VERSION 5.8 ;
BUSBITCHARS "[]" ;
DIVIDERCHAR "/" ;
UNITS
    DATABASE MICRONS 1000 ;
END UNITS

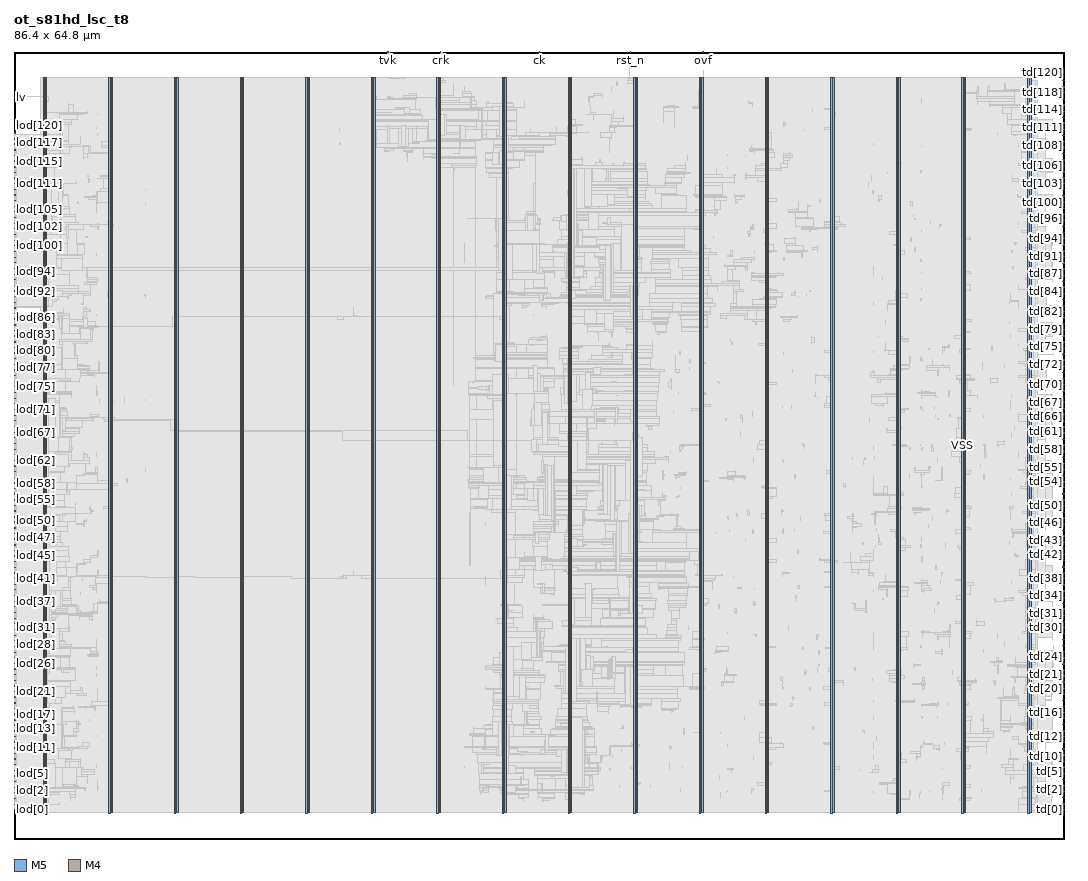
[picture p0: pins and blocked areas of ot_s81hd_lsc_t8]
MACRO ot_s81hd_lsc_t8
  FOREIGN ot_s81hd_lsc_t8 0 0 ;
  CLASS BLOCK ;
  SIZE 86.4 BY 64.8 ;
  PIN ck
    DIRECTION INPUT ;
    USE SIGNAL ;
    PORT
      LAYER M5 ;
        RECT  43.2 64.716 43.224 64.8 ;
    END
  END ck
  PIN crk
    DIRECTION INPUT ;
    USE SIGNAL ;
    PORT
      LAYER M5 ;
        RECT  35.088 64.716 35.112 64.8 ;
    END
  END crk
  PIN lod[0]
    DIRECTION OUTPUT ;
    USE SIGNAL ;
    PORT
      LAYER M4 ;
        RECT  0 2.4 0.084 2.424 ;
    END
  END lod[0]
  PIN lod[100]
    DIRECTION OUTPUT ;
    USE SIGNAL ;
    PORT
      LAYER M4 ;
        RECT  0 48.816 0.084 48.84 ;
    END
  END lod[100]
  PIN lod[101]
    DIRECTION OUTPUT ;
    USE SIGNAL ;
    PORT
      LAYER M4 ;
        RECT  0 49.248 0.084 49.272 ;
    END
  END lod[101]
  PIN lod[102]
    DIRECTION OUTPUT ;
    USE SIGNAL ;
    PORT
      LAYER M4 ;
        RECT  0 49.728 0.084 49.752 ;
    END
  END lod[102]
  PIN lod[103]
    DIRECTION OUTPUT ;
    USE SIGNAL ;
    PORT
      LAYER M4 ;
        RECT  0 50.208 0.084 50.232 ;
    END
  END lod[103]
  PIN lod[104]
    DIRECTION OUTPUT ;
    USE SIGNAL ;
    PORT
      LAYER M4 ;
        RECT  0 50.64 0.084 50.664 ;
    END
  END lod[104]
  PIN lod[105]
    DIRECTION OUTPUT ;
    USE SIGNAL ;
    PORT
      LAYER M4 ;
        RECT  0 51.12 0.084 51.144 ;
    END
  END lod[105]
  PIN lod[106]
    DIRECTION OUTPUT ;
    USE SIGNAL ;
    PORT
      LAYER M4 ;
        RECT  0 51.6 0.084 51.624 ;
    END
  END lod[106]
  PIN lod[107]
    DIRECTION OUTPUT ;
    USE SIGNAL ;
    PORT
      LAYER M4 ;
        RECT  0 52.032 0.084 52.056 ;
    END
  END lod[107]
  PIN lod[108]
    DIRECTION OUTPUT ;
    USE SIGNAL ;
    PORT
      LAYER M4 ;
        RECT  0 52.512 0.084 52.536 ;
    END
  END lod[108]
  PIN lod[109]
    DIRECTION OUTPUT ;
    USE SIGNAL ;
    PORT
      LAYER M4 ;
        RECT  0 52.992 0.084 53.016 ;
    END
  END lod[109]
  PIN lod[10]
    DIRECTION OUTPUT ;
    USE SIGNAL ;
    PORT
      LAYER M4 ;
        RECT  0 7.008 0.084 7.032 ;
    END
  END lod[10]
  PIN lod[110]
    DIRECTION OUTPUT ;
    USE SIGNAL ;
    PORT
      LAYER M4 ;
        RECT  0 53.424 0.084 53.448 ;
    END
  END lod[110]
  PIN lod[111]
    DIRECTION OUTPUT ;
    USE SIGNAL ;
    PORT
      LAYER M4 ;
        RECT  0 53.904 0.084 53.928 ;
    END
  END lod[111]
  PIN lod[112]
    DIRECTION OUTPUT ;
    USE SIGNAL ;
    PORT
      LAYER M4 ;
        RECT  0 54.384 0.084 54.408 ;
    END
  END lod[112]
  PIN lod[113]
    DIRECTION OUTPUT ;
    USE SIGNAL ;
    PORT
      LAYER M4 ;
        RECT  0 54.816 0.084 54.84 ;
    END
  END lod[113]
  PIN lod[114]
    DIRECTION OUTPUT ;
    USE SIGNAL ;
    PORT
      LAYER M4 ;
        RECT  0 55.296 0.084 55.32 ;
    END
  END lod[114]
  PIN lod[115]
    DIRECTION OUTPUT ;
    USE SIGNAL ;
    PORT
      LAYER M4 ;
        RECT  0 55.776 0.084 55.8 ;
    END
  END lod[115]
  PIN lod[116]
    DIRECTION OUTPUT ;
    USE SIGNAL ;
    PORT
      LAYER M4 ;
        RECT  0 56.208 0.084 56.232 ;
    END
  END lod[116]
  PIN lod[117]
    DIRECTION OUTPUT ;
    USE SIGNAL ;
    PORT
      LAYER M4 ;
        RECT  0 56.688 0.084 56.712 ;
    END
  END lod[117]
  PIN lod[118]
    DIRECTION OUTPUT ;
    USE SIGNAL ;
    PORT
      LAYER M4 ;
        RECT  0 57.168 0.084 57.192 ;
    END
  END lod[118]
  PIN lod[119]
    DIRECTION OUTPUT ;
    USE SIGNAL ;
    PORT
      LAYER M4 ;
        RECT  0 57.6 0.084 57.624 ;
    END
  END lod[119]
  PIN lod[11]
    DIRECTION OUTPUT ;
    USE SIGNAL ;
    PORT
      LAYER M4 ;
        RECT  0 7.488 0.084 7.512 ;
    END
  END lod[11]
  PIN lod[120]
    DIRECTION OUTPUT ;
    USE SIGNAL ;
    PORT
      LAYER M4 ;
        RECT  0 58.08 0.084 58.104 ;
    END
  END lod[120]
  PIN lod[12]
    DIRECTION OUTPUT ;
    USE SIGNAL ;
    PORT
      LAYER M4 ;
        RECT  0 7.968 0.084 7.992 ;
    END
  END lod[12]
  PIN lod[13]
    DIRECTION OUTPUT ;
    USE SIGNAL ;
    PORT
      LAYER M4 ;
        RECT  0 8.4 0.084 8.424 ;
    END
  END lod[13]
  PIN lod[14]
    DIRECTION OUTPUT ;
    USE SIGNAL ;
    PORT
      LAYER M4 ;
        RECT  0 8.88 0.084 8.904 ;
    END
  END lod[14]
  PIN lod[15]
    DIRECTION OUTPUT ;
    USE SIGNAL ;
    PORT
      LAYER M4 ;
        RECT  0 9.36 0.084 9.384 ;
    END
  END lod[15]
  PIN lod[16]
    DIRECTION OUTPUT ;
    USE SIGNAL ;
    PORT
      LAYER M4 ;
        RECT  0 9.792 0.084 9.816 ;
    END
  END lod[16]
  PIN lod[17]
    DIRECTION OUTPUT ;
    USE SIGNAL ;
    PORT
      LAYER M4 ;
        RECT  0 10.272 0.084 10.296 ;
    END
  END lod[17]
  PIN lod[18]
    DIRECTION OUTPUT ;
    USE SIGNAL ;
    PORT
      LAYER M4 ;
        RECT  0 10.752 0.084 10.776 ;
    END
  END lod[18]
  PIN lod[19]
    DIRECTION OUTPUT ;
    USE SIGNAL ;
    PORT
      LAYER M4 ;
        RECT  0 11.184 0.084 11.208 ;
    END
  END lod[19]
  PIN lod[1]
    DIRECTION OUTPUT ;
    USE SIGNAL ;
    PORT
      LAYER M4 ;
        RECT  0 2.832 0.084 2.856 ;
    END
  END lod[1]
  PIN lod[20]
    DIRECTION OUTPUT ;
    USE SIGNAL ;
    PORT
      LAYER M4 ;
        RECT  0 11.664 0.084 11.688 ;
    END
  END lod[20]
  PIN lod[21]
    DIRECTION OUTPUT ;
    USE SIGNAL ;
    PORT
      LAYER M4 ;
        RECT  0 12.144 0.084 12.168 ;
    END
  END lod[21]
  PIN lod[22]
    DIRECTION OUTPUT ;
    USE SIGNAL ;
    PORT
      LAYER M4 ;
        RECT  0 12.576 0.084 12.6 ;
    END
  END lod[22]
  PIN lod[23]
    DIRECTION OUTPUT ;
    USE SIGNAL ;
    PORT
      LAYER M4 ;
        RECT  0 13.056 0.084 13.08 ;
    END
  END lod[23]
  PIN lod[24]
    DIRECTION OUTPUT ;
    USE SIGNAL ;
    PORT
      LAYER M4 ;
        RECT  0 13.536 0.084 13.56 ;
    END
  END lod[24]
  PIN lod[25]
    DIRECTION OUTPUT ;
    USE SIGNAL ;
    PORT
      LAYER M4 ;
        RECT  0 13.968 0.084 13.992 ;
    END
  END lod[25]
  PIN lod[26]
    DIRECTION OUTPUT ;
    USE SIGNAL ;
    PORT
      LAYER M4 ;
        RECT  0 14.448 0.084 14.472 ;
    END
  END lod[26]
  PIN lod[27]
    DIRECTION OUTPUT ;
    USE SIGNAL ;
    PORT
      LAYER M4 ;
        RECT  0 14.928 0.084 14.952 ;
    END
  END lod[27]
  PIN lod[28]
    DIRECTION OUTPUT ;
    USE SIGNAL ;
    PORT
      LAYER M4 ;
        RECT  0 15.36 0.084 15.384 ;
    END
  END lod[28]
  PIN lod[29]
    DIRECTION OUTPUT ;
    USE SIGNAL ;
    PORT
      LAYER M4 ;
        RECT  0 15.84 0.084 15.864 ;
    END
  END lod[29]
  PIN lod[2]
    DIRECTION OUTPUT ;
    USE SIGNAL ;
    PORT
      LAYER M4 ;
        RECT  0 3.312 0.084 3.336 ;
    END
  END lod[2]
  PIN lod[30]
    DIRECTION OUTPUT ;
    USE SIGNAL ;
    PORT
      LAYER M4 ;
        RECT  0 16.32 0.084 16.344 ;
    END
  END lod[30]
  PIN lod[31]
    DIRECTION OUTPUT ;
    USE SIGNAL ;
    PORT
      LAYER M4 ;
        RECT  0 16.752 0.084 16.776 ;
    END
  END lod[31]
  PIN lod[32]
    DIRECTION OUTPUT ;
    USE SIGNAL ;
    PORT
      LAYER M4 ;
        RECT  0 17.232 0.084 17.256 ;
    END
  END lod[32]
  PIN lod[33]
    DIRECTION OUTPUT ;
    USE SIGNAL ;
    PORT
      LAYER M4 ;
        RECT  0 17.712 0.084 17.736 ;
    END
  END lod[33]
  PIN lod[34]
    DIRECTION OUTPUT ;
    USE SIGNAL ;
    PORT
      LAYER M4 ;
        RECT  0 18.144 0.084 18.168 ;
    END
  END lod[34]
  PIN lod[35]
    DIRECTION OUTPUT ;
    USE SIGNAL ;
    PORT
      LAYER M4 ;
        RECT  0 18.624 0.084 18.648 ;
    END
  END lod[35]
  PIN lod[36]
    DIRECTION OUTPUT ;
    USE SIGNAL ;
    PORT
      LAYER M4 ;
        RECT  0 19.104 0.084 19.128 ;
    END
  END lod[36]
  PIN lod[37]
    DIRECTION OUTPUT ;
    USE SIGNAL ;
    PORT
      LAYER M4 ;
        RECT  0 19.536 0.084 19.56 ;
    END
  END lod[37]
  PIN lod[38]
    DIRECTION OUTPUT ;
    USE SIGNAL ;
    PORT
      LAYER M4 ;
        RECT  0 20.016 0.084 20.04 ;
    END
  END lod[38]
  PIN lod[39]
    DIRECTION OUTPUT ;
    USE SIGNAL ;
    PORT
      LAYER M4 ;
        RECT  0 20.496 0.084 20.52 ;
    END
  END lod[39]
  PIN lod[3]
    DIRECTION OUTPUT ;
    USE SIGNAL ;
    PORT
      LAYER M4 ;
        RECT  0 3.792 0.084 3.816 ;
    END
  END lod[3]
  PIN lod[40]
    DIRECTION OUTPUT ;
    USE SIGNAL ;
    PORT
      LAYER M4 ;
        RECT  0 20.928 0.084 20.952 ;
    END
  END lod[40]
  PIN lod[41]
    DIRECTION OUTPUT ;
    USE SIGNAL ;
    PORT
      LAYER M4 ;
        RECT  0 21.408 0.084 21.432 ;
    END
  END lod[41]
  PIN lod[42]
    DIRECTION OUTPUT ;
    USE SIGNAL ;
    PORT
      LAYER M4 ;
        RECT  0 21.888 0.084 21.912 ;
    END
  END lod[42]
  PIN lod[43]
    DIRECTION OUTPUT ;
    USE SIGNAL ;
    PORT
      LAYER M4 ;
        RECT  0 22.32 0.084 22.344 ;
    END
  END lod[43]
  PIN lod[44]
    DIRECTION OUTPUT ;
    USE SIGNAL ;
    PORT
      LAYER M4 ;
        RECT  0 22.8 0.084 22.824 ;
    END
  END lod[44]
  PIN lod[45]
    DIRECTION OUTPUT ;
    USE SIGNAL ;
    PORT
      LAYER M4 ;
        RECT  0 23.28 0.084 23.304 ;
    END
  END lod[45]
  PIN lod[46]
    DIRECTION OUTPUT ;
    USE SIGNAL ;
    PORT
      LAYER M4 ;
        RECT  0 23.712 0.084 23.736 ;
    END
  END lod[46]
  PIN lod[47]
    DIRECTION OUTPUT ;
    USE SIGNAL ;
    PORT
      LAYER M4 ;
        RECT  0 24.192 0.084 24.216 ;
    END
  END lod[47]
  PIN lod[48]
    DIRECTION OUTPUT ;
    USE SIGNAL ;
    PORT
      LAYER M4 ;
        RECT  0 24.672 0.084 24.696 ;
    END
  END lod[48]
  PIN lod[49]
    DIRECTION OUTPUT ;
    USE SIGNAL ;
    PORT
      LAYER M4 ;
        RECT  0 25.104 0.084 25.128 ;
    END
  END lod[49]
  PIN lod[4]
    DIRECTION OUTPUT ;
    USE SIGNAL ;
    PORT
      LAYER M4 ;
        RECT  0 4.224 0.084 4.248 ;
    END
  END lod[4]
  PIN lod[50]
    DIRECTION OUTPUT ;
    USE SIGNAL ;
    PORT
      LAYER M4 ;
        RECT  0 25.584 0.084 25.608 ;
    END
  END lod[50]
  PIN lod[51]
    DIRECTION OUTPUT ;
    USE SIGNAL ;
    PORT
      LAYER M4 ;
        RECT  0 26.064 0.084 26.088 ;
    END
  END lod[51]
  PIN lod[52]
    DIRECTION OUTPUT ;
    USE SIGNAL ;
    PORT
      LAYER M4 ;
        RECT  0 26.496 0.084 26.52 ;
    END
  END lod[52]
  PIN lod[53]
    DIRECTION OUTPUT ;
    USE SIGNAL ;
    PORT
      LAYER M4 ;
        RECT  0 26.976 0.084 27 ;
    END
  END lod[53]
  PIN lod[54]
    DIRECTION OUTPUT ;
    USE SIGNAL ;
    PORT
      LAYER M4 ;
        RECT  0 27.456 0.084 27.48 ;
    END
  END lod[54]
  PIN lod[55]
    DIRECTION OUTPUT ;
    USE SIGNAL ;
    PORT
      LAYER M4 ;
        RECT  0 27.888 0.084 27.912 ;
    END
  END lod[55]
  PIN lod[56]
    DIRECTION OUTPUT ;
    USE SIGNAL ;
    PORT
      LAYER M4 ;
        RECT  0 28.368 0.084 28.392 ;
    END
  END lod[56]
  PIN lod[57]
    DIRECTION OUTPUT ;
    USE SIGNAL ;
    PORT
      LAYER M4 ;
        RECT  0 28.848 0.084 28.872 ;
    END
  END lod[57]
  PIN lod[58]
    DIRECTION OUTPUT ;
    USE SIGNAL ;
    PORT
      LAYER M4 ;
        RECT  0 29.28 0.084 29.304 ;
    END
  END lod[58]
  PIN lod[59]
    DIRECTION OUTPUT ;
    USE SIGNAL ;
    PORT
      LAYER M4 ;
        RECT  0 29.76 0.084 29.784 ;
    END
  END lod[59]
  PIN lod[5]
    DIRECTION OUTPUT ;
    USE SIGNAL ;
    PORT
      LAYER M4 ;
        RECT  0 4.704 0.084 4.728 ;
    END
  END lod[5]
  PIN lod[60]
    DIRECTION OUTPUT ;
    USE SIGNAL ;
    PORT
      LAYER M4 ;
        RECT  0 30.24 0.084 30.264 ;
    END
  END lod[60]
  PIN lod[61]
    DIRECTION OUTPUT ;
    USE SIGNAL ;
    PORT
      LAYER M4 ;
        RECT  0 30.672 0.084 30.696 ;
    END
  END lod[61]
  PIN lod[62]
    DIRECTION OUTPUT ;
    USE SIGNAL ;
    PORT
      LAYER M4 ;
        RECT  0 31.152 0.084 31.176 ;
    END
  END lod[62]
  PIN lod[63]
    DIRECTION OUTPUT ;
    USE SIGNAL ;
    PORT
      LAYER M4 ;
        RECT  0 31.632 0.084 31.656 ;
    END
  END lod[63]
  PIN lod[64]
    DIRECTION OUTPUT ;
    USE SIGNAL ;
    PORT
      LAYER M4 ;
        RECT  0 32.064 0.084 32.088 ;
    END
  END lod[64]
  PIN lod[65]
    DIRECTION OUTPUT ;
    USE SIGNAL ;
    PORT
      LAYER M4 ;
        RECT  0 32.544 0.084 32.568 ;
    END
  END lod[65]
  PIN lod[66]
    DIRECTION OUTPUT ;
    USE SIGNAL ;
    PORT
      LAYER M4 ;
        RECT  0 33.024 0.084 33.048 ;
    END
  END lod[66]
  PIN lod[67]
    DIRECTION OUTPUT ;
    USE SIGNAL ;
    PORT
      LAYER M4 ;
        RECT  0 33.456 0.084 33.48 ;
    END
  END lod[67]
  PIN lod[68]
    DIRECTION OUTPUT ;
    USE SIGNAL ;
    PORT
      LAYER M4 ;
        RECT  0 33.936 0.084 33.96 ;
    END
  END lod[68]
  PIN lod[69]
    DIRECTION OUTPUT ;
    USE SIGNAL ;
    PORT
      LAYER M4 ;
        RECT  0 34.416 0.084 34.44 ;
    END
  END lod[69]
  PIN lod[6]
    DIRECTION OUTPUT ;
    USE SIGNAL ;
    PORT
      LAYER M4 ;
        RECT  0 5.184 0.084 5.208 ;
    END
  END lod[6]
  PIN lod[70]
    DIRECTION OUTPUT ;
    USE SIGNAL ;
    PORT
      LAYER M4 ;
        RECT  0 34.848 0.084 34.872 ;
    END
  END lod[70]
  PIN lod[71]
    DIRECTION OUTPUT ;
    USE SIGNAL ;
    PORT
      LAYER M4 ;
        RECT  0 35.328 0.084 35.352 ;
    END
  END lod[71]
  PIN lod[72]
    DIRECTION OUTPUT ;
    USE SIGNAL ;
    PORT
      LAYER M4 ;
        RECT  0 35.808 0.084 35.832 ;
    END
  END lod[72]
  PIN lod[73]
    DIRECTION OUTPUT ;
    USE SIGNAL ;
    PORT
      LAYER M4 ;
        RECT  0 36.24 0.084 36.264 ;
    END
  END lod[73]
  PIN lod[74]
    DIRECTION OUTPUT ;
    USE SIGNAL ;
    PORT
      LAYER M4 ;
        RECT  0 36.72 0.084 36.744 ;
    END
  END lod[74]
  PIN lod[75]
    DIRECTION OUTPUT ;
    USE SIGNAL ;
    PORT
      LAYER M4 ;
        RECT  0 37.2 0.084 37.224 ;
    END
  END lod[75]
  PIN lod[76]
    DIRECTION OUTPUT ;
    USE SIGNAL ;
    PORT
      LAYER M4 ;
        RECT  0 37.632 0.084 37.656 ;
    END
  END lod[76]
  PIN lod[77]
    DIRECTION OUTPUT ;
    USE SIGNAL ;
    PORT
      LAYER M4 ;
        RECT  0 38.112 0.084 38.136 ;
    END
  END lod[77]
  PIN lod[78]
    DIRECTION OUTPUT ;
    USE SIGNAL ;
    PORT
      LAYER M4 ;
        RECT  0 38.592 0.084 38.616 ;
    END
  END lod[78]
  PIN lod[79]
    DIRECTION OUTPUT ;
    USE SIGNAL ;
    PORT
      LAYER M4 ;
        RECT  0 39.024 0.084 39.048 ;
    END
  END lod[79]
  PIN lod[7]
    DIRECTION OUTPUT ;
    USE SIGNAL ;
    PORT
      LAYER M4 ;
        RECT  0 5.616 0.084 5.64 ;
    END
  END lod[7]
  PIN lod[80]
    DIRECTION OUTPUT ;
    USE SIGNAL ;
    PORT
      LAYER M4 ;
        RECT  0 39.504 0.084 39.528 ;
    END
  END lod[80]
  PIN lod[81]
    DIRECTION OUTPUT ;
    USE SIGNAL ;
    PORT
      LAYER M4 ;
        RECT  0 39.984 0.084 40.008 ;
    END
  END lod[81]
  PIN lod[82]
    DIRECTION OUTPUT ;
    USE SIGNAL ;
    PORT
      LAYER M4 ;
        RECT  0 40.416 0.084 40.44 ;
    END
  END lod[82]
  PIN lod[83]
    DIRECTION OUTPUT ;
    USE SIGNAL ;
    PORT
      LAYER M4 ;
        RECT  0 40.896 0.084 40.92 ;
    END
  END lod[83]
  PIN lod[84]
    DIRECTION OUTPUT ;
    USE SIGNAL ;
    PORT
      LAYER M4 ;
        RECT  0 41.376 0.084 41.4 ;
    END
  END lod[84]
  PIN lod[85]
    DIRECTION OUTPUT ;
    USE SIGNAL ;
    PORT
      LAYER M4 ;
        RECT  0 41.808 0.084 41.832 ;
    END
  END lod[85]
  PIN lod[86]
    DIRECTION OUTPUT ;
    USE SIGNAL ;
    PORT
      LAYER M4 ;
        RECT  0 42.288 0.084 42.312 ;
    END
  END lod[86]
  PIN lod[87]
    DIRECTION OUTPUT ;
    USE SIGNAL ;
    PORT
      LAYER M4 ;
        RECT  0 42.768 0.084 42.792 ;
    END
  END lod[87]
  PIN lod[88]
    DIRECTION OUTPUT ;
    USE SIGNAL ;
    PORT
      LAYER M4 ;
        RECT  0 43.248 0.084 43.272 ;
    END
  END lod[88]
  PIN lod[89]
    DIRECTION OUTPUT ;
    USE SIGNAL ;
    PORT
      LAYER M4 ;
        RECT  0 43.68 0.084 43.704 ;
    END
  END lod[89]
  PIN lod[8]
    DIRECTION OUTPUT ;
    USE SIGNAL ;
    PORT
      LAYER M4 ;
        RECT  0 6.096 0.084 6.12 ;
    END
  END lod[8]
  PIN lod[90]
    DIRECTION OUTPUT ;
    USE SIGNAL ;
    PORT
      LAYER M4 ;
        RECT  0 44.16 0.084 44.184 ;
    END
  END lod[90]
  PIN lod[91]
    DIRECTION OUTPUT ;
    USE SIGNAL ;
    PORT
      LAYER M4 ;
        RECT  0 44.64 0.084 44.664 ;
    END
  END lod[91]
  PIN lod[92]
    DIRECTION OUTPUT ;
    USE SIGNAL ;
    PORT
      LAYER M4 ;
        RECT  0 45.072 0.084 45.096 ;
    END
  END lod[92]
  PIN lod[93]
    DIRECTION OUTPUT ;
    USE SIGNAL ;
    PORT
      LAYER M4 ;
        RECT  0 45.552 0.084 45.576 ;
    END
  END lod[93]
  PIN lod[94]
    DIRECTION OUTPUT ;
    USE SIGNAL ;
    PORT
      LAYER M4 ;
        RECT  0 46.032 0.084 46.056 ;
    END
  END lod[94]
  PIN lod[95]
    DIRECTION OUTPUT ;
    USE SIGNAL ;
    PORT
      LAYER M4 ;
        RECT  0 46.464 0.084 46.488 ;
    END
  END lod[95]
  PIN lod[96]
    DIRECTION OUTPUT ;
    USE SIGNAL ;
    PORT
      LAYER M4 ;
        RECT  0 46.944 0.084 46.968 ;
    END
  END lod[96]
  PIN lod[97]
    DIRECTION OUTPUT ;
    USE SIGNAL ;
    PORT
      LAYER M4 ;
        RECT  0 47.424 0.084 47.448 ;
    END
  END lod[97]
  PIN lod[98]
    DIRECTION OUTPUT ;
    USE SIGNAL ;
    PORT
      LAYER M4 ;
        RECT  0 47.856 0.084 47.88 ;
    END
  END lod[98]
  PIN lod[99]
    DIRECTION OUTPUT ;
    USE SIGNAL ;
    PORT
      LAYER M4 ;
        RECT  0 48.336 0.084 48.36 ;
    END
  END lod[99]
  PIN lod[9]
    DIRECTION OUTPUT ;
    USE SIGNAL ;
    PORT
      LAYER M4 ;
        RECT  0 6.576 0.084 6.6 ;
    END
  END lod[9]
  PIN lv
    DIRECTION OUTPUT ;
    USE SIGNAL ;
    PORT
      LAYER M4 ;
        RECT  0 61.008 0.084 61.032 ;
    END
  END lv
  PIN ovf
    DIRECTION OUTPUT ;
    USE SIGNAL ;
    PORT
      LAYER M5 ;
        RECT  56.688 64.716 56.712 64.8 ;
    END
  END ovf
  PIN rst_n
    DIRECTION INPUT ;
    USE SIGNAL ;
    PORT
      LAYER M5 ;
        RECT  50.736 64.716 50.76 64.8 ;
    END
  END rst_n
  PIN td[0]
    DIRECTION INPUT ;
    USE SIGNAL ;
    PORT
      LAYER M4 ;
        RECT  86.316 2.4 86.4 2.424 ;
    END
  END td[0]
  PIN td[100]
    DIRECTION INPUT ;
    USE SIGNAL ;
    PORT
      LAYER M4 ;
        RECT  86.316 52.368 86.4 52.392 ;
    END
  END td[100]
  PIN td[101]
    DIRECTION INPUT ;
    USE SIGNAL ;
    PORT
      LAYER M4 ;
        RECT  86.316 52.896 86.4 52.92 ;
    END
  END td[101]
  PIN td[102]
    DIRECTION INPUT ;
    USE SIGNAL ;
    PORT
      LAYER M4 ;
        RECT  86.316 53.376 86.4 53.4 ;
    END
  END td[102]
  PIN td[103]
    DIRECTION INPUT ;
    USE SIGNAL ;
    PORT
      LAYER M4 ;
        RECT  86.316 53.904 86.4 53.928 ;
    END
  END td[103]
  PIN td[104]
    DIRECTION INPUT ;
    USE SIGNAL ;
    PORT
      LAYER M4 ;
        RECT  86.316 54.384 86.4 54.408 ;
    END
  END td[104]
  PIN td[105]
    DIRECTION INPUT ;
    USE SIGNAL ;
    PORT
      LAYER M4 ;
        RECT  86.316 54.864 86.4 54.888 ;
    END
  END td[105]
  PIN td[106]
    DIRECTION INPUT ;
    USE SIGNAL ;
    PORT
      LAYER M4 ;
        RECT  86.316 55.392 86.4 55.416 ;
    END
  END td[106]
  PIN td[107]
    DIRECTION INPUT ;
    USE SIGNAL ;
    PORT
      LAYER M4 ;
        RECT  86.316 55.872 86.4 55.896 ;
    END
  END td[107]
  PIN td[108]
    DIRECTION INPUT ;
    USE SIGNAL ;
    PORT
      LAYER M4 ;
        RECT  86.316 56.4 86.4 56.424 ;
    END
  END td[108]
  PIN td[109]
    DIRECTION INPUT ;
    USE SIGNAL ;
    PORT
      LAYER M4 ;
        RECT  86.316 56.88 86.4 56.904 ;
    END
  END td[109]
  PIN td[10]
    DIRECTION INPUT ;
    USE SIGNAL ;
    PORT
      LAYER M4 ;
        RECT  86.316 7.392 86.4 7.416 ;
    END
  END td[10]
  PIN td[110]
    DIRECTION INPUT ;
    USE SIGNAL ;
    PORT
      LAYER M4 ;
        RECT  86.316 57.36 86.4 57.384 ;
    END
  END td[110]
  PIN td[111]
    DIRECTION INPUT ;
    USE SIGNAL ;
    PORT
      LAYER M4 ;
        RECT  86.316 57.888 86.4 57.912 ;
    END
  END td[111]
  PIN td[112]
    DIRECTION INPUT ;
    USE SIGNAL ;
    PORT
      LAYER M4 ;
        RECT  86.316 58.368 86.4 58.392 ;
    END
  END td[112]
  PIN td[113]
    DIRECTION INPUT ;
    USE SIGNAL ;
    PORT
      LAYER M4 ;
        RECT  86.316 58.896 86.4 58.92 ;
    END
  END td[113]
  PIN td[114]
    DIRECTION INPUT ;
    USE SIGNAL ;
    PORT
      LAYER M4 ;
        RECT  86.316 59.376 86.4 59.4 ;
    END
  END td[114]
  PIN td[115]
    DIRECTION INPUT ;
    USE SIGNAL ;
    PORT
      LAYER M4 ;
        RECT  86.316 59.856 86.4 59.88 ;
    END
  END td[115]
  PIN td[116]
    DIRECTION INPUT ;
    USE SIGNAL ;
    PORT
      LAYER M4 ;
        RECT  86.316 60.384 86.4 60.408 ;
    END
  END td[116]
  PIN td[117]
    DIRECTION INPUT ;
    USE SIGNAL ;
    PORT
      LAYER M4 ;
        RECT  86.316 60.864 86.4 60.888 ;
    END
  END td[117]
  PIN td[118]
    DIRECTION INPUT ;
    USE SIGNAL ;
    PORT
      LAYER M4 ;
        RECT  86.316 61.392 86.4 61.416 ;
    END
  END td[118]
  PIN td[119]
    DIRECTION INPUT ;
    USE SIGNAL ;
    PORT
      LAYER M4 ;
        RECT  86.316 61.872 86.4 61.896 ;
    END
  END td[119]
  PIN td[11]
    DIRECTION INPUT ;
    USE SIGNAL ;
    PORT
      LAYER M4 ;
        RECT  86.316 7.92 86.4 7.944 ;
    END
  END td[11]
  PIN td[120]
    DIRECTION INPUT ;
    USE SIGNAL ;
    PORT
      LAYER M4 ;
        RECT  86.316 62.4 86.4 62.424 ;
    END
  END td[120]
  PIN td[12]
    DIRECTION INPUT ;
    USE SIGNAL ;
    PORT
      LAYER M4 ;
        RECT  86.316 8.4 86.4 8.424 ;
    END
  END td[12]
  PIN td[13]
    DIRECTION INPUT ;
    USE SIGNAL ;
    PORT
      LAYER M4 ;
        RECT  86.316 8.88 86.4 8.904 ;
    END
  END td[13]
  PIN td[14]
    DIRECTION INPUT ;
    USE SIGNAL ;
    PORT
      LAYER M4 ;
        RECT  86.316 9.408 86.4 9.432 ;
    END
  END td[14]
  PIN td[15]
    DIRECTION INPUT ;
    USE SIGNAL ;
    PORT
      LAYER M4 ;
        RECT  86.316 9.888 86.4 9.912 ;
    END
  END td[15]
  PIN td[16]
    DIRECTION INPUT ;
    USE SIGNAL ;
    PORT
      LAYER M4 ;
        RECT  86.316 10.416 86.4 10.44 ;
    END
  END td[16]
  PIN td[17]
    DIRECTION INPUT ;
    USE SIGNAL ;
    PORT
      LAYER M4 ;
        RECT  86.316 10.896 86.4 10.92 ;
    END
  END td[17]
  PIN td[18]
    DIRECTION INPUT ;
    USE SIGNAL ;
    PORT
      LAYER M4 ;
        RECT  86.316 11.376 86.4 11.4 ;
    END
  END td[18]
  PIN td[19]
    DIRECTION INPUT ;
    USE SIGNAL ;
    PORT
      LAYER M4 ;
        RECT  86.316 11.904 86.4 11.928 ;
    END
  END td[19]
  PIN td[1]
    DIRECTION INPUT ;
    USE SIGNAL ;
    PORT
      LAYER M4 ;
        RECT  86.316 2.88 86.4 2.904 ;
    END
  END td[1]
  PIN td[20]
    DIRECTION INPUT ;
    USE SIGNAL ;
    PORT
      LAYER M4 ;
        RECT  86.316 12.384 86.4 12.408 ;
    END
  END td[20]
  PIN td[21]
    DIRECTION INPUT ;
    USE SIGNAL ;
    PORT
      LAYER M4 ;
        RECT  86.316 12.912 86.4 12.936 ;
    END
  END td[21]
  PIN td[22]
    DIRECTION INPUT ;
    USE SIGNAL ;
    PORT
      LAYER M4 ;
        RECT  86.316 13.392 86.4 13.416 ;
    END
  END td[22]
  PIN td[23]
    DIRECTION INPUT ;
    USE SIGNAL ;
    PORT
      LAYER M4 ;
        RECT  86.316 13.872 86.4 13.896 ;
    END
  END td[23]
  PIN td[24]
    DIRECTION INPUT ;
    USE SIGNAL ;
    PORT
      LAYER M4 ;
        RECT  86.316 14.4 86.4 14.424 ;
    END
  END td[24]
  PIN td[25]
    DIRECTION INPUT ;
    USE SIGNAL ;
    PORT
      LAYER M4 ;
        RECT  86.316 14.88 86.4 14.904 ;
    END
  END td[25]
  PIN td[26]
    DIRECTION INPUT ;
    USE SIGNAL ;
    PORT
      LAYER M4 ;
        RECT  86.316 15.408 86.4 15.432 ;
    END
  END td[26]
  PIN td[27]
    DIRECTION INPUT ;
    USE SIGNAL ;
    PORT
      LAYER M4 ;
        RECT  86.316 15.888 86.4 15.912 ;
    END
  END td[27]
  PIN td[28]
    DIRECTION INPUT ;
    USE SIGNAL ;
    PORT
      LAYER M4 ;
        RECT  86.316 16.416 86.4 16.44 ;
    END
  END td[28]
  PIN td[29]
    DIRECTION INPUT ;
    USE SIGNAL ;
    PORT
      LAYER M4 ;
        RECT  86.316 16.896 86.4 16.92 ;
    END
  END td[29]
  PIN td[2]
    DIRECTION INPUT ;
    USE SIGNAL ;
    PORT
      LAYER M4 ;
        RECT  86.316 3.408 86.4 3.432 ;
    END
  END td[2]
  PIN td[30]
    DIRECTION INPUT ;
    USE SIGNAL ;
    PORT
      LAYER M4 ;
        RECT  86.316 17.376 86.4 17.4 ;
    END
  END td[30]
  PIN td[31]
    DIRECTION INPUT ;
    USE SIGNAL ;
    PORT
      LAYER M4 ;
        RECT  86.316 17.904 86.4 17.928 ;
    END
  END td[31]
  PIN td[32]
    DIRECTION INPUT ;
    USE SIGNAL ;
    PORT
      LAYER M4 ;
        RECT  86.316 18.384 86.4 18.408 ;
    END
  END td[32]
  PIN td[33]
    DIRECTION INPUT ;
    USE SIGNAL ;
    PORT
      LAYER M4 ;
        RECT  86.316 18.912 86.4 18.936 ;
    END
  END td[33]
  PIN td[34]
    DIRECTION INPUT ;
    USE SIGNAL ;
    PORT
      LAYER M4 ;
        RECT  86.316 19.392 86.4 19.416 ;
    END
  END td[34]
  PIN td[35]
    DIRECTION INPUT ;
    USE SIGNAL ;
    PORT
      LAYER M4 ;
        RECT  86.316 19.872 86.4 19.896 ;
    END
  END td[35]
  PIN td[36]
    DIRECTION INPUT ;
    USE SIGNAL ;
    PORT
      LAYER M4 ;
        RECT  86.316 20.4 86.4 20.424 ;
    END
  END td[36]
  PIN td[37]
    DIRECTION INPUT ;
    USE SIGNAL ;
    PORT
      LAYER M4 ;
        RECT  86.316 20.88 86.4 20.904 ;
    END
  END td[37]
  PIN td[38]
    DIRECTION INPUT ;
    USE SIGNAL ;
    PORT
      LAYER M4 ;
        RECT  86.316 21.408 86.4 21.432 ;
    END
  END td[38]
  PIN td[39]
    DIRECTION INPUT ;
    USE SIGNAL ;
    PORT
      LAYER M4 ;
        RECT  86.316 21.888 86.4 21.912 ;
    END
  END td[39]
  PIN td[3]
    DIRECTION INPUT ;
    USE SIGNAL ;
    PORT
      LAYER M4 ;
        RECT  86.316 3.888 86.4 3.912 ;
    END
  END td[3]
  PIN td[40]
    DIRECTION INPUT ;
    USE SIGNAL ;
    PORT
      LAYER M4 ;
        RECT  86.316 22.368 86.4 22.392 ;
    END
  END td[40]
  PIN td[41]
    DIRECTION INPUT ;
    USE SIGNAL ;
    PORT
      LAYER M4 ;
        RECT  86.316 22.896 86.4 22.92 ;
    END
  END td[41]
  PIN td[42]
    DIRECTION INPUT ;
    USE SIGNAL ;
    PORT
      LAYER M4 ;
        RECT  86.316 23.376 86.4 23.4 ;
    END
  END td[42]
  PIN td[43]
    DIRECTION INPUT ;
    USE SIGNAL ;
    PORT
      LAYER M4 ;
        RECT  86.316 23.904 86.4 23.928 ;
    END
  END td[43]
  PIN td[44]
    DIRECTION INPUT ;
    USE SIGNAL ;
    PORT
      LAYER M4 ;
        RECT  86.316 24.384 86.4 24.408 ;
    END
  END td[44]
  PIN td[45]
    DIRECTION INPUT ;
    USE SIGNAL ;
    PORT
      LAYER M4 ;
        RECT  86.316 24.912 86.4 24.936 ;
    END
  END td[45]
  PIN td[46]
    DIRECTION INPUT ;
    USE SIGNAL ;
    PORT
      LAYER M4 ;
        RECT  86.316 25.392 86.4 25.416 ;
    END
  END td[46]
  PIN td[47]
    DIRECTION INPUT ;
    USE SIGNAL ;
    PORT
      LAYER M4 ;
        RECT  86.316 25.872 86.4 25.896 ;
    END
  END td[47]
  PIN td[48]
    DIRECTION INPUT ;
    USE SIGNAL ;
    PORT
      LAYER M4 ;
        RECT  86.316 26.4 86.4 26.424 ;
    END
  END td[48]
  PIN td[49]
    DIRECTION INPUT ;
    USE SIGNAL ;
    PORT
      LAYER M4 ;
        RECT  86.316 26.88 86.4 26.904 ;
    END
  END td[49]
  PIN td[4]
    DIRECTION INPUT ;
    USE SIGNAL ;
    PORT
      LAYER M4 ;
        RECT  86.316 4.416 86.4 4.44 ;
    END
  END td[4]
  PIN td[50]
    DIRECTION INPUT ;
    USE SIGNAL ;
    PORT
      LAYER M4 ;
        RECT  86.316 27.408 86.4 27.432 ;
    END
  END td[50]
  PIN td[51]
    DIRECTION INPUT ;
    USE SIGNAL ;
    PORT
      LAYER M4 ;
        RECT  86.316 27.888 86.4 27.912 ;
    END
  END td[51]
  PIN td[52]
    DIRECTION INPUT ;
    USE SIGNAL ;
    PORT
      LAYER M4 ;
        RECT  86.316 28.368 86.4 28.392 ;
    END
  END td[52]
  PIN td[53]
    DIRECTION INPUT ;
    USE SIGNAL ;
    PORT
      LAYER M4 ;
        RECT  86.316 28.896 86.4 28.92 ;
    END
  END td[53]
  PIN td[54]
    DIRECTION INPUT ;
    USE SIGNAL ;
    PORT
      LAYER M4 ;
        RECT  86.316 29.376 86.4 29.4 ;
    END
  END td[54]
  PIN td[55]
    DIRECTION INPUT ;
    USE SIGNAL ;
    PORT
      LAYER M4 ;
        RECT  86.316 29.904 86.4 29.928 ;
    END
  END td[55]
  PIN td[56]
    DIRECTION INPUT ;
    USE SIGNAL ;
    PORT
      LAYER M4 ;
        RECT  86.316 30.384 86.4 30.408 ;
    END
  END td[56]
  PIN td[57]
    DIRECTION INPUT ;
    USE SIGNAL ;
    PORT
      LAYER M4 ;
        RECT  86.316 30.912 86.4 30.936 ;
    END
  END td[57]
  PIN td[58]
    DIRECTION INPUT ;
    USE SIGNAL ;
    PORT
      LAYER M4 ;
        RECT  86.316 31.392 86.4 31.416 ;
    END
  END td[58]
  PIN td[59]
    DIRECTION INPUT ;
    USE SIGNAL ;
    PORT
      LAYER M4 ;
        RECT  86.316 31.872 86.4 31.896 ;
    END
  END td[59]
  PIN td[5]
    DIRECTION INPUT ;
    USE SIGNAL ;
    PORT
      LAYER M4 ;
        RECT  86.316 4.896 86.4 4.92 ;
    END
  END td[5]
  PIN td[60]
    DIRECTION INPUT ;
    USE SIGNAL ;
    PORT
      LAYER M4 ;
        RECT  86.316 32.4 86.4 32.424 ;
    END
  END td[60]
  PIN td[61]
    DIRECTION INPUT ;
    USE SIGNAL ;
    PORT
      LAYER M4 ;
        RECT  86.316 32.88 86.4 32.904 ;
    END
  END td[61]
  PIN td[62]
    DIRECTION INPUT ;
    USE SIGNAL ;
    PORT
      LAYER M4 ;
        RECT  86.316 33.408 86.4 33.432 ;
    END
  END td[62]
  PIN td[63]
    DIRECTION INPUT ;
    USE SIGNAL ;
    PORT
      LAYER M4 ;
        RECT  86.316 33.888 86.4 33.912 ;
    END
  END td[63]
  PIN td[64]
    DIRECTION INPUT ;
    USE SIGNAL ;
    PORT
      LAYER M4 ;
        RECT  86.316 34.368 86.4 34.392 ;
    END
  END td[64]
  PIN td[65]
    DIRECTION INPUT ;
    USE SIGNAL ;
    PORT
      LAYER M4 ;
        RECT  86.316 34.896 86.4 34.92 ;
    END
  END td[65]
  PIN td[66]
    DIRECTION INPUT ;
    USE SIGNAL ;
    PORT
      LAYER M4 ;
        RECT  86.316 35.376 86.4 35.4 ;
    END
  END td[66]
  PIN td[67]
    DIRECTION INPUT ;
    USE SIGNAL ;
    PORT
      LAYER M4 ;
        RECT  86.316 35.904 86.4 35.928 ;
    END
  END td[67]
  PIN td[68]
    DIRECTION INPUT ;
    USE SIGNAL ;
    PORT
      LAYER M4 ;
        RECT  86.316 36.384 86.4 36.408 ;
    END
  END td[68]
  PIN td[69]
    DIRECTION INPUT ;
    USE SIGNAL ;
    PORT
      LAYER M4 ;
        RECT  86.316 36.864 86.4 36.888 ;
    END
  END td[69]
  PIN td[6]
    DIRECTION INPUT ;
    USE SIGNAL ;
    PORT
      LAYER M4 ;
        RECT  86.316 5.376 86.4 5.4 ;
    END
  END td[6]
  PIN td[70]
    DIRECTION INPUT ;
    USE SIGNAL ;
    PORT
      LAYER M4 ;
        RECT  86.316 37.392 86.4 37.416 ;
    END
  END td[70]
  PIN td[71]
    DIRECTION INPUT ;
    USE SIGNAL ;
    PORT
      LAYER M4 ;
        RECT  86.316 37.872 86.4 37.896 ;
    END
  END td[71]
  PIN td[72]
    DIRECTION INPUT ;
    USE SIGNAL ;
    PORT
      LAYER M4 ;
        RECT  86.316 38.4 86.4 38.424 ;
    END
  END td[72]
  PIN td[73]
    DIRECTION INPUT ;
    USE SIGNAL ;
    PORT
      LAYER M4 ;
        RECT  86.316 38.88 86.4 38.904 ;
    END
  END td[73]
  PIN td[74]
    DIRECTION INPUT ;
    USE SIGNAL ;
    PORT
      LAYER M4 ;
        RECT  86.316 39.408 86.4 39.432 ;
    END
  END td[74]
  PIN td[75]
    DIRECTION INPUT ;
    USE SIGNAL ;
    PORT
      LAYER M4 ;
        RECT  86.316 39.888 86.4 39.912 ;
    END
  END td[75]
  PIN td[76]
    DIRECTION INPUT ;
    USE SIGNAL ;
    PORT
      LAYER M4 ;
        RECT  86.316 40.368 86.4 40.392 ;
    END
  END td[76]
  PIN td[77]
    DIRECTION INPUT ;
    USE SIGNAL ;
    PORT
      LAYER M4 ;
        RECT  86.316 40.896 86.4 40.92 ;
    END
  END td[77]
  PIN td[78]
    DIRECTION INPUT ;
    USE SIGNAL ;
    PORT
      LAYER M4 ;
        RECT  86.316 41.376 86.4 41.4 ;
    END
  END td[78]
  PIN td[79]
    DIRECTION INPUT ;
    USE SIGNAL ;
    PORT
      LAYER M4 ;
        RECT  86.316 41.904 86.4 41.928 ;
    END
  END td[79]
  PIN td[7]
    DIRECTION INPUT ;
    USE SIGNAL ;
    PORT
      LAYER M4 ;
        RECT  86.316 5.904 86.4 5.928 ;
    END
  END td[7]
  PIN td[80]
    DIRECTION INPUT ;
    USE SIGNAL ;
    PORT
      LAYER M4 ;
        RECT  86.316 42.384 86.4 42.408 ;
    END
  END td[80]
  PIN td[81]
    DIRECTION INPUT ;
    USE SIGNAL ;
    PORT
      LAYER M4 ;
        RECT  86.316 42.864 86.4 42.888 ;
    END
  END td[81]
  PIN td[82]
    DIRECTION INPUT ;
    USE SIGNAL ;
    PORT
      LAYER M4 ;
        RECT  86.316 43.392 86.4 43.416 ;
    END
  END td[82]
  PIN td[83]
    DIRECTION INPUT ;
    USE SIGNAL ;
    PORT
      LAYER M4 ;
        RECT  86.316 43.872 86.4 43.896 ;
    END
  END td[83]
  PIN td[84]
    DIRECTION INPUT ;
    USE SIGNAL ;
    PORT
      LAYER M4 ;
        RECT  86.316 44.4 86.4 44.424 ;
    END
  END td[84]
  PIN td[85]
    DIRECTION INPUT ;
    USE SIGNAL ;
    PORT
      LAYER M4 ;
        RECT  86.316 44.88 86.4 44.904 ;
    END
  END td[85]
  PIN td[86]
    DIRECTION INPUT ;
    USE SIGNAL ;
    PORT
      LAYER M4 ;
        RECT  86.316 45.408 86.4 45.432 ;
    END
  END td[86]
  PIN td[87]
    DIRECTION INPUT ;
    USE SIGNAL ;
    PORT
      LAYER M4 ;
        RECT  86.316 45.888 86.4 45.912 ;
    END
  END td[87]
  PIN td[88]
    DIRECTION INPUT ;
    USE SIGNAL ;
    PORT
      LAYER M4 ;
        RECT  86.316 46.368 86.4 46.392 ;
    END
  END td[88]
  PIN td[89]
    DIRECTION INPUT ;
    USE SIGNAL ;
    PORT
      LAYER M4 ;
        RECT  86.316 46.896 86.4 46.92 ;
    END
  END td[89]
  PIN td[8]
    DIRECTION INPUT ;
    USE SIGNAL ;
    PORT
      LAYER M4 ;
        RECT  86.316 6.384 86.4 6.408 ;
    END
  END td[8]
  PIN td[90]
    DIRECTION INPUT ;
    USE SIGNAL ;
    PORT
      LAYER M4 ;
        RECT  86.316 47.376 86.4 47.4 ;
    END
  END td[90]
  PIN td[91]
    DIRECTION INPUT ;
    USE SIGNAL ;
    PORT
      LAYER M4 ;
        RECT  86.316 47.904 86.4 47.928 ;
    END
  END td[91]
  PIN td[92]
    DIRECTION INPUT ;
    USE SIGNAL ;
    PORT
      LAYER M4 ;
        RECT  86.316 48.384 86.4 48.408 ;
    END
  END td[92]
  PIN td[93]
    DIRECTION INPUT ;
    USE SIGNAL ;
    PORT
      LAYER M4 ;
        RECT  86.316 48.864 86.4 48.888 ;
    END
  END td[93]
  PIN td[94]
    DIRECTION INPUT ;
    USE SIGNAL ;
    PORT
      LAYER M4 ;
        RECT  86.316 49.392 86.4 49.416 ;
    END
  END td[94]
  PIN td[95]
    DIRECTION INPUT ;
    USE SIGNAL ;
    PORT
      LAYER M4 ;
        RECT  86.316 49.872 86.4 49.896 ;
    END
  END td[95]
  PIN td[96]
    DIRECTION INPUT ;
    USE SIGNAL ;
    PORT
      LAYER M4 ;
        RECT  86.316 50.4 86.4 50.424 ;
    END
  END td[96]
  PIN td[97]
    DIRECTION INPUT ;
    USE SIGNAL ;
    PORT
      LAYER M4 ;
        RECT  86.316 50.88 86.4 50.904 ;
    END
  END td[97]
  PIN td[98]
    DIRECTION INPUT ;
    USE SIGNAL ;
    PORT
      LAYER M4 ;
        RECT  86.316 51.36 86.4 51.384 ;
    END
  END td[98]
  PIN td[99]
    DIRECTION INPUT ;
    USE SIGNAL ;
    PORT
      LAYER M4 ;
        RECT  86.316 51.888 86.4 51.912 ;
    END
  END td[99]
  PIN td[9]
    DIRECTION INPUT ;
    USE SIGNAL ;
    PORT
      LAYER M4 ;
        RECT  86.316 6.912 86.4 6.936 ;
    END
  END td[9]
  PIN tvk
    DIRECTION INPUT ;
    USE SIGNAL ;
    PORT
      LAYER M5 ;
        RECT  30.768 64.716 30.792 64.8 ;
    END
  END tvk
  PIN VSS
    DIRECTION INOUT ;
    USE GROUND ;
    PORT
      LAYER M5 ;
        RECT  83.4 2.137 83.52 62.663 ;
        RECT  78 2.137 78.12 62.663 ;
        RECT  72.6 2.137 72.72 62.663 ;
        RECT  67.2 2.137 67.32 62.663 ;
        RECT  61.8 2.137 61.92 62.663 ;
        RECT  56.4 2.137 56.52 62.663 ;
        RECT  51 2.137 51.12 62.663 ;
        RECT  45.6 2.137 45.72 62.663 ;
        RECT  40.2 2.137 40.32 62.663 ;
        RECT  34.8 2.137 34.92 62.663 ;
        RECT  29.4 2.137 29.52 62.663 ;
        RECT  24 2.137 24.12 62.663 ;
        RECT  18.6 2.137 18.72 62.663 ;
        RECT  13.2 2.137 13.32 62.663 ;
        RECT  7.8 2.137 7.92 62.663 ;
        RECT  2.4 2.137 2.52 62.663 ;
    END
  END VSS
  PIN VDD
    DIRECTION INOUT ;
    USE POWER ;
    PORT
      LAYER M5 ;
        RECT  83.592 2.151 83.712 62.649 ;
        RECT  78.192 2.151 78.312 62.649 ;
        RECT  72.792 2.151 72.912 62.649 ;
        RECT  67.392 2.151 67.512 62.649 ;
        RECT  61.992 2.151 62.112 62.649 ;
        RECT  56.592 2.151 56.712 62.649 ;
        RECT  51.192 2.151 51.312 62.649 ;
        RECT  45.792 2.151 45.912 62.649 ;
        RECT  40.392 2.151 40.512 62.649 ;
        RECT  34.992 2.151 35.112 62.649 ;
        RECT  29.592 2.151 29.712 62.649 ;
        RECT  24.192 2.151 24.312 62.649 ;
        RECT  18.792 2.151 18.912 62.649 ;
        RECT  13.392 2.151 13.512 62.649 ;
        RECT  7.992 2.151 8.112 62.649 ;
        RECT  2.592 2.151 2.712 62.649 ;
    END
  END VDD
  OBS
    LAYER RVTN ;
     RECT  2.16 2.16 84.24 2.295 ;
     RECT  2.16 2.565 84.24 2.835 ;
     RECT  2.16 3.105 84.24 3.375 ;
     RECT  2.16 3.645 84.24 3.915 ;
     RECT  2.16 4.185 84.24 4.455 ;
     RECT  2.16 4.725 84.24 4.995 ;
     RECT  2.16 5.265 84.24 5.535 ;
     RECT  2.16 5.805 84.24 6.075 ;
     RECT  2.16 6.345 84.24 6.615 ;
     RECT  2.16 6.885 84.24 7.155 ;
     RECT  2.16 7.425 84.24 7.695 ;
     RECT  2.16 7.965 84.24 8.235 ;
     RECT  2.16 8.505 84.24 8.775 ;
     RECT  2.16 9.045 84.24 9.315 ;
     RECT  2.16 9.585 84.24 9.855 ;
     RECT  2.16 10.125 84.24 10.395 ;
     RECT  2.16 10.665 84.24 10.935 ;
     RECT  2.16 11.205 84.24 11.475 ;
     RECT  2.16 11.745 84.24 12.015 ;
     RECT  2.16 12.285 84.24 12.555 ;
     RECT  2.16 12.825 84.24 13.095 ;
     RECT  2.16 13.365 84.24 13.635 ;
     RECT  2.16 13.905 84.24 14.175 ;
     RECT  2.16 14.445 84.24 14.715 ;
     RECT  2.16 14.985 84.24 15.255 ;
     RECT  2.16 15.525 84.24 15.795 ;
     RECT  2.16 16.065 84.24 16.335 ;
     RECT  2.16 16.605 84.24 16.875 ;
     RECT  2.16 17.145 84.24 17.415 ;
     RECT  2.16 17.685 84.24 17.955 ;
     RECT  2.16 18.225 84.24 18.495 ;
     RECT  2.16 18.765 84.24 19.035 ;
     RECT  2.16 19.305 84.24 19.575 ;
     RECT  2.16 19.845 84.24 20.115 ;
     RECT  2.16 20.385 84.24 20.655 ;
     RECT  2.16 20.925 84.24 21.195 ;
     RECT  2.16 21.465 84.24 21.735 ;
     RECT  2.16 22.005 84.24 22.275 ;
     RECT  2.16 22.545 84.24 22.815 ;
     RECT  2.16 23.085 84.24 23.355 ;
     RECT  2.16 23.625 84.24 23.895 ;
     RECT  2.16 24.165 84.24 24.435 ;
     RECT  2.16 24.705 84.24 24.975 ;
     RECT  2.16 25.245 84.24 25.515 ;
     RECT  2.16 25.785 84.24 26.055 ;
     RECT  2.16 26.325 84.24 26.595 ;
     RECT  2.16 26.865 84.24 27.135 ;
     RECT  2.16 27.405 84.24 27.675 ;
     RECT  2.16 27.945 84.24 28.215 ;
     RECT  2.16 28.485 84.24 28.755 ;
     RECT  2.16 29.025 84.24 29.295 ;
     RECT  2.16 29.565 84.24 29.835 ;
     RECT  2.16 30.105 84.24 30.375 ;
     RECT  2.16 30.645 84.24 30.915 ;
     RECT  2.16 31.185 84.24 31.455 ;
     RECT  2.16 31.725 84.24 31.995 ;
     RECT  2.16 32.265 84.24 32.535 ;
     RECT  2.16 32.805 84.24 33.075 ;
     RECT  2.16 33.345 84.24 33.615 ;
     RECT  2.16 33.885 84.24 34.155 ;
     RECT  2.16 34.425 84.24 34.695 ;
     RECT  2.16 34.965 84.24 35.235 ;
     RECT  2.16 35.505 84.24 35.775 ;
     RECT  2.16 36.045 84.24 36.315 ;
     RECT  2.16 36.585 84.24 36.855 ;
     RECT  2.16 37.125 84.24 37.395 ;
     RECT  2.16 37.665 84.24 37.935 ;
     RECT  2.16 38.205 84.24 38.475 ;
     RECT  2.16 38.745 84.24 39.015 ;
     RECT  2.16 39.285 84.24 39.555 ;
     RECT  2.16 39.825 84.24 40.095 ;
     RECT  2.16 40.365 84.24 40.635 ;
     RECT  2.16 40.905 84.24 41.175 ;
     RECT  2.16 41.445 84.24 41.715 ;
     RECT  2.16 41.985 84.24 42.255 ;
     RECT  2.16 42.525 84.24 42.795 ;
     RECT  2.16 43.065 84.24 43.335 ;
     RECT  2.16 43.605 84.24 43.875 ;
     RECT  2.16 44.145 84.24 44.415 ;
     RECT  2.16 44.685 84.24 44.955 ;
     RECT  2.16 45.225 84.24 45.495 ;
     RECT  2.16 45.765 84.24 46.035 ;
     RECT  2.16 46.305 84.24 46.575 ;
     RECT  2.16 46.845 84.24 47.115 ;
     RECT  2.16 47.385 84.24 47.655 ;
     RECT  2.16 47.925 84.24 48.195 ;
     RECT  2.16 48.465 84.24 48.735 ;
     RECT  2.16 49.005 84.24 49.275 ;
     RECT  2.16 49.545 84.24 49.815 ;
     RECT  2.16 50.085 84.24 50.355 ;
     RECT  2.16 50.625 84.24 50.895 ;
     RECT  2.16 51.165 84.24 51.435 ;
     RECT  2.16 51.705 84.24 51.975 ;
     RECT  2.16 52.245 84.24 52.515 ;
     RECT  2.16 52.785 84.24 53.055 ;
     RECT  2.16 53.325 84.24 53.595 ;
     RECT  2.16 53.865 84.24 54.135 ;
     RECT  2.16 54.405 84.24 54.675 ;
     RECT  2.16 54.945 84.24 55.215 ;
     RECT  2.16 55.485 84.24 55.755 ;
     RECT  2.16 56.025 84.24 56.295 ;
     RECT  2.16 56.565 84.24 56.835 ;
     RECT  2.16 57.105 84.24 57.375 ;
     RECT  2.16 57.645 84.24 57.915 ;
     RECT  2.16 58.185 84.24 58.455 ;
     RECT  2.16 58.725 84.24 58.995 ;
     RECT  2.16 59.265 84.24 59.535 ;
     RECT  2.16 59.805 84.24 60.075 ;
     RECT  2.16 60.345 84.24 60.615 ;
     RECT  2.16 60.885 84.24 61.155 ;
     RECT  2.16 61.425 84.24 61.695 ;
     RECT  2.16 61.965 84.24 62.235 ;
     RECT  2.16 62.505 84.24 62.64 ;
    LAYER RVTP ;
     RECT  2.16 2.295 84.24 2.565 ;
     RECT  2.16 2.835 84.24 3.105 ;
     RECT  2.16 3.375 84.24 3.645 ;
     RECT  2.16 3.915 84.24 4.185 ;
     RECT  2.16 4.455 84.24 4.725 ;
     RECT  2.16 4.995 84.24 5.265 ;
     RECT  2.16 5.535 84.24 5.805 ;
     RECT  2.16 6.075 84.24 6.345 ;
     RECT  2.16 6.615 84.24 6.885 ;
     RECT  2.16 7.155 84.24 7.425 ;
     RECT  2.16 7.695 84.24 7.965 ;
     RECT  2.16 8.235 84.24 8.505 ;
     RECT  2.16 8.775 84.24 9.045 ;
     RECT  2.16 9.315 84.24 9.585 ;
     RECT  2.16 9.855 84.24 10.125 ;
     RECT  2.16 10.395 84.24 10.665 ;
     RECT  2.16 10.935 84.24 11.205 ;
     RECT  2.16 11.475 84.24 11.745 ;
     RECT  2.16 12.015 84.24 12.285 ;
     RECT  2.16 12.555 84.24 12.825 ;
     RECT  2.16 13.095 84.24 13.365 ;
     RECT  2.16 13.635 84.24 13.905 ;
     RECT  2.16 14.175 84.24 14.445 ;
     RECT  2.16 14.715 84.24 14.985 ;
     RECT  2.16 15.255 84.24 15.525 ;
     RECT  2.16 15.795 84.24 16.065 ;
     RECT  2.16 16.335 84.24 16.605 ;
     RECT  2.16 16.875 84.24 17.145 ;
     RECT  2.16 17.415 84.24 17.685 ;
     RECT  2.16 17.955 84.24 18.225 ;
     RECT  2.16 18.495 84.24 18.765 ;
     RECT  2.16 19.035 84.24 19.305 ;
     RECT  2.16 19.575 84.24 19.845 ;
     RECT  2.16 20.115 84.24 20.385 ;
     RECT  2.16 20.655 84.24 20.925 ;
     RECT  2.16 21.195 84.24 21.465 ;
     RECT  2.16 21.735 84.24 22.005 ;
     RECT  2.16 22.275 84.24 22.545 ;
     RECT  2.16 22.815 84.24 23.085 ;
     RECT  2.16 23.355 84.24 23.625 ;
     RECT  2.16 23.895 84.24 24.165 ;
     RECT  2.16 24.435 84.24 24.705 ;
     RECT  2.16 24.975 84.24 25.245 ;
     RECT  2.16 25.515 84.24 25.785 ;
     RECT  2.16 26.055 84.24 26.325 ;
     RECT  2.16 26.595 84.24 26.865 ;
     RECT  2.16 27.135 84.24 27.405 ;
     RECT  2.16 27.675 84.24 27.945 ;
     RECT  2.16 28.215 84.24 28.485 ;
     RECT  2.16 28.755 84.24 29.025 ;
     RECT  2.16 29.295 84.24 29.565 ;
     RECT  2.16 29.835 84.24 30.105 ;
     RECT  2.16 30.375 84.24 30.645 ;
     RECT  2.16 30.915 84.24 31.185 ;
     RECT  2.16 31.455 84.24 31.725 ;
     RECT  2.16 31.995 84.24 32.265 ;
     RECT  2.16 32.535 84.24 32.805 ;
     RECT  2.16 33.075 84.24 33.345 ;
     RECT  2.16 33.615 84.24 33.885 ;
     RECT  2.16 34.155 84.24 34.425 ;
     RECT  2.16 34.695 84.24 34.965 ;
     RECT  2.16 35.235 84.24 35.505 ;
     RECT  2.16 35.775 84.24 36.045 ;
     RECT  2.16 36.315 84.24 36.585 ;
     RECT  2.16 36.855 84.24 37.125 ;
     RECT  2.16 37.395 84.24 37.665 ;
     RECT  2.16 37.935 84.24 38.205 ;
     RECT  2.16 38.475 84.24 38.745 ;
     RECT  2.16 39.015 84.24 39.285 ;
     RECT  2.16 39.555 84.24 39.825 ;
     RECT  2.16 40.095 84.24 40.365 ;
     RECT  2.16 40.635 84.24 40.905 ;
     RECT  2.16 41.175 84.24 41.445 ;
     RECT  2.16 41.715 84.24 41.985 ;
     RECT  2.16 42.255 84.24 42.525 ;
     RECT  2.16 42.795 84.24 43.065 ;
     RECT  2.16 43.335 84.24 43.605 ;
     RECT  2.16 43.875 84.24 44.145 ;
     RECT  2.16 44.415 84.24 44.685 ;
     RECT  2.16 44.955 84.24 45.225 ;
     RECT  2.16 45.495 84.24 45.765 ;
     RECT  2.16 46.035 84.24 46.305 ;
     RECT  2.16 46.575 84.24 46.845 ;
     RECT  2.16 47.115 84.24 47.385 ;
     RECT  2.16 47.655 84.24 47.925 ;
     RECT  2.16 48.195 84.24 48.465 ;
     RECT  2.16 48.735 84.24 49.005 ;
     RECT  2.16 49.275 84.24 49.545 ;
     RECT  2.16 49.815 84.24 50.085 ;
     RECT  2.16 50.355 84.24 50.625 ;
     RECT  2.16 50.895 84.24 51.165 ;
     RECT  2.16 51.435 84.24 51.705 ;
     RECT  2.16 51.975 84.24 52.245 ;
     RECT  2.16 52.515 84.24 52.785 ;
     RECT  2.16 53.055 84.24 53.325 ;
     RECT  2.16 53.595 84.24 53.865 ;
     RECT  2.16 54.135 84.24 54.405 ;
     RECT  2.16 54.675 84.24 54.945 ;
     RECT  2.16 55.215 84.24 55.485 ;
     RECT  2.16 55.755 84.24 56.025 ;
     RECT  2.16 56.295 84.24 56.565 ;
     RECT  2.16 56.835 84.24 57.105 ;
     RECT  2.16 57.375 84.24 57.645 ;
     RECT  2.16 57.915 84.24 58.185 ;
     RECT  2.16 58.455 84.24 58.725 ;
     RECT  2.16 58.995 84.24 59.265 ;
     RECT  2.16 59.535 84.24 59.805 ;
     RECT  2.16 60.075 84.24 60.345 ;
     RECT  2.16 60.615 84.24 60.885 ;
     RECT  2.16 61.155 84.24 61.425 ;
     RECT  2.16 61.695 84.24 61.965 ;
     RECT  2.16 62.235 84.24 62.505 ;
    LAYER M1 ;
     RECT  2.16 2.151 84.24 62.649 ;
    LAYER M2 ;
     RECT  0.103 10.368 2.16 10.386 ;
     RECT  0.103 12.528 2.16 12.546 ;
     RECT  0.103 14.994 2.16 15.012 ;
     RECT  0.535 16.416 2.16 16.434 ;
     RECT  0.103 20.628 2.16 20.646 ;
     RECT  0.103 21.636 2.16 21.654 ;
     RECT  0.103 22.626 2.16 22.644 ;
     RECT  0.103 23.598 2.16 23.616 ;
     RECT  0.103 36.018 2.16 36.036 ;
     RECT  0.103 43.776 2.16 43.794 ;
     RECT  0.103 45.81 2.16 45.828 ;
     RECT  0.103 52.596 2.16 52.614 ;
     RECT  2.083 53.568 2.16 53.586 ;
     RECT  0.103 55.926 2.16 55.944 ;
     RECT  0.535 57.546 2.16 57.564 ;
     RECT  2.16 2.151 84.24 62.649 ;
     RECT  84.24 21.24 84.875 24.93 ;
     RECT  84.24 4.77 84.911 7.11 ;
     RECT  84.24 10.98 84.911 11.97 ;
     RECT  84.24 12.798 84.911 15.48 ;
     RECT  84.24 20.43 84.911 20.448 ;
     RECT  84.875 21.402 84.911 24.93 ;
     RECT  84.24 25.83 84.911 28.98 ;
     RECT  84.24 30.078 84.911 31.986 ;
     RECT  84.24 32.85 84.911 36.54 ;
     RECT  84.24 40.95 84.911 42.516 ;
     RECT  84.24 46.008 84.911 50.418 ;
     RECT  84.24 51.21 84.911 51.228 ;
     RECT  84.24 52.02 84.911 53.01 ;
     RECT  84.24 53.91 84.911 54.9 ;
     RECT  84.24 55.8 84.911 57.636 ;
     RECT  84.24 58.428 84.911 59.22 ;
     RECT  84.24 37.332 84.947 38.97 ;
     RECT  84.24 43.848 84.947 44.91 ;
     RECT  84.911 50.4 84.947 50.418 ;
     RECT  84.24 2.538 85.379 3.636 ;
     RECT  84.911 5.238 85.379 7.11 ;
     RECT  84.911 11.718 85.379 11.97 ;
     RECT  84.911 30.078 85.379 31.176 ;
     RECT  84.911 33.588 85.379 36.54 ;
     RECT  84.911 46.008 85.379 49.536 ;
     RECT  85.379 2.538 85.487 2.556 ;
     RECT  85.379 3.618 85.487 3.636 ;
     RECT  85.379 5.472 85.487 7.11 ;
     RECT  84.24 7.938 85.487 10.08 ;
     RECT  85.379 11.952 85.487 11.97 ;
     RECT  84.911 12.798 85.487 13.05 ;
     RECT  84.911 13.842 85.487 15.48 ;
     RECT  84.24 16.578 85.487 18.72 ;
     RECT  84.24 19.512 85.487 19.53 ;
     RECT  84.911 21.402 85.487 22.5 ;
     RECT  84.911 23.598 85.487 24.93 ;
     RECT  84.911 26.568 85.487 28.98 ;
     RECT  85.379 30.078 85.487 30.636 ;
     RECT  85.379 33.588 85.487 34.146 ;
     RECT  85.379 34.902 85.487 36.54 ;
     RECT  84.947 37.332 85.487 37.89 ;
     RECT  84.947 38.952 85.487 38.97 ;
     RECT  84.911 41.382 85.487 42.516 ;
     RECT  84.947 43.848 85.487 43.866 ;
     RECT  84.947 44.892 85.487 44.91 ;
     RECT  85.379 46.008 85.487 47.88 ;
     RECT  85.379 48.978 85.487 49.536 ;
     RECT  84.911 52.452 85.487 53.01 ;
     RECT  84.911 54.882 85.487 54.9 ;
     RECT  84.911 55.962 85.487 55.98 ;
     RECT  84.911 58.698 85.487 59.22 ;
     RECT  85.487 14.184 85.523 14.202 ;
     RECT  85.487 15.264 85.523 15.282 ;
     RECT  85.487 18.504 85.523 18.522 ;
     RECT  84.24 39.834 85.523 39.852 ;
     RECT  85.487 47.862 86.315 47.88 ;
    LAYER M3 ;
     RECT  83.415 2.143 83.505 2.335 ;
     RECT  2.415 2.143 2.505 2.395 ;
     RECT  2.304 2.395 2.505 2.413 ;
     RECT  7.815 2.143 7.905 2.413 ;
     RECT  13.215 2.143 13.305 2.413 ;
     RECT  18.615 2.143 18.705 2.413 ;
     RECT  24.015 2.143 24.105 2.413 ;
     RECT  29.415 2.143 29.505 2.413 ;
     RECT  34.815 2.143 34.905 2.413 ;
     RECT  40.215 2.143 40.305 2.413 ;
     RECT  45.615 2.143 45.705 2.413 ;
     RECT  51.015 2.143 51.105 2.413 ;
     RECT  56.415 2.143 56.505 2.413 ;
     RECT  61.815 2.143 61.905 2.413 ;
     RECT  67.215 2.143 67.305 2.413 ;
     RECT  72.615 2.143 72.705 2.413 ;
     RECT  78.015 2.143 78.105 2.413 ;
     RECT  85.464 2.395 85.482 2.561 ;
     RECT  2.304 2.413 2.697 2.569 ;
     RECT  2.304 2.569 2.826 2.669 ;
     RECT  82.656 2.263 82.674 2.803 ;
     RECT  83.415 2.335 84.042 2.803 ;
     RECT  3.744 2.827 3.762 3.029 ;
     RECT  85.356 2.875 85.374 3.101 ;
     RECT  43.524 3.073 43.542 3.145 ;
     RECT  2.376 2.669 2.826 3.181 ;
     RECT  78.015 2.413 78.297 3.181 ;
     RECT  45.615 2.413 45.897 3.271 ;
     RECT  72.615 2.413 72.897 3.271 ;
     RECT  73.692 3.181 73.71 3.271 ;
     RECT  77.76 3.181 78.678 3.299 ;
     RECT  41.904 3.073 41.922 3.307 ;
     RECT  43.452 3.145 44.082 3.307 ;
     RECT  78.015 3.299 78.678 3.307 ;
     RECT  82.656 2.803 84.042 3.335 ;
     RECT  72.615 3.271 73.71 3.341 ;
     RECT  4.644 3.181 4.662 3.379 ;
     RECT  43.452 3.307 44.478 3.379 ;
     RECT  82.944 3.335 84.042 3.379 ;
     RECT  78.015 3.307 78.75 3.407 ;
     RECT  41.472 3.307 41.922 3.415 ;
     RECT  41.472 3.415 41.958 3.451 ;
     RECT  43.344 3.379 44.478 3.451 ;
     RECT  2.376 3.181 2.862 3.613 ;
     RECT  73.656 3.341 73.71 3.641 ;
     RECT  85.464 3.403 85.482 3.641 ;
     RECT  40.215 2.413 40.497 3.649 ;
     RECT  41.472 3.451 42.318 3.649 ;
     RECT  2.376 3.613 3.006 3.685 ;
     RECT  4.644 3.379 5.058 3.685 ;
     RECT  72.615 3.341 72.897 3.685 ;
     RECT  74.484 3.451 74.502 3.713 ;
     RECT  40.215 3.649 42.318 3.721 ;
     RECT  43.128 3.451 44.478 3.721 ;
     RECT  45.396 3.271 45.897 3.721 ;
     RECT  46.62 3.685 46.962 3.721 ;
     RECT  72.216 3.685 72.897 3.721 ;
     RECT  76.392 3.271 76.41 3.721 ;
     RECT  71.856 3.721 72.897 3.725 ;
     RECT  2.376 3.685 3.726 3.787 ;
     RECT  38.376 3.685 38.394 3.811 ;
     RECT  43.092 3.721 44.478 3.835 ;
     RECT  58.14 3.451 58.158 3.839 ;
     RECT  38.376 3.811 38.862 3.847 ;
     RECT  43.092 3.835 44.586 3.847 ;
     RECT  45.396 3.721 46.962 3.847 ;
     RECT  82.944 3.379 84.114 3.875 ;
     RECT  2.304 3.787 3.726 3.883 ;
     RECT  4.536 3.685 5.058 3.883 ;
     RECT  58.644 3.847 58.662 3.883 ;
     RECT  67.215 2.413 67.497 3.883 ;
     RECT  2.304 3.883 5.058 3.947 ;
     RECT  58.644 3.883 58.734 3.947 ;
     RECT  70.704 3.721 70.722 3.947 ;
     RECT  74.556 3.721 74.574 3.947 ;
     RECT  38.376 3.847 39.078 3.955 ;
     RECT  43.092 3.847 46.962 3.955 ;
     RECT  58.716 3.947 58.734 3.983 ;
     RECT  66.708 3.883 67.497 3.983 ;
     RECT  73.728 3.685 73.746 3.983 ;
     RECT  75.348 3.931 75.366 3.983 ;
     RECT  40.032 3.721 42.318 3.991 ;
     RECT  43.092 3.955 47.646 3.991 ;
     RECT  60.66 3.721 60.678 3.991 ;
     RECT  76.392 3.721 76.482 3.991 ;
     RECT  40.032 3.991 47.646 4.109 ;
     RECT  79.596 3.883 79.614 4.109 ;
     RECT  82.944 3.875 83.862 4.117 ;
     RECT  54.828 3.919 54.846 4.145 ;
     RECT  60.66 3.991 60.822 4.145 ;
     RECT  76.32 3.991 76.482 4.145 ;
     RECT  2.415 3.947 5.058 4.153 ;
     RECT  5.832 3.955 5.85 4.153 ;
     RECT  6.84 3.991 6.858 4.153 ;
     RECT  40.032 4.109 42.354 4.189 ;
     RECT  2.415 4.153 5.85 4.217 ;
     RECT  82.62 4.117 83.862 4.217 ;
     RECT  6.84 4.153 6.93 4.253 ;
     RECT  78.015 3.407 78.297 4.261 ;
     RECT  2.415 4.217 5.274 4.289 ;
     RECT  82.944 4.217 83.862 4.289 ;
     RECT  2.415 4.289 4.086 4.379 ;
     RECT  4.86 4.289 5.274 4.379 ;
     RECT  52.344 4.261 52.362 4.379 ;
     RECT  38.34 3.955 39.078 4.387 ;
     RECT  61.815 2.413 62.097 4.387 ;
     RECT  76.392 4.145 76.482 4.387 ;
     RECT  84.888 3.883 84.906 4.411 ;
     RECT  45.396 4.109 47.646 4.415 ;
     RECT  49.824 4.261 49.842 4.415 ;
     RECT  78.015 4.261 78.678 4.487 ;
     RECT  38.34 4.387 39.114 4.495 ;
     RECT  39.852 4.189 42.354 4.495 ;
     RECT  71.856 3.725 71.874 4.495 ;
     RECT  51.015 2.413 51.297 4.507 ;
     RECT  51.015 4.507 51.426 4.531 ;
     RECT  71.244 4.495 71.874 4.531 ;
     RECT  72.615 3.725 72.897 4.531 ;
     RECT  4.86 4.379 5.166 4.541 ;
     RECT  5.148 4.541 5.166 4.649 ;
     RECT  51.015 4.531 51.57 4.649 ;
     RECT  71.244 4.531 72.897 4.649 ;
     RECT  76.392 4.387 76.986 4.649 ;
     RECT  61.2 4.387 62.097 4.685 ;
     RECT  71.892 4.649 72.897 4.685 ;
     RECT  2.415 4.379 2.697 4.699 ;
     RECT  34.815 2.413 35.097 4.729 ;
     RECT  6.84 4.253 6.858 4.829 ;
     RECT  34.776 4.729 35.097 4.829 ;
     RECT  72.288 4.685 72.897 4.829 ;
     RECT  84.852 4.411 84.906 4.829 ;
     RECT  38.34 4.495 42.354 4.919 ;
     RECT  3.528 4.379 4.086 4.955 ;
     RECT  72.396 4.829 72.897 4.955 ;
     RECT  81.972 4.531 81.99 4.987 ;
     RECT  43.092 4.109 44.55 4.999 ;
     RECT  45.396 4.415 47.574 4.999 ;
     RECT  83.415 4.289 83.862 5.035 ;
     RECT  2.304 4.699 2.697 5.099 ;
     RECT  6.048 4.531 6.066 5.161 ;
     RECT  58.068 4.927 58.086 5.225 ;
     RECT  43.092 4.999 47.574 5.233 ;
     RECT  85.356 4.891 85.374 5.261 ;
     RECT  42.804 5.233 47.574 5.269 ;
     RECT  81.972 4.987 82.206 5.269 ;
     RECT  81.9 5.269 82.602 5.305 ;
     RECT  83.415 5.035 84.042 5.305 ;
     RECT  5.508 5.161 6.066 5.341 ;
     RECT  38.34 4.919 41.922 5.419 ;
     RECT  3.528 4.955 4.014 5.459 ;
     RECT  38.232 5.419 41.922 5.459 ;
     RECT  70.38 5.461 70.398 5.467 ;
     RECT  70.38 5.467 71.118 5.501 ;
     RECT  2.415 5.099 2.697 5.515 ;
     RECT  5.508 5.341 6.606 5.575 ;
     RECT  42.804 5.269 48.078 5.575 ;
     RECT  81.576 5.305 84.042 5.603 ;
     RECT  42.804 5.575 48.114 5.611 ;
     RECT  0.108 5.515 0.126 5.645 ;
     RECT  49.032 5.611 49.05 5.701 ;
     RECT  59.004 5.467 59.022 5.701 ;
     RECT  67.215 3.983 67.497 5.701 ;
     RECT  5.292 5.575 6.606 5.729 ;
     RECT  69.552 5.611 69.57 5.729 ;
     RECT  70.668 5.501 71.118 5.729 ;
     RECT  76.392 5.707 76.41 5.765 ;
     RECT  49.032 5.701 49.122 5.801 ;
     RECT  38.376 5.459 41.922 5.809 ;
     RECT  42.804 5.611 48.258 5.809 ;
     RECT  51.015 4.649 51.297 5.809 ;
     RECT  78.015 4.487 78.297 5.809 ;
     RECT  49.104 5.801 49.122 5.837 ;
     RECT  58.716 5.701 59.202 5.837 ;
     RECT  81.576 5.603 82.278 5.881 ;
     RECT  5.292 5.729 5.67 5.885 ;
     RECT  38.376 5.809 48.258 5.909 ;
     RECT  37.044 5.881 37.062 5.999 ;
     RECT  50.724 5.809 51.297 5.999 ;
     RECT  54.972 5.881 54.99 5.999 ;
     RECT  67.215 5.701 67.95 5.999 ;
     RECT  34.815 4.829 35.097 6.007 ;
     RECT  70.884 5.729 71.118 6.035 ;
     RECT  78.015 5.809 78.678 6.071 ;
     RECT  61.815 4.685 62.097 6.091 ;
     RECT  6.804 5.881 6.822 6.107 ;
     RECT  81.288 5.881 82.278 6.107 ;
     RECT  83.052 5.603 84.042 6.143 ;
     RECT  61.815 6.091 62.226 6.151 ;
     RECT  34.776 6.007 35.097 6.179 ;
     RECT  2.415 5.515 3.33 6.187 ;
     RECT  53.928 5.737 53.946 6.269 ;
     RECT  61.815 6.151 62.37 6.269 ;
     RECT  38.376 5.909 47.358 6.277 ;
     RECT  72.615 4.955 72.897 6.283 ;
     RECT  4.212 5.845 4.554 6.385 ;
     RECT  5.292 5.885 5.454 6.385 ;
     RECT  81.828 6.107 82.278 6.511 ;
     RECT  2.415 6.187 3.366 6.539 ;
     RECT  4.212 6.385 5.454 6.539 ;
     RECT  72.615 6.283 73.458 6.539 ;
     RECT  78.015 6.071 78.297 6.547 ;
     RECT  2.415 6.539 2.697 6.571 ;
     RECT  48.312 6.283 48.33 6.583 ;
     RECT  5.436 6.539 5.454 6.611 ;
     RECT  81.828 6.511 82.674 6.611 ;
     RECT  4.212 6.539 4.698 6.619 ;
     RECT  81.972 6.611 82.674 6.647 ;
     RECT  74.268 6.421 74.286 6.691 ;
     RECT  60.84 6.511 60.858 6.809 ;
     RECT  74.268 6.691 74.394 6.817 ;
     RECT  49.248 6.691 49.266 6.845 ;
     RECT  70.704 6.511 70.722 6.845 ;
     RECT  48.312 6.583 48.402 6.859 ;
     RECT  48.312 6.859 49.05 6.893 ;
     RECT  38.16 6.277 47.358 6.925 ;
     RECT  74.268 6.817 74.574 7.051 ;
     RECT  72.615 6.539 72.99 7.079 ;
     RECT  38.088 6.925 47.898 7.087 ;
     RECT  85.464 5.371 85.482 7.115 ;
     RECT  77.904 6.547 78.297 7.195 ;
     RECT  83.415 6.143 84.042 7.195 ;
     RECT  73.764 7.051 74.574 7.223 ;
     RECT  77.58 7.195 78.297 7.231 ;
     RECT  3.636 6.619 4.698 7.321 ;
     RECT  49.968 7.231 49.986 7.349 ;
     RECT  61.815 6.269 62.097 7.357 ;
     RECT  48.96 6.893 49.05 7.373 ;
     RECT  83.16 7.195 84.042 7.385 ;
     RECT  76.176 7.321 76.194 7.387 ;
     RECT  77.58 7.231 78.534 7.421 ;
     RECT  81.972 6.647 81.99 7.421 ;
     RECT  75.924 7.387 76.194 7.429 ;
     RECT  2.304 6.571 2.697 7.435 ;
     RECT  3.636 7.321 4.842 7.435 ;
     RECT  5.868 7.435 5.886 7.465 ;
     RECT  54.072 7.429 54.09 7.465 ;
     RECT  2.304 7.435 4.842 7.469 ;
     RECT  5.868 7.465 6.03 7.483 ;
     RECT  37.764 7.087 47.898 7.501 ;
     RECT  61.815 7.357 62.622 7.501 ;
     RECT  74.556 7.223 74.574 7.501 ;
     RECT  78.015 7.421 78.534 7.501 ;
     RECT  48.96 7.373 48.978 7.529 ;
     RECT  5.256 7.483 6.03 7.591 ;
     RECT  70.74 7.429 70.758 7.591 ;
     RECT  80.028 7.051 80.046 7.591 ;
     RECT  5.256 7.591 6.246 7.619 ;
     RECT  37.044 7.501 47.898 7.619 ;
     RECT  53.928 7.465 54.09 7.619 ;
     RECT  78.015 7.501 78.642 7.627 ;
     RECT  79.416 7.591 80.046 7.627 ;
     RECT  83.16 7.385 83.898 7.627 ;
     RECT  49.86 7.621 49.878 7.661 ;
     RECT  75.672 7.429 76.194 7.661 ;
     RECT  74.556 7.501 74.718 7.664 ;
     RECT  53.928 7.619 53.946 7.691 ;
     RECT  58.716 7.627 58.734 7.763 ;
     RECT  51.015 5.999 51.297 7.771 ;
     RECT  67.215 5.999 67.497 7.771 ;
     RECT  82.944 7.627 83.898 7.771 ;
     RECT  53.136 7.765 53.154 7.805 ;
     RECT  66.672 7.771 67.497 7.861 ;
     RECT  48.672 7.735 48.69 7.889 ;
     RECT  61.815 7.501 63.342 7.889 ;
     RECT  70.704 7.591 70.758 7.889 ;
     RECT  72.615 7.079 72.954 7.889 ;
     RECT  74.808 7.771 75.582 7.889 ;
     RECT  82.62 7.771 83.898 7.889 ;
     RECT  84.888 7.387 84.906 7.915 ;
     RECT  5.652 7.619 6.246 7.925 ;
     RECT  74.808 7.889 74.898 7.925 ;
     RECT  76.536 7.771 76.554 7.925 ;
     RECT  5.652 7.925 5.67 7.961 ;
     RECT  50.832 7.771 51.297 7.961 ;
     RECT  63.108 7.889 63.126 7.961 ;
     RECT  66.6 7.861 67.497 7.961 ;
     RECT  70.74 7.889 70.758 7.961 ;
     RECT  61.815 7.889 62.334 7.963 ;
     RECT  78.015 7.627 80.046 8.005 ;
     RECT  74.808 7.925 74.826 8.069 ;
     RECT  82.62 7.889 82.674 8.167 ;
     RECT  83.415 7.889 83.898 8.195 ;
     RECT  83.415 8.195 83.826 8.267 ;
     RECT  34.815 6.179 35.097 8.311 ;
     RECT  78.015 8.005 80.154 8.311 ;
     RECT  2.304 7.469 4.158 8.339 ;
     RECT  61.38 7.963 62.334 8.339 ;
     RECT  2.415 8.339 4.158 8.401 ;
     RECT  37.764 7.619 47.754 8.429 ;
     RECT  70.992 8.131 71.01 8.429 ;
     RECT  82.188 8.167 82.674 8.429 ;
     RECT  37.764 8.429 41.058 8.477 ;
     RECT  2.415 8.401 5.166 8.537 ;
     RECT  6.84 8.437 6.858 8.537 ;
     RECT  34.776 8.311 35.097 8.537 ;
     RECT  82.656 8.429 82.674 8.537 ;
     RECT  37.764 8.477 40.698 8.539 ;
     RECT  41.904 8.429 47.754 8.573 ;
     RECT  37.476 8.539 40.698 8.699 ;
     RECT  78.015 8.311 80.622 8.699 ;
     RECT  54.36 8.671 54.378 8.717 ;
     RECT  56.415 2.413 56.697 8.731 ;
     RECT  84.888 7.915 85.482 8.735 ;
     RECT  58.14 8.707 58.158 8.765 ;
     RECT  61.38 8.339 62.097 8.765 ;
     RECT  55.908 8.731 56.697 8.771 ;
     RECT  4.86 8.537 5.166 8.815 ;
     RECT  79.776 8.699 80.622 8.843 ;
     RECT  69.984 8.671 70.002 8.851 ;
     RECT  81.396 8.743 81.414 8.851 ;
     RECT  81.396 8.851 81.882 8.941 ;
     RECT  69.84 8.851 70.002 8.969 ;
     RECT  44.136 8.573 47.754 8.977 ;
     RECT  83.415 8.267 83.754 8.977 ;
     RECT  0.108 8.395 0.126 9.005 ;
     RECT  2.415 8.537 4.05 9.005 ;
     RECT  44.136 8.977 47.79 9.005 ;
     RECT  69.84 8.969 69.858 9.005 ;
     RECT  37.8 8.699 40.698 9.077 ;
     RECT  41.94 8.573 43.398 9.077 ;
     RECT  44.28 9.005 47.79 9.077 ;
     RECT  55.116 8.635 55.134 9.077 ;
     RECT  49.968 9.067 49.986 9.085 ;
     RECT  3.924 9.005 4.05 9.113 ;
     RECT  4.86 8.815 5.274 9.113 ;
     RECT  49.968 9.085 50.058 9.113 ;
     RECT  79.776 8.843 80.19 9.113 ;
     RECT  50.04 9.113 50.058 9.121 ;
     RECT  83.196 8.977 83.754 9.121 ;
     RECT  44.532 9.077 47.574 9.149 ;
     RECT  81.144 8.941 81.882 9.211 ;
     RECT  2.415 9.005 3.006 9.239 ;
     RECT  5.112 9.113 5.274 9.239 ;
     RECT  37.8 9.077 37.818 9.239 ;
     RECT  44.532 9.149 47.502 9.239 ;
     RECT  50.04 9.121 50.166 9.239 ;
     RECT  65.736 9.049 65.754 9.275 ;
     RECT  81.144 9.211 82.134 9.275 ;
     RECT  38.628 9.077 40.698 9.311 ;
     RECT  38.772 9.311 40.698 9.319 ;
     RECT  38.772 9.319 41.058 9.355 ;
     RECT  41.94 9.077 43.254 9.355 ;
     RECT  83.196 9.121 83.898 9.355 ;
     RECT  38.772 9.355 43.254 9.383 ;
     RECT  50.04 9.239 50.058 9.383 ;
     RECT  3.996 9.113 4.05 9.391 ;
     RECT  5.148 9.239 5.274 9.391 ;
     RECT  81.216 9.275 82.134 9.391 ;
     RECT  82.872 9.355 83.898 9.391 ;
     RECT  39.348 9.383 43.254 9.419 ;
     RECT  5.148 9.391 5.454 9.509 ;
     RECT  81.216 9.391 83.898 9.545 ;
     RECT  44.532 9.239 47.358 9.581 ;
     RECT  82.872 9.545 83.898 9.617 ;
     RECT  3.996 9.391 4.338 9.677 ;
     RECT  5.148 9.509 5.31 9.689 ;
     RECT  39.348 9.419 41.058 9.689 ;
     RECT  79.776 9.113 79.794 9.751 ;
     RECT  5.148 9.689 5.166 9.779 ;
     RECT  44.532 9.581 47.25 9.779 ;
     RECT  75.06 9.739 75.078 9.779 ;
     RECT  81.216 9.545 81.99 9.779 ;
     RECT  2.415 9.239 2.697 9.787 ;
     RECT  78.015 8.699 78.678 9.787 ;
     RECT  44.532 9.779 47.178 9.815 ;
     RECT  79.632 9.751 79.794 9.821 ;
     RECT  6.228 9.661 6.246 9.851 ;
     RECT  41.976 9.419 43.254 9.859 ;
     RECT  41.976 9.859 43.398 10.049 ;
     RECT  44.64 9.815 47.178 10.049 ;
     RECT  60.084 9.823 60.102 10.049 ;
     RECT  74.7 9.931 74.718 10.049 ;
     RECT  78.015 9.787 78.75 10.049 ;
     RECT  83.16 9.617 83.898 10.049 ;
     RECT  44.748 10.049 47.178 10.085 ;
     RECT  70.704 9.859 70.722 10.085 ;
     RECT  85.464 8.735 85.482 10.085 ;
     RECT  39.348 9.689 40.914 10.121 ;
     RECT  75.996 9.931 76.014 10.121 ;
     RECT  81.972 9.779 81.99 10.157 ;
     RECT  79.776 9.821 79.794 10.205 ;
     RECT  3.888 10.129 3.906 10.319 ;
     RECT  41.976 10.049 43.254 10.319 ;
     RECT  83.232 10.049 83.898 10.355 ;
     RECT  0.108 10.267 0.126 10.391 ;
     RECT  41.976 10.319 43.146 10.459 ;
     RECT  4.968 10.363 4.986 10.471 ;
     RECT  48.888 10.291 48.906 10.471 ;
     RECT  54.072 10.435 54.09 10.471 ;
     RECT  54.072 10.471 54.234 10.597 ;
     RECT  39.42 10.121 40.914 10.651 ;
     RECT  2.304 9.787 2.697 10.669 ;
     RECT  53.388 10.597 54.234 10.669 ;
     RECT  53.316 10.669 54.486 10.705 ;
     RECT  53.316 10.705 54.63 10.741 ;
     RECT  3.924 10.471 4.986 10.769 ;
     RECT  5.904 10.669 5.922 10.769 ;
     RECT  44.748 10.085 47.106 10.769 ;
     RECT  2.304 10.669 2.898 10.781 ;
     RECT  6.66 10.561 6.678 10.831 ;
     RECT  51.015 7.961 51.297 10.831 ;
     RECT  3.924 10.769 4.878 10.859 ;
     RECT  6.264 10.831 6.678 10.877 ;
     RECT  84.888 10.411 84.906 10.891 ;
     RECT  47.988 10.471 48.906 10.903 ;
     RECT  49.932 10.831 49.95 10.903 ;
     RECT  50.832 10.831 51.642 10.903 ;
     RECT  49.932 10.903 51.642 10.975 ;
     RECT  83.232 10.355 83.862 10.975 ;
     RECT  4.86 10.859 4.878 11.003 ;
     RECT  6.408 10.877 6.678 11.011 ;
     RECT  7.815 2.413 8.097 11.011 ;
     RECT  49.932 10.975 51.894 11.011 ;
     RECT  61.815 8.765 62.097 11.011 ;
     RECT  63.936 10.867 63.954 11.011 ;
     RECT  67.215 7.961 67.497 11.011 ;
     RECT  74.664 10.939 74.682 11.011 ;
     RECT  75.888 10.843 75.906 11.011 ;
     RECT  78.015 10.049 78.297 11.011 ;
     RECT  74.664 11.011 76.086 11.039 ;
     RECT  47.988 10.903 49.122 11.083 ;
     RECT  49.932 11.011 52.434 11.083 ;
     RECT  61.452 11.011 62.73 11.101 ;
     RECT  78.015 11.011 78.462 11.101 ;
     RECT  61.308 11.101 62.73 11.129 ;
     RECT  63.936 11.011 64.026 11.129 ;
     RECT  75.348 11.039 76.086 11.129 ;
     RECT  45.036 10.769 47.106 11.131 ;
     RECT  47.988 11.083 52.434 11.131 ;
     RECT  39.42 10.651 40.986 11.137 ;
     RECT  41.832 10.459 43.146 11.137 ;
     RECT  82.692 10.975 83.862 11.137 ;
     RECT  82.62 11.137 83.862 11.165 ;
     RECT  2.415 10.781 2.898 11.179 ;
     RECT  66.672 11.011 67.497 11.201 ;
     RECT  76.86 11.011 76.878 11.201 ;
     RECT  72.615 7.889 72.897 11.209 ;
     RECT  78.015 11.101 78.57 11.237 ;
     RECT  39.42 11.137 43.146 11.281 ;
     RECT  53.316 10.741 54.702 11.281 ;
     RECT  72.615 11.209 74.106 11.281 ;
     RECT  6.408 11.011 8.097 11.309 ;
     RECT  76.068 11.129 76.086 11.309 ;
     RECT  81.216 9.779 81.234 11.371 ;
     RECT  82.62 11.165 82.638 11.371 ;
     RECT  84.852 10.891 84.906 11.371 ;
     RECT  70.704 11.209 70.722 11.399 ;
     RECT  72.54 11.281 74.106 11.399 ;
     RECT  72.615 11.399 73.242 11.405 ;
     RECT  61.308 11.129 62.097 11.435 ;
     RECT  39.348 11.281 43.146 11.443 ;
     RECT  39.348 11.443 43.362 11.471 ;
     RECT  84.852 11.371 85.374 11.471 ;
     RECT  83.412 11.165 83.862 11.515 ;
     RECT  74.088 11.399 74.106 11.543 ;
     RECT  45.036 11.131 52.434 11.551 ;
     RECT  53.316 11.281 54.81 11.551 ;
     RECT  64.08 11.371 64.098 11.551 ;
     RECT  81.216 11.371 82.638 11.551 ;
     RECT  45.036 11.551 54.882 11.597 ;
     RECT  2.415 11.179 3.87 11.659 ;
     RECT  64.08 11.551 64.206 11.669 ;
     RECT  80.964 11.551 82.638 11.669 ;
     RECT  83.412 11.515 84.042 11.669 ;
     RECT  64.08 11.669 64.098 11.705 ;
     RECT  81.396 11.669 82.638 11.741 ;
     RECT  85.356 11.471 85.374 11.741 ;
     RECT  82.152 11.741 82.638 11.813 ;
     RECT  83.412 11.669 84.006 11.813 ;
     RECT  5.976 11.785 5.994 11.821 ;
     RECT  5.184 11.821 5.994 11.938 ;
     RECT  82.152 11.813 82.386 11.939 ;
     RECT  2.415 11.659 4.23 11.947 ;
     RECT  5.148 11.938 5.994 11.947 ;
     RECT  83.412 11.813 83.898 11.947 ;
     RECT  2.415 11.947 5.994 11.975 ;
     RECT  45.036 11.597 54.63 11.975 ;
     RECT  2.415 11.975 5.742 11.981 ;
     RECT  2.415 11.981 5.598 12.209 ;
     RECT  67.215 11.201 67.497 12.289 ;
     RECT  78.015 11.237 78.297 12.289 ;
     RECT  50.22 11.975 54.63 12.317 ;
     RECT  83.16 11.947 83.898 12.317 ;
     RECT  39.492 11.471 43.362 12.325 ;
     RECT  55.548 12.289 55.566 12.325 ;
     RECT  56.415 8.771 56.697 12.325 ;
     RECT  6.84 11.309 6.858 12.353 ;
     RECT  38.772 12.325 43.362 12.353 ;
     RECT  45.036 11.975 49.374 12.361 ;
     RECT  55.548 12.325 56.697 12.361 ;
     RECT  63.216 12.289 63.234 12.361 ;
     RECT  74.736 12.181 74.754 12.361 ;
     RECT  82.152 11.939 82.35 12.365 ;
     RECT  5.508 12.209 5.598 12.479 ;
     RECT  55.548 12.361 56.79 12.479 ;
     RECT  63.216 12.361 63.342 12.479 ;
     RECT  65.484 12.181 65.502 12.479 ;
     RECT  81.396 11.741 81.414 12.479 ;
     RECT  44.64 12.361 49.374 12.515 ;
     RECT  66.6 12.289 67.497 12.515 ;
     RECT  82.26 12.365 82.35 12.515 ;
     RECT  44.64 12.515 46.782 12.523 ;
     RECT  50.256 12.317 54.63 12.523 ;
     RECT  55.548 12.479 56.718 12.523 ;
     RECT  38.772 12.353 38.79 12.551 ;
     RECT  50.256 12.523 56.718 12.551 ;
     RECT  66.672 12.515 67.497 12.551 ;
     RECT  50.292 12.551 56.697 12.557 ;
     RECT  2.415 12.209 4.662 12.571 ;
     RECT  83.232 12.317 83.898 12.595 ;
     RECT  44.496 12.523 46.782 12.605 ;
     RECT  58.212 12.523 58.23 12.631 ;
     RECT  74.736 12.361 74.898 12.631 ;
     RECT  78.015 12.289 78.678 12.631 ;
     RECT  74.664 12.631 74.898 12.715 ;
     RECT  77.76 12.631 78.678 12.715 ;
     RECT  73.944 12.715 74.898 12.721 ;
     RECT  83.232 12.595 84.042 12.749 ;
     RECT  73.944 12.721 74.97 12.785 ;
     RECT  74.664 12.785 74.97 12.821 ;
     RECT  72.615 11.405 72.897 12.859 ;
     RECT  40.032 12.353 43.362 12.901 ;
     RECT  58.212 12.631 58.374 12.901 ;
     RECT  67.215 12.551 67.497 12.901 ;
     RECT  68.256 12.631 68.274 12.901 ;
     RECT  77.76 12.715 78.75 12.901 ;
     RECT  80.712 12.721 80.73 12.901 ;
     RECT  2.304 12.571 4.662 12.929 ;
     RECT  45.036 12.605 46.782 12.929 ;
     RECT  58.212 12.901 59.166 12.929 ;
     RECT  74.664 12.821 74.934 12.929 ;
     RECT  72.288 12.859 72.897 12.991 ;
     RECT  77.76 12.901 79.218 12.991 ;
     RECT  67.215 12.901 68.274 13.019 ;
     RECT  77.652 12.991 79.218 13.019 ;
     RECT  63.216 12.479 63.27 13.027 ;
     RECT  67.215 13.019 68.13 13.055 ;
     RECT  74.772 12.929 74.934 13.055 ;
     RECT  79.128 13.019 79.218 13.055 ;
     RECT  80.604 12.901 80.73 13.055 ;
     RECT  85.464 11.899 85.482 13.055 ;
     RECT  2.415 12.929 4.662 13.063 ;
     RECT  47.592 12.515 49.374 13.171 ;
     RECT  72.036 12.991 72.897 13.171 ;
     RECT  70.632 13.063 70.65 13.199 ;
     RECT  79.128 13.055 79.146 13.199 ;
     RECT  40.032 12.901 43.614 13.261 ;
     RECT  82.368 12.901 82.386 13.261 ;
     RECT  83.232 12.749 83.898 13.261 ;
     RECT  63.072 13.027 63.27 13.289 ;
     RECT  74.772 13.055 74.898 13.289 ;
     RECT  77.652 13.019 78.297 13.289 ;
     RECT  74.772 13.289 74.79 13.325 ;
     RECT  82.08 13.261 83.898 13.325 ;
     RECT  63.252 13.289 63.27 13.361 ;
     RECT  82.08 13.325 83.826 13.361 ;
     RECT  72.036 13.171 73.242 13.433 ;
     RECT  58.464 12.929 59.166 13.441 ;
     RECT  40.032 13.261 43.758 13.469 ;
     RECT  50.292 12.557 55.098 13.469 ;
     RECT  84.888 13.387 84.906 13.469 ;
     RECT  40.032 13.469 43.65 13.531 ;
     RECT  39.924 13.531 43.65 13.559 ;
     RECT  58.464 13.441 59.418 13.559 ;
     RECT  0.108 12.043 0.126 13.565 ;
     RECT  58.464 13.559 58.698 13.595 ;
     RECT  72.036 13.433 72.99 13.603 ;
     RECT  6.768 13.405 6.786 13.631 ;
     RECT  55.836 12.557 56.697 13.631 ;
     RECT  47.592 13.171 49.518 13.639 ;
     RECT  50.292 13.469 52.614 13.639 ;
     RECT  72 13.603 72.99 13.639 ;
     RECT  39.924 13.559 43.218 13.675 ;
     RECT  65.088 13.531 65.106 13.711 ;
     RECT  45.036 12.929 46.71 13.771 ;
     RECT  56.415 13.631 56.697 13.819 ;
     RECT  67.215 13.055 67.497 13.819 ;
     RECT  39.456 13.675 43.218 13.829 ;
     RECT  65.088 13.711 65.25 13.829 ;
     RECT  71.82 13.639 72.99 13.829 ;
     RECT  77.22 13.531 77.238 13.829 ;
     RECT  65.088 13.829 65.106 13.865 ;
     RECT  39.456 13.829 42.786 13.901 ;
     RECT  85.464 13.837 85.482 13.901 ;
     RECT  56.415 13.819 56.862 13.915 ;
     RECT  2.415 13.063 5.094 13.963 ;
     RECT  58.644 13.595 58.698 13.973 ;
     RECT  72.36 13.829 72.99 13.973 ;
     RECT  39.456 13.901 40.986 13.981 ;
     RECT  44.82 13.771 46.71 13.981 ;
     RECT  47.592 13.639 52.614 13.981 ;
     RECT  2.304 13.963 5.094 14.009 ;
     RECT  41.796 13.901 42.786 14.009 ;
     RECT  56.415 13.915 56.97 14.009 ;
     RECT  2.376 14.009 5.094 14.099 ;
     RECT  38.772 13.981 40.986 14.099 ;
     RECT  66.096 13.675 66.114 14.099 ;
     RECT  67.032 13.819 67.497 14.099 ;
     RECT  69.192 13.867 69.21 14.099 ;
     RECT  68.256 14.071 68.274 14.141 ;
     RECT  82.548 13.361 83.826 14.143 ;
     RECT  6.804 13.981 6.822 14.171 ;
     RECT  58.644 13.973 58.662 14.189 ;
     RECT  82.404 14.143 83.826 14.215 ;
     RECT  38.772 14.099 40.914 14.243 ;
     RECT  44.82 13.981 52.614 14.251 ;
     RECT  53.604 13.469 55.026 14.251 ;
     RECT  74.016 14.071 74.034 14.251 ;
     RECT  80.964 13.639 80.982 14.251 ;
     RECT  81.756 14.215 83.826 14.251 ;
     RECT  66.24 14.251 66.258 14.369 ;
     RECT  74.016 14.251 74.574 14.369 ;
     RECT  81.756 14.251 83.898 14.369 ;
     RECT  44.82 14.251 55.026 14.377 ;
     RECT  82.404 14.369 83.898 14.377 ;
     RECT  74.016 14.369 74.034 14.405 ;
     RECT  39.456 14.243 40.914 14.429 ;
     RECT  85.5 14.179 85.518 14.429 ;
     RECT  44.82 14.377 55.134 14.485 ;
     RECT  82.404 14.377 84.042 14.513 ;
     RECT  44.568 14.485 55.134 14.521 ;
     RECT  80.676 14.251 80.982 14.521 ;
     RECT  39.924 14.429 40.914 14.639 ;
     RECT  43.848 14.521 55.134 14.639 ;
     RECT  80.316 14.521 81.306 14.639 ;
     RECT  83.415 14.513 84.042 14.639 ;
     RECT  80.856 14.639 81.306 14.675 ;
     RECT  41.832 14.009 42.786 14.719 ;
     RECT  80.856 14.675 81.018 14.909 ;
     RECT  82.404 14.513 82.422 14.909 ;
     RECT  2.415 14.099 2.934 14.923 ;
     RECT  80.856 14.909 80.874 14.945 ;
     RECT  2.304 14.923 2.934 14.953 ;
     RECT  3.852 14.099 4.554 14.953 ;
     RECT  39.996 14.639 40.914 14.989 ;
     RECT  2.304 14.953 4.554 15.025 ;
     RECT  6.156 14.989 6.174 15.025 ;
     RECT  39.996 14.989 41.094 15.025 ;
     RECT  41.832 14.719 43.506 15.025 ;
     RECT  6.156 15.025 6.93 15.061 ;
     RECT  2.304 15.025 4.662 15.089 ;
     RECT  38.808 14.989 38.826 15.089 ;
     RECT  6.012 15.061 6.93 15.215 ;
     RECT  76.356 15.187 76.374 15.223 ;
     RECT  85.464 14.875 85.482 15.259 ;
     RECT  6.3 15.215 6.93 15.287 ;
     RECT  83.415 14.639 84.006 15.295 ;
     RECT  57.6 15.295 57.618 15.331 ;
     RECT  57.6 15.331 58.122 15.341 ;
     RECT  39.996 15.025 43.506 15.359 ;
     RECT  44.244 14.639 55.134 15.359 ;
     RECT  0.108 14.443 0.126 15.389 ;
     RECT  40.215 15.359 43.506 15.421 ;
     RECT  44.244 15.359 54.702 15.421 ;
     RECT  57.744 15.341 58.122 15.421 ;
     RECT  72.615 13.973 72.897 15.421 ;
     RECT  6.3 15.287 6.858 15.449 ;
     RECT  75.852 15.223 76.374 15.449 ;
     RECT  66.24 15.187 66.258 15.485 ;
     RECT  85.464 15.259 85.518 15.485 ;
     RECT  57.744 15.421 58.806 15.521 ;
     RECT  56.415 14.009 56.697 15.547 ;
     RECT  72.615 15.421 73.062 15.565 ;
     RECT  76.356 15.449 76.374 15.593 ;
     RECT  79.776 15.331 79.794 15.593 ;
     RECT  55.548 15.565 55.566 15.601 ;
     RECT  56.34 15.547 56.697 15.601 ;
     RECT  83.376 15.295 84.006 15.601 ;
     RECT  67.215 14.099 67.497 15.691 ;
     RECT  70.704 15.529 70.722 15.691 ;
     RECT  40.215 15.421 54.702 15.719 ;
     RECT  55.548 15.601 56.697 15.719 ;
     RECT  64.908 15.601 64.926 15.719 ;
     RECT  72.615 15.565 73.494 15.719 ;
     RECT  6.3 15.449 6.822 15.725 ;
     RECT  61.815 11.435 62.097 15.727 ;
     RECT  83.376 15.601 84.042 15.727 ;
     RECT  44.424 15.719 47.538 15.755 ;
     RECT  55.656 15.719 56.697 15.791 ;
     RECT  66.744 15.691 67.497 15.791 ;
     RECT  44.496 15.755 47.538 15.827 ;
     RECT  57.78 15.521 58.77 15.827 ;
     RECT  61.815 15.727 62.694 15.827 ;
     RECT  64.98 15.727 64.998 15.827 ;
     RECT  58.104 15.827 58.122 15.863 ;
     RECT  2.415 15.089 4.662 15.871 ;
     RECT  55.8 15.791 56.697 15.871 ;
     RECT  44.712 15.827 47.538 15.899 ;
     RECT  70.704 15.691 70.758 15.899 ;
     RECT  74.628 15.763 74.646 15.899 ;
     RECT  85.5 15.485 85.518 15.917 ;
     RECT  45 15.899 47.538 15.989 ;
     RECT  83.232 15.727 84.042 15.989 ;
     RECT  2.415 15.871 4.734 16.025 ;
     RECT  81.504 15.871 81.522 16.133 ;
     RECT  2.415 16.025 4.266 16.259 ;
     RECT  2.415 16.259 4.158 16.295 ;
     RECT  48.348 15.719 54.702 16.303 ;
     RECT  6.768 15.725 6.822 16.367 ;
     RECT  55.8 15.871 56.754 16.411 ;
     RECT  6.804 16.367 6.822 16.439 ;
     RECT  45.615 15.989 47.538 16.459 ;
     RECT  48.348 16.303 54.81 16.459 ;
     RECT  78.015 13.289 78.297 16.501 ;
     RECT  45.615 16.459 54.81 16.529 ;
     RECT  55.8 16.411 56.79 16.529 ;
     RECT  82.656 16.303 82.674 16.565 ;
     RECT  40.215 15.719 43.578 16.609 ;
     RECT  53.604 16.529 54.81 16.609 ;
     RECT  66.06 16.375 66.078 16.645 ;
     RECT  76.968 15.763 76.986 16.645 ;
     RECT  67.215 15.791 67.497 16.681 ;
     RECT  72.615 15.719 73.458 16.681 ;
     RECT  76.032 16.375 76.05 16.681 ;
     RECT  76.824 16.645 76.986 16.681 ;
     RECT  53.604 16.609 54.918 16.709 ;
     RECT  0.54 16.411 0.558 16.781 ;
     RECT  61.056 16.681 61.074 16.795 ;
     RECT  2.415 16.295 4.014 16.799 ;
     RECT  53.604 16.709 54.558 16.799 ;
     RECT  60.876 16.795 61.074 16.799 ;
     RECT  66.06 16.645 66.222 16.799 ;
     RECT  76.032 16.681 77.022 16.807 ;
     RECT  45.615 16.529 52.866 16.829 ;
     RECT  2.415 16.799 2.97 16.835 ;
     RECT  45.615 16.829 52.47 16.835 ;
     RECT  53.604 16.799 54.486 16.835 ;
     RECT  60.876 16.799 60.894 16.835 ;
     RECT  66.06 16.799 66.078 16.835 ;
     RECT  80.928 16.501 80.946 16.871 ;
     RECT  78.015 16.501 78.678 16.879 ;
     RECT  83.415 15.989 84.042 16.879 ;
     RECT  74.772 16.555 74.79 16.951 ;
     RECT  75.78 16.807 77.022 16.951 ;
     RECT  58.716 16.879 58.734 16.979 ;
     RECT  70.704 15.899 70.722 16.979 ;
     RECT  74.664 16.951 77.022 16.979 ;
     RECT  3.708 16.799 4.014 17.041 ;
     RECT  2.415 16.835 2.862 17.069 ;
     RECT  3.708 17.041 4.554 17.069 ;
     RECT  40.215 16.609 43.614 17.069 ;
     RECT  67.215 16.681 67.554 17.069 ;
     RECT  74.664 16.979 75.33 17.069 ;
     RECT  76.392 16.979 77.022 17.069 ;
     RECT  78.015 16.879 78.75 17.069 ;
     RECT  3.708 17.069 3.726 17.105 ;
     RECT  55.8 16.529 56.697 17.105 ;
     RECT  72.615 16.681 73.566 17.105 ;
     RECT  74.772 17.069 75.33 17.105 ;
     RECT  82.944 16.879 84.042 17.105 ;
     RECT  74.772 17.105 74.826 17.117 ;
     RECT  76.824 17.069 77.022 17.117 ;
     RECT  53.676 16.835 54.486 17.141 ;
     RECT  74.808 17.117 74.826 17.141 ;
     RECT  2.415 17.069 2.826 17.227 ;
     RECT  42.732 17.069 43.614 17.347 ;
     RECT  40.215 17.069 41.454 17.375 ;
     RECT  45.615 16.835 52.11 17.375 ;
     RECT  53.748 17.141 54.486 17.375 ;
     RECT  45.615 17.375 51.966 17.455 ;
     RECT  4.5 17.069 4.554 17.483 ;
     RECT  55.476 17.221 55.494 17.519 ;
     RECT  45.108 17.455 51.966 17.549 ;
     RECT  63.72 17.221 63.738 17.609 ;
     RECT  53.784 17.375 54.486 17.645 ;
     RECT  76.968 17.117 77.022 17.645 ;
     RECT  40.215 17.375 41.094 17.725 ;
     RECT  78.015 17.069 78.297 17.761 ;
     RECT  42.732 17.347 44.334 17.879 ;
     RECT  77.436 17.761 78.297 17.879 ;
     RECT  79.2 17.581 79.83 17.915 ;
     RECT  45.108 17.549 47.502 17.951 ;
     RECT  77.94 17.879 78.297 17.951 ;
     RECT  2.304 17.227 2.826 17.959 ;
     RECT  79.2 17.915 79.218 17.987 ;
     RECT  54.072 17.645 54.486 17.995 ;
     RECT  42.732 17.879 44.046 18.023 ;
     RECT  6.408 17.959 6.426 18.031 ;
     RECT  2.304 17.959 3.402 18.059 ;
     RECT  39.816 17.725 41.094 18.139 ;
     RECT  42.732 18.023 43.614 18.149 ;
     RECT  54.072 17.995 54.522 18.157 ;
     RECT  39.672 18.139 41.094 18.185 ;
     RECT  48.24 17.549 51.966 18.185 ;
     RECT  40.176 18.185 41.094 18.193 ;
     RECT  48.456 18.185 51.966 18.193 ;
     RECT  42.732 18.149 43.578 18.221 ;
     RECT  2.415 18.059 3.402 18.265 ;
     RECT  48.456 18.193 52.074 18.265 ;
     RECT  5.4 18.031 5.418 18.301 ;
     RECT  6.228 18.031 6.426 18.301 ;
     RECT  43.56 18.221 43.578 18.419 ;
     RECT  4.5 17.483 4.518 18.427 ;
     RECT  5.4 18.301 6.426 18.427 ;
     RECT  42.732 18.221 42.75 18.455 ;
     RECT  2.415 18.265 3.546 18.499 ;
     RECT  4.5 18.427 6.426 18.499 ;
     RECT  85.464 16.411 85.482 18.499 ;
     RECT  2.415 18.499 6.426 18.571 ;
     RECT  40.176 18.193 41.814 18.599 ;
     RECT  2.415 18.571 6.858 18.605 ;
     RECT  6.228 18.605 6.858 18.689 ;
     RECT  59.4 18.571 59.418 18.697 ;
     RECT  6.3 18.689 6.858 18.725 ;
     RECT  0.108 18.619 0.126 18.749 ;
     RECT  2.415 18.605 5.49 18.797 ;
     RECT  54.072 18.157 54.774 18.805 ;
     RECT  45.615 17.951 47.502 18.841 ;
     RECT  69.12 18.769 69.138 18.841 ;
     RECT  70.092 18.661 70.11 18.841 ;
     RECT  48.456 18.265 52.614 18.859 ;
     RECT  85.464 18.499 85.518 18.941 ;
     RECT  2.415 18.797 5.346 18.959 ;
     RECT  59.256 18.697 59.418 18.959 ;
     RECT  69.12 18.841 70.11 18.959 ;
     RECT  45.615 18.841 47.538 18.967 ;
     RECT  48.456 18.859 52.794 18.967 ;
     RECT  59.256 18.959 59.274 18.995 ;
     RECT  75.744 18.661 75.762 18.995 ;
     RECT  53.856 18.805 54.774 19.039 ;
     RECT  83.232 17.105 84.042 19.067 ;
     RECT  57.996 19.003 58.014 19.075 ;
     RECT  53.856 19.039 55.242 19.201 ;
     RECT  56.415 17.105 56.697 19.201 ;
     RECT  3.816 18.959 5.346 19.229 ;
     RECT  40.215 18.599 41.814 19.229 ;
     RECT  57.96 19.075 58.014 19.229 ;
     RECT  40.215 19.229 41.67 19.265 ;
     RECT  3.816 19.229 5.13 19.301 ;
     RECT  60.876 19.201 60.894 19.309 ;
     RECT  6.84 18.725 6.858 19.336 ;
     RECT  57.996 19.229 58.014 19.337 ;
     RECT  6.84 19.336 6.894 19.345 ;
     RECT  7.815 11.309 8.097 19.345 ;
     RECT  69.12 18.959 69.21 19.345 ;
     RECT  68.976 19.345 69.21 19.379 ;
     RECT  53.856 19.201 55.314 19.381 ;
     RECT  56.415 19.201 57.006 19.381 ;
     RECT  75.996 19.201 76.014 19.381 ;
     RECT  6.84 19.345 8.097 19.499 ;
     RECT  60.876 19.309 61.038 19.499 ;
     RECT  68.976 19.379 68.994 19.499 ;
     RECT  75.996 19.381 76.158 19.499 ;
     RECT  80.784 19.471 80.802 19.507 ;
     RECT  60.876 19.499 60.894 19.535 ;
     RECT  75.996 19.499 76.014 19.535 ;
     RECT  85.464 18.941 85.482 19.535 ;
     RECT  80.784 19.507 81.054 19.543 ;
     RECT  80.784 19.543 81.558 19.565 ;
     RECT  7.056 19.499 8.097 19.571 ;
     RECT  80.784 19.565 80.802 19.571 ;
     RECT  53.748 19.381 55.314 19.643 ;
     RECT  70.092 18.959 70.11 19.643 ;
     RECT  45.615 18.967 52.794 19.651 ;
     RECT  81.54 19.565 81.558 19.651 ;
     RECT  3.816 19.301 4.698 19.661 ;
     RECT  7.056 19.571 7.074 19.679 ;
     RECT  78.015 17.951 78.297 19.741 ;
     RECT  3.96 19.661 4.698 19.769 ;
     RECT  45.615 19.651 52.83 19.769 ;
     RECT  56.415 19.381 57.186 19.769 ;
     RECT  80.712 19.651 80.73 19.769 ;
     RECT  81.54 19.651 82.242 19.769 ;
     RECT  71.496 19.741 71.514 19.805 ;
     RECT  83.268 19.067 84.042 19.805 ;
     RECT  64.296 19.543 64.314 19.849 ;
     RECT  45.615 19.769 52.47 19.913 ;
     RECT  81.972 19.769 82.242 19.913 ;
     RECT  2.415 18.959 2.79 19.921 ;
     RECT  72.615 17.105 72.897 19.921 ;
     RECT  2.415 19.921 3.186 20.011 ;
     RECT  53.856 19.643 55.314 20.011 ;
     RECT  83.268 19.805 83.862 20.011 ;
     RECT  77.544 19.741 78.297 20.039 ;
     RECT  83.088 20.011 83.862 20.047 ;
     RECT  2.304 20.011 3.186 20.048 ;
     RECT  64.296 19.849 64.422 20.075 ;
     RECT  45.615 19.913 49.842 20.111 ;
     RECT  78.015 20.039 78.297 20.119 ;
     RECT  44.136 20.119 44.154 20.155 ;
     RECT  43.344 20.155 43.362 20.191 ;
     RECT  44.136 20.155 44.442 20.191 ;
     RECT  53.856 20.011 55.422 20.191 ;
     RECT  50.724 19.913 52.47 20.219 ;
     RECT  2.415 20.048 3.186 20.309 ;
     RECT  5.436 20.119 5.454 20.309 ;
     RECT  82.98 20.047 83.862 20.317 ;
     RECT  74.844 20.251 74.862 20.389 ;
     RECT  84.888 19.867 84.906 20.395 ;
     RECT  82.62 20.317 83.862 20.417 ;
     RECT  72.615 19.921 73.53 20.425 ;
     RECT  3.96 19.769 4.626 20.443 ;
     RECT  43.344 20.191 44.514 20.461 ;
     RECT  74.7 20.389 74.862 20.461 ;
     RECT  3.672 20.443 4.626 20.489 ;
     RECT  70.704 20.389 70.722 20.489 ;
     RECT  6.804 20.281 6.822 20.539 ;
     RECT  71.82 19.921 71.838 20.539 ;
     RECT  83.232 20.417 83.862 20.579 ;
     RECT  53.064 20.539 53.082 20.587 ;
     RECT  53.856 20.191 55.458 20.587 ;
     RECT  43.344 20.461 44.55 20.615 ;
     RECT  74.664 20.461 75.474 20.615 ;
     RECT  59.832 20.587 59.85 20.623 ;
     RECT  0.108 20.491 0.126 20.651 ;
     RECT  43.344 20.615 44.514 20.651 ;
     RECT  45.615 20.111 49.77 20.651 ;
     RECT  60.948 20.551 60.966 20.651 ;
     RECT  6.516 20.539 6.822 20.659 ;
     RECT  43.344 20.651 44.442 20.659 ;
     RECT  56.415 19.769 56.697 20.659 ;
     RECT  67.215 17.069 67.497 20.659 ;
     RECT  59.508 20.623 59.85 20.669 ;
     RECT  3.96 20.489 4.626 20.687 ;
     RECT  53.064 20.587 55.494 20.695 ;
     RECT  56.232 20.659 56.697 20.695 ;
     RECT  71.1 20.539 71.838 20.731 ;
     RECT  72.615 20.425 73.566 20.731 ;
     RECT  53.064 20.695 56.697 20.759 ;
     RECT  66.708 20.659 67.497 20.759 ;
     RECT  71.1 20.731 73.566 20.759 ;
     RECT  59.832 20.669 59.85 20.765 ;
     RECT  50.724 20.219 52.254 20.779 ;
     RECT  78.015 20.119 78.678 20.821 ;
     RECT  6.192 20.659 6.822 20.849 ;
     RECT  64.512 20.623 64.638 20.849 ;
     RECT  6.66 20.849 6.822 20.885 ;
     RECT  64.512 20.849 64.53 20.885 ;
     RECT  71.1 20.759 72.897 20.885 ;
     RECT  74.664 20.615 75.33 20.885 ;
     RECT  53.064 20.759 55.53 20.993 ;
     RECT  6.732 20.885 6.822 21.001 ;
     RECT  7.815 19.571 8.097 21.001 ;
     RECT  74.664 20.885 75.186 21.001 ;
     RECT  50.652 20.779 52.254 21.091 ;
     RECT  53.064 20.993 55.35 21.091 ;
     RECT  71.244 20.885 72.897 21.119 ;
     RECT  74.124 21.001 75.186 21.119 ;
     RECT  78.015 20.821 78.966 21.119 ;
     RECT  40.215 19.265 41.166 21.127 ;
     RECT  71.568 21.119 72.897 21.191 ;
     RECT  82.08 21.001 82.098 21.191 ;
     RECT  38.808 20.821 38.826 21.199 ;
     RECT  56.415 20.759 56.697 21.199 ;
     RECT  57.492 20.539 57.51 21.199 ;
     RECT  83.415 20.579 83.862 21.199 ;
     RECT  71.568 21.191 71.73 21.227 ;
     RECT  56.415 21.199 57.51 21.235 ;
     RECT  74.664 21.119 75.186 21.263 ;
     RECT  76.248 21.001 76.266 21.263 ;
     RECT  84.852 20.395 84.906 21.263 ;
     RECT  2.415 20.309 2.934 21.271 ;
     RECT  4.464 20.687 4.626 21.271 ;
     RECT  78.015 21.119 78.297 21.271 ;
     RECT  38.772 21.199 38.826 21.299 ;
     RECT  74.664 21.263 74.682 21.389 ;
     RECT  77.472 21.271 78.297 21.389 ;
     RECT  56.415 21.235 57.618 21.397 ;
     RECT  84.888 21.263 84.906 21.397 ;
     RECT  5.616 21.235 5.634 21.461 ;
     RECT  84.888 21.397 85.482 21.497 ;
     RECT  40.215 21.127 41.85 21.505 ;
     RECT  4.464 21.271 4.662 21.541 ;
     RECT  50.652 21.091 55.35 21.541 ;
     RECT  26.784 21.469 27.198 21.569 ;
     RECT  38.808 21.299 38.826 21.569 ;
     RECT  50.436 21.541 55.35 21.569 ;
     RECT  10.836 21.499 10.854 21.629 ;
     RECT  14.832 21.499 14.85 21.629 ;
     RECT  22.824 21.403 22.842 21.629 ;
     RECT  2.415 21.271 3.582 21.631 ;
     RECT  4.464 21.541 4.806 21.631 ;
     RECT  6.732 21.001 8.097 21.631 ;
     RECT  28.584 21.397 28.602 21.643 ;
     RECT  50.436 21.569 55.278 21.659 ;
     RECT  56.415 21.397 57.726 21.659 ;
     RECT  59.184 21.541 59.202 21.659 ;
     RECT  56.415 21.659 56.697 21.667 ;
     RECT  57.6 21.659 57.726 21.667 ;
     RECT  83.415 21.199 84.042 21.667 ;
     RECT  2.415 21.631 4.806 21.677 ;
     RECT  6.264 21.631 8.097 21.677 ;
     RECT  27.9 21.643 28.602 21.677 ;
     RECT  70.704 21.631 70.722 21.691 ;
     RECT  40.215 21.505 41.994 21.695 ;
     RECT  57.6 21.667 58.266 21.695 ;
     RECT  45.615 20.651 49.698 21.703 ;
     RECT  50.436 21.659 55.134 21.703 ;
     RECT  27.108 21.569 27.126 21.725 ;
     RECT  56.088 21.667 56.697 21.725 ;
     RECT  58.248 21.695 58.266 21.725 ;
     RECT  71.712 21.227 71.73 21.725 ;
     RECT  45.615 21.703 55.134 21.739 ;
     RECT  63.216 21.631 63.234 21.811 ;
     RECT  70.344 21.691 70.722 21.811 ;
     RECT  76.284 21.631 76.302 21.811 ;
     RECT  69.48 21.787 69.498 21.901 ;
     RECT  63.216 21.811 63.846 21.929 ;
     RECT  76.284 21.811 76.41 21.929 ;
     RECT  67.215 20.759 67.497 21.937 ;
     RECT  63.216 21.929 63.234 21.965 ;
     RECT  70.272 21.811 70.722 21.965 ;
     RECT  76.284 21.929 76.302 21.965 ;
     RECT  45.576 21.739 55.134 21.973 ;
     RECT  45.432 21.973 55.134 22.009 ;
     RECT  27.9 21.677 27.918 22.037 ;
     RECT  66.672 21.937 67.497 22.037 ;
     RECT  45.18 22.009 55.134 22.073 ;
     RECT  6.912 21.677 6.93 22.109 ;
     RECT  82.728 21.667 84.042 22.199 ;
     RECT  68.904 21.901 69.498 22.207 ;
     RECT  70.272 21.965 70.434 22.207 ;
     RECT  40.215 21.695 41.238 22.477 ;
     RECT  41.976 21.695 41.994 22.477 ;
     RECT  42.768 20.659 44.442 22.477 ;
     RECT  45.18 22.073 52.83 22.477 ;
     RECT  75.852 22.171 75.87 22.505 ;
     RECT  85.464 21.497 85.482 22.505 ;
     RECT  5.148 22.045 5.202 22.585 ;
     RECT  56.232 21.725 56.697 22.585 ;
     RECT  5.148 22.585 5.85 22.649 ;
     RECT  53.64 22.073 55.134 22.711 ;
     RECT  61.815 15.827 62.097 22.711 ;
     RECT  67.212 22.037 67.497 22.711 ;
     RECT  68.904 22.207 70.434 22.739 ;
     RECT  5.724 22.649 5.85 22.747 ;
     RECT  58.644 22.711 58.662 22.781 ;
     RECT  68.292 22.741 68.814 22.781 ;
     RECT  67.212 22.711 67.554 22.783 ;
     RECT  40.215 22.477 52.83 22.795 ;
     RECT  53.64 22.711 55.242 22.795 ;
     RECT  2.415 21.677 4.23 22.819 ;
     RECT  0.108 21.631 0.126 22.829 ;
     RECT  40.215 22.795 55.242 22.891 ;
     RECT  56.016 22.585 56.697 22.891 ;
     RECT  66.708 22.783 67.734 22.891 ;
     RECT  69.66 22.739 70.434 22.891 ;
     RECT  74.7 22.711 74.718 22.891 ;
     RECT  40.215 22.891 56.697 22.919 ;
     RECT  66.312 22.891 67.734 22.919 ;
     RECT  5.724 22.747 6.282 23.009 ;
     RECT  40.215 22.919 55.566 23.009 ;
     RECT  61.815 22.711 62.766 23.009 ;
     RECT  66.312 22.919 67.554 23.009 ;
     RECT  83.232 22.199 84.042 23.009 ;
     RECT  40.215 23.009 44.262 23.045 ;
     RECT  74.7 22.891 74.79 23.045 ;
     RECT  84.888 22.891 84.906 23.081 ;
     RECT  40.215 23.045 44.118 23.117 ;
     RECT  45 23.009 55.566 23.117 ;
     RECT  66.312 23.009 66.33 23.117 ;
     RECT  67.215 23.009 67.554 23.153 ;
     RECT  6.264 23.009 6.282 23.161 ;
     RECT  40.215 23.117 43.902 23.165 ;
     RECT  69.66 22.891 70.722 23.213 ;
     RECT  2.415 22.819 4.554 23.279 ;
     RECT  41.976 23.165 43.902 23.279 ;
     RECT  45.18 23.117 55.566 23.279 ;
     RECT  74.7 23.045 74.718 23.279 ;
     RECT  82.44 23.251 82.674 23.287 ;
     RECT  6.264 23.161 6.894 23.315 ;
     RECT  6.84 23.315 6.894 23.323 ;
     RECT  82.368 23.287 82.674 23.351 ;
     RECT  82.368 23.351 82.458 23.423 ;
     RECT  68.796 22.781 68.814 23.459 ;
     RECT  70.056 23.213 70.722 23.459 ;
     RECT  82.368 23.423 82.386 23.459 ;
     RECT  41.976 23.279 41.994 23.585 ;
     RECT  6.84 23.323 6.93 23.621 ;
     RECT  45.324 23.279 55.566 23.665 ;
     RECT  56.304 22.919 56.697 23.665 ;
     RECT  2.415 23.279 4.518 23.701 ;
     RECT  72.615 21.191 72.897 23.701 ;
     RECT  6.912 23.621 6.93 23.729 ;
     RECT  2.304 23.701 4.518 23.741 ;
     RECT  78.015 21.389 78.297 23.791 ;
     RECT  64.512 23.521 64.53 23.819 ;
     RECT  70.704 23.459 70.722 23.855 ;
     RECT  45.324 23.665 56.697 23.933 ;
     RECT  72.615 23.701 73.35 23.971 ;
     RECT  77.76 23.791 78.297 23.971 ;
     RECT  2.415 23.741 4.518 24.089 ;
     RECT  42.768 23.279 43.902 24.097 ;
     RECT  83.415 23.009 84.042 24.097 ;
     RECT  70.884 24.088 70.902 24.125 ;
     RECT  77.616 23.971 78.297 24.125 ;
     RECT  72.615 23.971 73.746 24.161 ;
     RECT  0.108 23.593 0.126 24.221 ;
     RECT  74.628 23.971 74.646 24.233 ;
     RECT  2.415 24.089 3.978 24.359 ;
     RECT  69.804 24.241 69.894 24.359 ;
     RECT  76.608 23.971 76.626 24.359 ;
     RECT  83.34 24.097 84.042 24.359 ;
     RECT  61.815 23.009 62.097 24.367 ;
     RECT  69.876 24.359 69.894 24.395 ;
     RECT  71.1 24.241 71.37 24.395 ;
     RECT  45.324 23.933 55.314 24.431 ;
     RECT  42.66 24.097 43.902 24.439 ;
     RECT  45.324 24.431 51.75 24.467 ;
     RECT  51.015 24.467 51.75 24.503 ;
     RECT  81.9 24.241 81.918 24.503 ;
     RECT  45.324 24.467 50.274 24.629 ;
     RECT  60.156 24.511 60.174 24.629 ;
     RECT  72.615 24.161 73.386 24.629 ;
     RECT  40.215 23.165 41.238 24.637 ;
     RECT  45.324 24.629 47.214 24.665 ;
     RECT  2.415 24.359 3.798 24.667 ;
     RECT  40.215 24.637 41.778 24.673 ;
     RECT  42.66 24.439 43.938 24.673 ;
     RECT  48.456 24.629 50.274 24.701 ;
     RECT  61.815 24.367 62.73 24.737 ;
     RECT  72.615 24.629 73.206 24.781 ;
     RECT  72.576 24.781 73.206 24.797 ;
     RECT  40.215 24.673 44.082 24.809 ;
     RECT  71.1 24.395 71.19 24.809 ;
     RECT  2.304 24.667 3.798 24.899 ;
     RECT  45.324 24.665 46.854 24.899 ;
     RECT  74.664 24.511 74.682 24.899 ;
     RECT  40.215 24.809 41.994 24.935 ;
     RECT  85.464 23.371 85.482 24.944 ;
     RECT  42.732 24.809 44.082 25.043 ;
     RECT  45.324 24.899 46.782 25.043 ;
     RECT  41.976 24.935 41.994 25.079 ;
     RECT  71.1 24.809 71.118 25.079 ;
     RECT  67.215 23.153 67.497 25.141 ;
     RECT  78.015 24.125 78.297 25.141 ;
     RECT  63.612 25.099 63.63 25.169 ;
     RECT  82.188 24.781 82.206 25.177 ;
     RECT  83.34 24.359 83.898 25.177 ;
     RECT  57.816 25.147 57.834 25.205 ;
     RECT  82.188 25.177 83.898 25.205 ;
     RECT  51.015 24.503 51.462 25.249 ;
     RECT  52.56 24.431 55.314 25.249 ;
     RECT  56.415 23.933 56.697 25.249 ;
     RECT  66.6 25.141 67.497 25.277 ;
     RECT  3.456 24.899 3.798 25.285 ;
     RECT  42.768 25.043 44.082 25.285 ;
     RECT  48.636 24.701 50.274 25.285 ;
     RECT  51.015 25.249 51.606 25.285 ;
     RECT  72.576 24.797 72.897 25.285 ;
     RECT  48.636 25.285 51.606 25.313 ;
     RECT  66.708 25.277 67.497 25.313 ;
     RECT  42.768 25.285 44.154 25.321 ;
     RECT  72.324 25.285 72.897 25.321 ;
     RECT  82.188 25.205 83.862 25.321 ;
     RECT  52.56 25.249 56.697 25.349 ;
     RECT  50.688 25.313 51.606 25.435 ;
     RECT  52.56 25.349 53.226 25.435 ;
     RECT  45.432 25.043 46.782 25.439 ;
     RECT  50.688 25.435 53.226 25.439 ;
     RECT  54.252 25.349 56.697 25.439 ;
     RECT  58.86 25.321 58.878 25.439 ;
     RECT  60.804 25.141 60.822 25.439 ;
     RECT  63.216 25.177 63.342 25.439 ;
     RECT  77.472 25.141 78.297 25.439 ;
     RECT  82.116 25.321 83.862 25.439 ;
     RECT  64.224 25.321 64.242 25.475 ;
     RECT  72.108 25.321 72.897 25.475 ;
     RECT  78.015 25.439 78.297 25.483 ;
     RECT  54.252 25.439 55.17 25.511 ;
     RECT  63.324 25.439 63.342 25.511 ;
     RECT  42.768 25.321 44.226 25.519 ;
     RECT  54.252 25.511 54.918 25.547 ;
     RECT  70.992 25.321 71.01 25.547 ;
     RECT  74.268 25.519 74.286 25.565 ;
     RECT  82.116 25.439 82.134 25.583 ;
     RECT  78.015 25.483 78.678 25.619 ;
     RECT  68.976 25.249 68.994 25.672 ;
     RECT  2.304 24.899 2.697 25.681 ;
     RECT  3.456 25.285 4.41 25.681 ;
     RECT  42.768 25.519 44.262 25.681 ;
     RECT  54.432 25.547 54.918 25.709 ;
     RECT  68.976 25.672 69.318 25.723 ;
     RECT  45.576 25.439 46.782 25.819 ;
     RECT  84.888 25.387 84.906 25.852 ;
     RECT  5.76 25.681 5.778 25.861 ;
     RECT  42.768 25.681 44.406 25.861 ;
     RECT  48.636 25.313 49.95 25.861 ;
     RECT  75.24 25.591 75.258 25.901 ;
     RECT  5.148 25.861 5.778 25.979 ;
     RECT  68.976 25.723 69.75 25.979 ;
     RECT  83.232 25.439 83.862 25.979 ;
     RECT  45.576 25.819 46.89 25.987 ;
     RECT  38.808 25.789 38.826 26.051 ;
     RECT  2.304 25.681 4.41 26.095 ;
     RECT  48.6 25.861 49.95 26.095 ;
     RECT  50.688 25.439 52.65 26.095 ;
     RECT  5.76 25.979 5.778 26.131 ;
     RECT  68.976 25.979 69.318 26.131 ;
     RECT  42.768 25.861 44.838 26.159 ;
     RECT  68.94 26.131 69.318 26.159 ;
     RECT  45.576 25.987 46.962 26.203 ;
     RECT  47.88 26.095 52.65 26.203 ;
     RECT  67.215 25.313 67.497 26.221 ;
     RECT  5.76 26.131 5.958 26.249 ;
     RECT  45.576 26.203 52.65 26.249 ;
     RECT  84.852 25.852 84.906 26.249 ;
     RECT  50.58 26.249 52.65 26.293 ;
     RECT  43.2 26.159 44.838 26.329 ;
     RECT  45.576 26.249 49.698 26.329 ;
     RECT  58.788 26.329 58.806 26.365 ;
     RECT  61.815 24.737 62.097 26.365 ;
     RECT  83.415 25.979 83.862 26.365 ;
     RECT  5.94 26.249 5.958 26.393 ;
     RECT  50.58 26.293 53.046 26.393 ;
     RECT  68.94 26.159 69.102 26.401 ;
     RECT  72.615 25.475 72.897 26.491 ;
     RECT  52.848 26.393 53.046 26.519 ;
     RECT  58.716 26.365 58.806 26.519 ;
     RECT  64.692 26.221 64.71 26.519 ;
     RECT  68.616 26.401 69.102 26.519 ;
     RECT  75.6 26.221 75.618 26.519 ;
     RECT  78.015 25.619 78.297 26.527 ;
     RECT  68.976 26.519 69.102 26.555 ;
     RECT  52.956 26.519 53.046 26.563 ;
     RECT  54.504 25.709 54.594 26.563 ;
     RECT  52.956 26.563 53.442 26.591 ;
     RECT  59.544 26.491 59.562 26.599 ;
     RECT  70.848 25.861 70.866 26.599 ;
     RECT  53.172 26.591 53.442 26.635 ;
     RECT  54.504 26.563 54.702 26.635 ;
     RECT  66.744 26.221 67.497 26.635 ;
     RECT  53.172 26.635 54.702 26.663 ;
     RECT  60.48 26.635 60.498 26.671 ;
     RECT  70.848 26.599 70.974 26.671 ;
     RECT  72.615 26.491 72.954 26.671 ;
     RECT  83.415 26.365 84.042 26.761 ;
     RECT  61.488 26.365 62.097 26.765 ;
     RECT  50.58 26.393 51.966 26.789 ;
     RECT  54.108 26.663 54.126 26.789 ;
     RECT  59.436 26.599 59.562 26.789 ;
     RECT  66.708 26.635 67.497 26.789 ;
     RECT  68.976 26.555 69.066 26.789 ;
     RECT  37.512 22.513 37.53 26.797 ;
     RECT  37.512 26.797 37.602 26.825 ;
     RECT  59.436 26.789 59.454 26.825 ;
     RECT  70.596 26.671 70.974 26.825 ;
     RECT  40.215 24.935 41.238 26.833 ;
     RECT  50.76 26.789 51.966 26.897 ;
     RECT  39.816 26.833 41.238 26.905 ;
     RECT  70.848 26.825 70.974 26.905 ;
     RECT  71.928 26.671 72.954 26.905 ;
     RECT  74.124 26.671 74.142 26.905 ;
     RECT  70.848 26.905 72.954 26.933 ;
     RECT  82.944 26.761 84.042 26.933 ;
     RECT  6.264 26.779 6.354 26.941 ;
     RECT  63.144 26.635 63.162 26.941 ;
     RECT  76.752 26.761 76.77 26.941 ;
     RECT  70.884 26.933 72.954 26.957 ;
     RECT  43.2 26.329 49.698 27.031 ;
     RECT  74.052 26.905 74.682 27.031 ;
     RECT  6.264 26.941 6.534 27.059 ;
     RECT  42.768 27.031 49.698 27.059 ;
     RECT  60.336 26.671 60.498 27.059 ;
     RECT  63.144 26.941 63.306 27.059 ;
     RECT  70.884 26.957 70.902 27.059 ;
     RECT  76.752 26.941 76.914 27.059 ;
     RECT  56.415 25.439 56.697 27.067 ;
     RECT  6.264 27.059 6.354 27.095 ;
     RECT  60.336 27.059 60.354 27.095 ;
     RECT  63.144 27.059 63.162 27.095 ;
     RECT  76.752 27.059 76.77 27.095 ;
     RECT  39.312 26.905 41.238 27.103 ;
     RECT  41.976 27.031 41.994 27.103 ;
     RECT  39.312 27.103 41.994 27.115 ;
     RECT  47.988 27.059 49.698 27.131 ;
     RECT  6.264 27.095 6.282 27.139 ;
     RECT  38.772 27.115 41.994 27.139 ;
     RECT  42.768 27.059 47.106 27.139 ;
     RECT  74.052 27.031 75.294 27.139 ;
     RECT  81.972 26.401 81.99 27.139 ;
     RECT  73.944 27.139 75.294 27.167 ;
     RECT  7.815 21.677 8.097 27.175 ;
     RECT  37.584 26.825 37.602 27.175 ;
     RECT  48.096 27.131 49.698 27.203 ;
     RECT  71.892 26.957 72.954 27.203 ;
     RECT  71.928 27.203 72.954 27.211 ;
     RECT  78.015 26.527 78.642 27.211 ;
     RECT  81.936 27.139 81.99 27.211 ;
     RECT  2.304 26.095 5.022 27.239 ;
     RECT  6.228 27.139 6.282 27.239 ;
     RECT  73.944 27.167 74.682 27.239 ;
     RECT  2.376 27.239 4.302 27.329 ;
     RECT  6.264 27.239 6.282 27.329 ;
     RECT  48.132 27.203 49.698 27.329 ;
     RECT  71.928 27.211 72.99 27.329 ;
     RECT  74.664 27.239 74.682 27.329 ;
     RECT  78.015 27.211 78.75 27.329 ;
     RECT  81.936 27.211 82.242 27.329 ;
     RECT  37.584 27.175 37.998 27.337 ;
     RECT  38.772 27.139 47.106 27.337 ;
     RECT  7.344 27.175 8.097 27.365 ;
     RECT  72.036 27.329 72.99 27.365 ;
     RECT  48.276 27.329 49.698 27.373 ;
     RECT  81.936 27.329 81.954 27.401 ;
     RECT  48.276 27.373 49.77 27.409 ;
     RECT  78.015 27.329 78.57 27.437 ;
     RECT  53.172 26.663 53.19 27.445 ;
     RECT  56.412 27.067 56.697 27.481 ;
     RECT  5.076 27.481 5.094 27.671 ;
     RECT  53.064 27.445 53.19 27.715 ;
     RECT  56.376 27.481 56.697 27.779 ;
     RECT  48.276 27.409 49.806 27.821 ;
     RECT  53.028 27.715 53.19 27.835 ;
     RECT  2.376 27.329 4.158 27.869 ;
     RECT  56.412 27.779 56.697 27.869 ;
     RECT  83.415 26.933 84.042 27.869 ;
     RECT  48.456 27.821 49.806 27.877 ;
     RECT  50.76 26.897 51.858 27.877 ;
     RECT  48.456 27.877 51.858 27.931 ;
     RECT  53.028 27.835 53.586 27.931 ;
     RECT  37.584 27.337 47.106 27.977 ;
     RECT  41.364 27.977 47.106 28.021 ;
     RECT  61.815 26.765 62.097 28.021 ;
     RECT  37.584 27.977 40.554 28.049 ;
     RECT  78.015 27.437 78.297 28.111 ;
     RECT  48.456 27.931 53.586 28.139 ;
     RECT  53.352 28.139 53.586 28.147 ;
     RECT  61.815 28.021 62.442 28.147 ;
     RECT  54.504 27.985 54.522 28.183 ;
     RECT  54.504 28.183 54.738 28.211 ;
     RECT  83.415 27.869 83.898 28.219 ;
     RECT  39.024 28.049 40.554 28.283 ;
     RECT  53.352 28.147 53.694 28.283 ;
     RECT  54.72 28.211 54.738 28.283 ;
     RECT  41.364 28.021 47.178 28.291 ;
     RECT  70.776 28.147 70.794 28.291 ;
     RECT  72.036 27.365 72.897 28.291 ;
     RECT  70.704 28.291 73.206 28.319 ;
     RECT  2.415 27.869 4.158 28.381 ;
     RECT  77.364 28.111 78.297 28.409 ;
     RECT  41.364 28.291 47.214 28.445 ;
     RECT  70.704 28.319 71.838 28.445 ;
     RECT  82.08 28.291 82.098 28.445 ;
     RECT  53.352 28.283 53.37 28.481 ;
     RECT  72.615 28.319 73.206 28.481 ;
     RECT  42.732 28.445 47.214 28.561 ;
     RECT  42.732 28.561 47.646 28.651 ;
     RECT  48.456 28.139 52.434 28.651 ;
     RECT  39.06 28.283 40.554 28.723 ;
     RECT  83.376 28.219 83.898 28.759 ;
     RECT  7.815 27.365 8.097 28.795 ;
     RECT  37.584 28.049 38.25 28.831 ;
     RECT  61.815 28.147 62.73 28.831 ;
     RECT  83.232 28.759 83.898 28.831 ;
     RECT  61.632 28.831 62.73 28.939 ;
     RECT  54.864 28.831 54.882 28.949 ;
     RECT  61.488 28.939 62.73 28.949 ;
     RECT  77.472 28.409 78.297 28.949 ;
     RECT  37.512 28.831 38.25 28.957 ;
     RECT  61.488 28.949 62.097 28.985 ;
     RECT  82.836 28.831 83.898 28.985 ;
     RECT  85.464 26.395 85.482 28.985 ;
     RECT  68.4 28.921 68.418 28.993 ;
     RECT  71.532 28.445 71.838 29.021 ;
     RECT  74.664 28.921 74.754 29.021 ;
     RECT  71.532 29.021 71.55 29.027 ;
     RECT  61.704 28.985 62.097 29.057 ;
     RECT  7.416 28.795 8.097 29.065 ;
     RECT  34.815 8.537 35.097 29.065 ;
     RECT  37.404 28.957 38.322 29.065 ;
     RECT  39.06 28.723 40.59 29.065 ;
     RECT  7.416 29.065 8.514 29.101 ;
     RECT  42.732 28.651 52.434 29.129 ;
     RECT  2.415 28.381 4.554 29.191 ;
     RECT  7.236 29.101 8.514 29.219 ;
     RECT  68.22 28.993 68.418 29.219 ;
     RECT  68.22 29.219 68.238 29.255 ;
     RECT  7.236 29.219 8.37 29.263 ;
     RECT  37.404 29.065 40.59 29.263 ;
     RECT  41.364 28.445 41.994 29.263 ;
     RECT  6.84 29.263 8.37 29.264 ;
     RECT  2.415 29.191 5.166 29.291 ;
     RECT  34.776 29.065 35.097 29.327 ;
     RECT  83.232 28.985 83.898 29.327 ;
     RECT  37.404 29.263 41.994 29.335 ;
     RECT  42.732 29.129 52.038 29.335 ;
     RECT  37.404 29.335 52.038 29.399 ;
     RECT  56.415 27.869 56.697 29.419 ;
     RECT  56.415 29.419 57.042 29.447 ;
     RECT  76.356 29.461 76.374 29.467 ;
     RECT  6.84 29.264 8.097 29.489 ;
     RECT  43.092 29.399 52.038 29.489 ;
     RECT  43.092 29.489 44.802 29.525 ;
     RECT  56.415 29.447 57.114 29.525 ;
     RECT  75.852 29.467 76.374 29.525 ;
     RECT  37.404 29.399 42.21 29.549 ;
     RECT  9.288 29.371 9.378 29.561 ;
     RECT  43.092 29.525 44.586 29.561 ;
     RECT  56.415 29.525 56.697 29.605 ;
     RECT  59.184 29.419 59.202 29.605 ;
     RECT  9.288 29.561 9.306 29.633 ;
     RECT  82.008 29.461 82.026 29.633 ;
     RECT  58.716 29.605 59.202 29.641 ;
     RECT  60.12 29.605 60.138 29.641 ;
     RECT  54.468 29.641 54.486 29.731 ;
     RECT  58.032 29.641 59.202 29.731 ;
     RECT  60.048 29.641 60.21 29.731 ;
     RECT  37.512 29.549 42.21 29.759 ;
     RECT  43.092 29.561 44.478 29.759 ;
     RECT  58.032 29.731 60.21 29.759 ;
     RECT  43.236 29.759 44.478 29.795 ;
     RECT  56.376 29.605 56.697 29.831 ;
     RECT  58.608 29.759 60.21 29.831 ;
     RECT  70.704 28.445 70.722 29.831 ;
     RECT  58.716 29.831 60.21 29.867 ;
     RECT  5.148 29.291 5.166 29.875 ;
     RECT  53.388 29.605 53.406 29.875 ;
     RECT  83.304 29.327 83.898 29.875 ;
     RECT  37.512 29.759 42.03 29.903 ;
     RECT  58.716 29.867 60.138 29.903 ;
     RECT  54.468 29.731 54.738 29.911 ;
     RECT  74.664 29.021 74.682 29.911 ;
     RECT  5.148 29.875 5.778 29.939 ;
     RECT  54.324 29.911 55.278 29.981 ;
     RECT  74.628 29.911 74.682 29.995 ;
     RECT  5.76 29.939 5.778 30.001 ;
     RECT  6.84 29.489 6.858 30.001 ;
     RECT  78.015 28.949 78.297 30.001 ;
     RECT  53.388 29.875 53.55 30.029 ;
     RECT  64.26 29.641 64.278 30.029 ;
     RECT  79.812 29.569 79.83 30.029 ;
     RECT  67.215 26.789 67.497 30.037 ;
     RECT  73.656 29.731 73.674 30.065 ;
     RECT  66.852 30.037 67.497 30.073 ;
     RECT  5.76 30.001 6.858 30.101 ;
     RECT  54.72 29.981 55.278 30.109 ;
     RECT  78.015 30.001 78.642 30.109 ;
     RECT  83.304 29.875 84.042 30.109 ;
     RECT  5.868 30.101 6.858 30.137 ;
     RECT  2.415 29.291 3.834 30.145 ;
     RECT  45.615 29.489 52.038 30.145 ;
     RECT  54.72 30.109 55.35 30.173 ;
     RECT  74.628 29.995 74.898 30.181 ;
     RECT  83.268 30.109 84.042 30.181 ;
     RECT  55.332 30.173 55.35 30.209 ;
     RECT  58.716 29.903 59.382 30.209 ;
     RECT  2.415 30.145 4.194 30.235 ;
     RECT  59.364 30.209 59.382 30.299 ;
     RECT  74.124 30.181 75.294 30.299 ;
     RECT  78.015 30.109 78.678 30.299 ;
     RECT  83.052 30.181 84.042 30.307 ;
     RECT  53.388 30.029 53.406 30.335 ;
     RECT  66.816 30.073 67.497 30.335 ;
     RECT  45.615 30.145 52.074 30.343 ;
     RECT  37.512 29.903 41.382 30.371 ;
     RECT  82.62 30.307 84.042 30.407 ;
     RECT  43.452 29.795 44.478 30.443 ;
     RECT  10.8 30.271 10.818 30.479 ;
     RECT  37.512 30.371 40.554 30.479 ;
     RECT  6.732 30.137 6.858 30.569 ;
     RECT  39.24 30.479 40.554 30.569 ;
     RECT  74.124 30.299 74.142 30.569 ;
     RECT  76.356 29.525 76.374 30.569 ;
     RECT  75.276 30.299 75.294 30.571 ;
     RECT  6.732 30.569 6.75 30.605 ;
     RECT  39.24 30.569 40.497 30.605 ;
     RECT  75.276 30.571 75.438 30.641 ;
     RECT  85.464 29.899 85.482 30.641 ;
     RECT  2.304 30.235 4.194 30.667 ;
     RECT  39.42 30.605 40.497 30.749 ;
     RECT  2.304 30.667 4.554 30.755 ;
     RECT  79.524 30.685 79.542 30.839 ;
     RECT  45.615 30.343 52.11 30.859 ;
     RECT  3.42 30.755 4.554 30.919 ;
     RECT  5.868 30.137 5.886 30.919 ;
     RECT  78.015 30.299 78.297 30.955 ;
     RECT  63.288 30.991 63.306 31.081 ;
     RECT  69.876 30.811 69.894 31.109 ;
     RECT  83.232 30.407 84.042 31.109 ;
     RECT  3.42 30.919 6.21 31.145 ;
     RECT  63.216 31.081 63.306 31.145 ;
     RECT  85.356 30.907 85.374 31.181 ;
     RECT  63.216 31.145 63.234 31.253 ;
     RECT  45.615 30.859 52.794 31.261 ;
     RECT  53.82 30.991 53.838 31.261 ;
     RECT  2.304 30.755 2.697 31.289 ;
     RECT  5.724 31.145 6.21 31.379 ;
     RECT  45.615 31.261 53.838 31.379 ;
     RECT  68.976 31.261 68.994 31.379 ;
     RECT  70.02 31.261 70.038 31.379 ;
     RECT  83.232 31.109 83.862 31.379 ;
     RECT  60.84 30.991 60.858 31.415 ;
     RECT  75.996 31.081 76.014 31.415 ;
     RECT  53.568 31.379 53.838 31.451 ;
     RECT  70.812 31.261 70.83 31.451 ;
     RECT  37.512 30.479 38.07 31.495 ;
     RECT  39.42 30.749 39.438 31.495 ;
     RECT  43.452 30.443 44.442 31.495 ;
     RECT  45.615 31.379 52.722 31.495 ;
     RECT  77.832 30.955 78.297 31.495 ;
     RECT  43.452 31.495 52.722 31.621 ;
     RECT  5.724 31.379 6.03 31.649 ;
     RECT  6.768 31.459 6.822 31.649 ;
     RECT  37.512 31.495 39.438 31.649 ;
     RECT  42.768 31.621 52.722 31.649 ;
     RECT  79.884 31.387 80.046 31.649 ;
     RECT  5.724 31.649 5.886 31.685 ;
     RECT  2.415 31.289 2.697 31.801 ;
     RECT  3.42 31.145 4.698 31.801 ;
     RECT  5.724 31.685 5.742 31.829 ;
     RECT  6.768 31.649 6.786 31.829 ;
     RECT  42.768 31.649 47.25 31.829 ;
     RECT  77.184 31.495 78.297 31.901 ;
     RECT  2.415 31.801 4.698 31.919 ;
     RECT  42.984 31.829 47.25 31.919 ;
     RECT  48.132 31.649 52.722 31.919 ;
     RECT  54 31.693 54.018 31.919 ;
     RECT  82.656 31.423 82.674 31.919 ;
     RECT  3.6 31.919 3.69 31.955 ;
     RECT  4.572 31.919 4.698 32.035 ;
     RECT  54.792 31.915 54.81 32.035 ;
     RECT  2.415 31.919 2.826 32.059 ;
     RECT  61.815 29.057 62.097 32.071 ;
     RECT  70.704 31.963 70.758 32.099 ;
     RECT  4.572 32.035 4.806 32.189 ;
     RECT  48.132 31.919 52.11 32.189 ;
     RECT  73.728 32.071 73.746 32.189 ;
     RECT  74.7 31.999 74.718 32.189 ;
     RECT  75.492 31.867 75.654 32.189 ;
     RECT  54.792 32.035 54.99 32.269 ;
     RECT  72.615 28.481 72.897 32.269 ;
     RECT  83.415 31.379 83.862 32.305 ;
     RECT  72.615 32.269 73.602 32.333 ;
     RECT  54.756 32.269 55.134 32.341 ;
     RECT  56.415 29.831 56.697 32.341 ;
     RECT  65.016 32.161 65.034 32.341 ;
     RECT  72.615 32.333 73.458 32.341 ;
     RECT  79.884 31.649 79.938 32.341 ;
     RECT  75.492 32.189 75.546 32.342 ;
     RECT  2.304 32.059 2.826 32.369 ;
     RECT  54.756 32.341 56.697 32.369 ;
     RECT  70.74 32.099 70.758 32.369 ;
     RECT  80.964 32.305 80.982 32.431 ;
     RECT  48.132 32.189 49.662 32.459 ;
     RECT  50.904 32.189 52.11 32.459 ;
     RECT  54.828 32.369 56.697 32.459 ;
     RECT  61.164 32.071 62.097 32.459 ;
     RECT  64.872 32.341 65.034 32.459 ;
     RECT  72.324 32.341 73.458 32.459 ;
     RECT  74.592 32.341 74.61 32.459 ;
     RECT  77.508 31.901 78.297 32.459 ;
     RECT  79.776 32.341 79.938 32.459 ;
     RECT  43.128 31.919 47.25 32.495 ;
     RECT  48.312 32.459 49.662 32.495 ;
     RECT  50.904 32.459 52.002 32.495 ;
     RECT  54.828 32.459 54.846 32.495 ;
     RECT  72.324 32.459 73.386 32.495 ;
     RECT  75.528 32.342 75.546 32.495 ;
     RECT  79.776 32.459 79.794 32.495 ;
     RECT  48.312 32.495 48.402 32.531 ;
     RECT  64.872 32.459 64.89 32.531 ;
     RECT  77.544 32.459 78.297 32.611 ;
     RECT  48.312 32.531 48.33 32.639 ;
     RECT  49.428 32.495 49.59 32.729 ;
     RECT  80.964 32.431 81.486 32.729 ;
     RECT  49.428 32.729 49.446 32.765 ;
     RECT  61.308 32.459 62.097 32.765 ;
     RECT  77.544 32.611 78.714 32.801 ;
     RECT  81.468 32.729 81.486 32.801 ;
     RECT  43.128 32.495 44.766 32.872 ;
     RECT  84.888 31.387 84.906 32.872 ;
     RECT  50.904 32.495 51.678 32.873 ;
     RECT  42.624 32.872 44.766 32.909 ;
     RECT  50.904 32.873 51.39 32.999 ;
     RECT  77.544 32.801 78.297 32.999 ;
     RECT  3.672 31.955 3.69 33.019 ;
     RECT  4.572 32.189 4.698 33.019 ;
     RECT  42.732 32.909 44.766 33.071 ;
     RECT  3.672 33.019 4.698 33.151 ;
     RECT  45.576 32.495 47.25 33.151 ;
     RECT  50.904 32.999 51.354 33.305 ;
     RECT  84.852 32.872 84.906 33.305 ;
     RECT  3.672 33.151 4.986 33.349 ;
     RECT  45.576 33.151 47.286 33.385 ;
     RECT  83.415 32.305 83.898 33.385 ;
     RECT  72.615 32.495 72.897 33.421 ;
     RECT  50.904 33.305 51.297 33.449 ;
     RECT  82.08 33.007 82.098 33.449 ;
     RECT  44.856 33.385 47.286 33.539 ;
     RECT  59.76 33.151 59.778 33.539 ;
     RECT  2.415 32.369 2.826 33.547 ;
     RECT  3.672 33.349 5.418 33.547 ;
     RECT  0.108 33.451 0.126 33.581 ;
     RECT  71.82 33.421 72.897 33.581 ;
     RECT  13.215 2.413 13.497 33.583 ;
     RECT  12.924 33.583 13.497 33.629 ;
     RECT  52.2 33.655 52.218 33.691 ;
     RECT  72.615 33.581 72.897 33.691 ;
     RECT  47.124 33.539 47.286 33.781 ;
     RECT  2.415 33.547 5.418 33.809 ;
     RECT  71.82 33.581 71.838 33.809 ;
     RECT  77.58 32.999 78.297 33.809 ;
     RECT  72.615 33.691 72.99 33.845 ;
     RECT  3.672 33.809 5.418 33.889 ;
     RECT  52.2 33.691 52.434 33.925 ;
     RECT  2.415 33.809 2.754 33.931 ;
     RECT  82.332 33.691 82.35 33.953 ;
     RECT  52.2 33.925 52.542 33.961 ;
     RECT  12.96 33.629 13.497 33.965 ;
     RECT  42.732 33.071 44.046 34.027 ;
     RECT  52.056 33.961 52.542 34.051 ;
     RECT  2.376 33.931 2.754 34.079 ;
     RECT  85.464 33.403 85.482 34.151 ;
     RECT  47.124 33.781 47.97 34.171 ;
     RECT  49.428 33.961 49.446 34.171 ;
     RECT  49.428 34.171 49.626 34.195 ;
     RECT  51.015 33.449 51.297 34.195 ;
     RECT  52.056 34.051 53.046 34.195 ;
     RECT  49.428 34.195 53.046 34.219 ;
     RECT  42.552 34.027 44.046 34.321 ;
     RECT  44.856 33.539 46.278 34.321 ;
     RECT  44.856 34.321 46.35 34.357 ;
     RECT  47.124 34.171 48.618 34.357 ;
     RECT  7.815 29.489 8.097 34.393 ;
     RECT  42.552 34.321 44.118 34.393 ;
     RECT  44.856 34.357 48.618 34.393 ;
     RECT  83.415 33.385 84.042 34.393 ;
     RECT  42.552 34.393 48.618 34.429 ;
     RECT  3.672 33.889 5.634 34.465 ;
     RECT  6.552 34.393 6.57 34.465 ;
     RECT  72.615 33.845 72.897 34.465 ;
     RECT  7.452 34.393 8.097 34.501 ;
     RECT  37.512 31.649 38.07 34.501 ;
     RECT  39.42 31.649 39.438 34.501 ;
     RECT  42.552 34.429 48.654 34.507 ;
     RECT  2.415 34.079 2.754 34.591 ;
     RECT  3.672 34.465 6.57 34.591 ;
     RECT  42.48 34.507 48.654 34.591 ;
     RECT  49.428 34.219 53.118 34.591 ;
     RECT  59.94 34.231 59.958 34.591 ;
     RECT  77.688 33.809 78.297 34.591 ;
     RECT  2.415 34.591 6.57 34.619 ;
     RECT  42.48 34.591 53.118 34.619 ;
     RECT  58.572 34.429 58.59 34.619 ;
     RECT  76.032 34.555 76.05 34.619 ;
     RECT  2.415 34.619 5.49 34.655 ;
     RECT  70.416 34.321 70.434 34.655 ;
     RECT  72 34.465 72.897 34.655 ;
     RECT  2.415 34.655 4.77 34.685 ;
     RECT  7.38 34.501 8.097 34.691 ;
     RECT  77.616 34.591 78.297 34.691 ;
     RECT  85.356 34.363 85.374 34.691 ;
     RECT  6.264 34.619 6.57 34.763 ;
     RECT  42.552 34.619 53.118 34.763 ;
     RECT  6.3 34.763 6.57 34.771 ;
     RECT  2.415 34.685 4.41 34.843 ;
     RECT  59.796 34.591 59.958 34.889 ;
     RECT  75.816 34.735 75.834 34.889 ;
     RECT  79.74 34.663 79.758 34.889 ;
     RECT  6.3 34.771 6.93 34.925 ;
     RECT  59.796 34.889 59.814 34.925 ;
     RECT  82.62 34.393 84.042 34.925 ;
     RECT  77.004 34.735 77.022 34.961 ;
     RECT  6.3 34.925 6.318 34.997 ;
     RECT  82.62 34.925 82.638 35.033 ;
     RECT  72.612 34.655 72.897 35.131 ;
     RECT  2.304 34.843 4.41 35.159 ;
     RECT  42.552 34.763 52.866 35.159 ;
     RECT  54.288 35.005 54.306 35.159 ;
     RECT  60.732 34.735 60.75 35.159 ;
     RECT  78.015 34.691 78.297 35.167 ;
     RECT  72.612 35.131 73.242 35.267 ;
     RECT  56.415 32.459 56.697 35.275 ;
     RECT  2.304 35.159 4.302 35.309 ;
     RECT  74.772 35.269 74.79 35.309 ;
     RECT  72.615 35.267 73.242 35.311 ;
     RECT  2.304 35.309 2.97 35.339 ;
     RECT  37.512 34.501 39.438 35.339 ;
     RECT  42.552 35.159 44.046 35.339 ;
     RECT  45.036 35.159 52.866 35.339 ;
     RECT  42.66 35.339 44.046 35.357 ;
     RECT  3.744 35.309 4.302 35.429 ;
     RECT  55.764 35.275 56.697 35.429 ;
     RECT  72.615 35.311 73.566 35.429 ;
     RECT  78.015 35.167 78.678 35.429 ;
     RECT  3.744 35.429 4.23 35.501 ;
     RECT  67.215 30.335 67.497 35.509 ;
     RECT  74.628 35.401 74.646 35.573 ;
     RECT  75.708 35.311 75.726 35.573 ;
     RECT  56.376 35.429 56.697 35.581 ;
     RECT  66.708 35.509 67.497 35.671 ;
     RECT  2.376 35.339 2.97 35.699 ;
     RECT  47.52 35.339 52.866 35.699 ;
     RECT  63.216 35.545 63.234 35.699 ;
     RECT  63.972 35.401 63.99 35.699 ;
     RECT  71.532 35.581 71.55 35.701 ;
     RECT  42.768 35.357 44.046 35.735 ;
     RECT  56.376 35.581 57.33 35.741 ;
     RECT  42.768 35.735 44.01 35.771 ;
     RECT  56.415 35.741 57.33 35.771 ;
     RECT  83.376 34.925 84.042 35.779 ;
     RECT  66.672 35.671 67.497 35.843 ;
     RECT  70.884 35.701 71.55 35.851 ;
     RECT  42.804 35.771 44.01 35.879 ;
     RECT  7.815 34.691 8.097 35.977 ;
     RECT  7.815 35.977 8.154 36.029 ;
     RECT  0.108 35.803 0.126 36.041 ;
     RECT  81.972 35.311 81.99 36.077 ;
     RECT  39.348 35.339 39.438 36.085 ;
     RECT  40.215 30.749 40.497 36.085 ;
     RECT  47.628 35.699 52.866 36.085 ;
     RECT  2.415 35.699 2.97 36.121 ;
     RECT  3.744 35.501 3.762 36.121 ;
     RECT  10.836 36.049 10.854 36.149 ;
     RECT  7.056 35.941 7.074 36.239 ;
     RECT  39.348 36.085 40.497 36.247 ;
     RECT  9.072 35.941 9.09 36.311 ;
     RECT  66.096 36.211 66.114 36.311 ;
     RECT  70.56 35.851 71.838 36.391 ;
     RECT  72.615 35.429 72.897 36.391 ;
     RECT  75.996 36.355 76.014 36.391 ;
     RECT  75.816 36.391 76.014 36.413 ;
     RECT  66.888 35.843 67.497 36.419 ;
     RECT  83.304 35.779 84.042 36.419 ;
     RECT  65.88 36.391 65.934 36.461 ;
     RECT  74.664 36.211 74.682 36.475 ;
     RECT  75.816 36.413 75.834 36.475 ;
     RECT  78.015 35.429 78.297 36.481 ;
     RECT  79.272 36.211 79.29 36.481 ;
     RECT  78.015 36.481 79.29 36.509 ;
     RECT  37.512 35.339 38.07 36.517 ;
     RECT  38.988 36.247 40.497 36.517 ;
     RECT  41.364 30.371 41.382 36.517 ;
     RECT  85.464 34.888 85.482 36.545 ;
     RECT  37.512 36.517 40.497 36.553 ;
     RECT  41.292 36.517 41.382 36.553 ;
     RECT  45.036 35.339 46.782 36.553 ;
     RECT  45.036 36.553 46.818 36.571 ;
     RECT  82.08 36.391 82.098 36.581 ;
     RECT  2.415 36.121 3.762 36.589 ;
     RECT  4.752 36.355 4.77 36.589 ;
     RECT  56.415 35.771 56.697 36.589 ;
     RECT  70.56 36.391 72.897 36.617 ;
     RECT  42.804 35.879 43.974 36.619 ;
     RECT  41.292 36.553 41.454 36.625 ;
     RECT  47.628 36.085 52.938 36.625 ;
     RECT  74.664 36.475 75.834 36.625 ;
     RECT  71.676 36.617 72.897 36.653 ;
     RECT  2.415 36.589 4.77 36.661 ;
     RECT  37.368 36.553 40.497 36.661 ;
     RECT  41.292 36.625 41.706 36.661 ;
     RECT  56.415 36.589 57.006 36.689 ;
     RECT  71.676 36.653 71.73 36.689 ;
     RECT  56.415 36.689 56.934 36.701 ;
     RECT  2.376 36.661 4.77 36.715 ;
     RECT  54.684 36.589 54.702 36.779 ;
     RECT  65.916 36.461 65.934 36.779 ;
     RECT  74.376 36.625 75.834 36.779 ;
     RECT  47.628 36.625 53.01 36.811 ;
     RECT  71.712 36.689 71.73 36.815 ;
     RECT  74.664 36.779 75.366 36.815 ;
     RECT  2.304 36.715 4.77 36.851 ;
     RECT  82.62 36.751 82.638 36.851 ;
     RECT  6.804 36.481 6.858 36.923 ;
     RECT  76.932 36.391 76.95 36.923 ;
     RECT  78.015 36.509 78.678 36.923 ;
     RECT  74.664 36.815 74.682 36.959 ;
     RECT  42.624 36.619 43.974 37.021 ;
     RECT  34.815 29.327 35.097 37.093 ;
     RECT  37.368 36.661 41.778 37.093 ;
     RECT  42.516 37.021 43.974 37.093 ;
     RECT  45 36.571 46.818 37.121 ;
     RECT  37.368 37.093 43.974 37.129 ;
     RECT  54.108 37.021 54.126 37.165 ;
     RECT  34.776 37.093 35.097 37.193 ;
     RECT  45.18 37.121 46.818 37.201 ;
     RECT  47.592 36.811 53.01 37.201 ;
     RECT  6.804 36.923 6.822 37.319 ;
     RECT  84.888 36.859 84.906 37.327 ;
     RECT  61.815 32.765 62.097 37.399 ;
     RECT  84.888 37.327 85.482 37.427 ;
     RECT  78.015 36.923 78.498 37.471 ;
     RECT  80.352 37.471 80.37 37.561 ;
     RECT  45.18 37.201 53.01 37.579 ;
     RECT  58.032 37.471 58.05 37.579 ;
     RECT  57.924 37.579 58.05 37.589 ;
     RECT  61.815 37.399 62.766 37.589 ;
     RECT  83.415 36.419 84.042 37.597 ;
     RECT  37.368 37.129 44.442 37.625 ;
     RECT  53.856 37.165 54.126 37.625 ;
     RECT  57.924 37.589 57.942 37.625 ;
     RECT  2.304 36.851 4.23 37.705 ;
     RECT  67.215 36.419 67.497 37.741 ;
     RECT  77.832 37.471 78.498 37.741 ;
     RECT  37.98 37.625 41.562 37.769 ;
     RECT  71.064 37.597 71.262 37.819 ;
     RECT  72.615 36.653 72.897 37.819 ;
     RECT  77.832 37.741 79.038 37.831 ;
     RECT  2.304 37.705 4.662 37.859 ;
     RECT  5.4 37.627 5.418 37.859 ;
     RECT  80.352 37.561 80.946 37.859 ;
     RECT  85.464 37.427 85.482 37.904 ;
     RECT  54.036 37.625 54.126 37.931 ;
     RECT  77.58 37.831 79.038 37.931 ;
     RECT  80.928 37.859 80.946 37.931 ;
     RECT  42.336 37.625 44.442 38.005 ;
     RECT  45.18 37.579 53.118 38.005 ;
     RECT  67.032 37.741 67.497 38.011 ;
     RECT  71.064 37.819 72.897 38.011 ;
     RECT  83.232 37.597 84.042 38.011 ;
     RECT  65.952 37.471 65.97 38.107 ;
     RECT  66.708 38.011 67.497 38.107 ;
     RECT  65.952 38.107 67.497 38.129 ;
     RECT  70.452 38.011 72.897 38.129 ;
     RECT  77.58 37.931 78.678 38.129 ;
     RECT  6.624 38.011 6.642 38.137 ;
     RECT  65.016 38.101 65.034 38.141 ;
     RECT  42.336 38.005 53.118 38.165 ;
     RECT  82.656 38.011 84.042 38.165 ;
     RECT  5.472 38.011 5.49 38.173 ;
     RECT  6.444 38.137 6.642 38.173 ;
     RECT  65.952 38.129 66.078 38.189 ;
     RECT  71.928 38.129 72.897 38.201 ;
     RECT  78.015 38.129 78.678 38.201 ;
     RECT  34.815 37.193 35.097 38.209 ;
     RECT  66.06 38.189 66.078 38.237 ;
     RECT  5.472 38.173 6.642 38.281 ;
     RECT  7.815 36.029 8.097 38.281 ;
     RECT  76.032 38.101 76.05 38.281 ;
     RECT  34.776 38.209 35.097 38.309 ;
     RECT  5.472 38.281 8.097 38.399 ;
     RECT  70.452 38.129 70.794 38.399 ;
     RECT  70.668 38.399 70.758 38.435 ;
     RECT  45.18 38.165 53.118 38.443 ;
     RECT  84.888 38.395 84.942 38.507 ;
     RECT  75.96 38.281 76.05 38.515 ;
     RECT  5.472 38.399 7.002 38.543 ;
     RECT  70.74 38.435 70.758 38.543 ;
     RECT  72.144 38.201 72.897 38.551 ;
     RECT  5.472 38.543 6.21 38.635 ;
     RECT  72.144 38.551 72.99 38.641 ;
     RECT  2.304 37.859 4.266 38.669 ;
     RECT  45.18 38.443 53.55 38.669 ;
     RECT  54.396 38.407 54.738 38.669 ;
     RECT  64.08 38.371 64.098 38.669 ;
     RECT  83.232 38.165 83.934 38.669 ;
     RECT  45.18 38.669 52.614 38.675 ;
     RECT  37.98 37.769 41.382 38.677 ;
     RECT  42.336 38.165 44.442 38.677 ;
     RECT  3.924 38.669 4.266 38.683 ;
     RECT  72.144 38.641 73.53 38.683 ;
     RECT  72.144 38.683 73.71 38.705 ;
     RECT  5.328 38.635 6.21 38.713 ;
     RECT  2.304 38.669 2.697 38.741 ;
     RECT  37.98 38.677 44.442 38.777 ;
     RECT  55.548 38.515 55.566 38.813 ;
     RECT  75.06 38.515 76.05 38.821 ;
     RECT  76.968 38.551 76.986 38.821 ;
     RECT  84.924 38.507 84.942 38.909 ;
     RECT  3.924 38.683 4.302 38.911 ;
     RECT  5.184 38.713 6.21 38.911 ;
     RECT  3.924 38.911 6.21 38.939 ;
     RECT  72.396 38.705 73.71 38.939 ;
     RECT  75.06 38.821 76.986 38.939 ;
     RECT  3.924 38.939 6.03 38.975 ;
     RECT  3.924 38.975 5.706 39.011 ;
     RECT  45.18 38.675 52.398 39.011 ;
     RECT  72.615 38.939 73.71 39.083 ;
     RECT  76.428 38.939 76.446 39.083 ;
     RECT  81.504 38.821 81.522 39.083 ;
     RECT  83.232 38.669 83.898 39.091 ;
     RECT  56.415 36.701 56.697 39.115 ;
     RECT  45.18 39.011 50.058 39.163 ;
     RECT  73.692 39.083 73.71 39.208 ;
     RECT  3.924 39.011 5.202 39.209 ;
     RECT  79.704 38.515 79.722 39.209 ;
     RECT  4.464 39.209 5.202 39.245 ;
     RECT  56.415 39.115 56.934 39.245 ;
     RECT  6.984 38.543 7.002 39.281 ;
     RECT  82.62 39.091 83.898 39.281 ;
     RECT  45.108 39.163 50.058 39.317 ;
     RECT  83.232 39.281 83.898 39.317 ;
     RECT  55.584 39.211 55.638 39.341 ;
     RECT  73.692 39.208 73.746 39.389 ;
     RECT  85.464 38.947 85.482 39.437 ;
     RECT  37.98 38.777 43.938 39.479 ;
     RECT  47.304 39.317 50.058 39.479 ;
     RECT  55.62 39.341 55.638 39.479 ;
     RECT  74.628 39.355 74.79 39.479 ;
     RECT  75.564 38.939 75.582 39.479 ;
     RECT  45.108 39.317 46.458 39.499 ;
     RECT  37.98 39.479 43.866 39.547 ;
     RECT  50.904 39.011 52.398 39.559 ;
     RECT  37.836 39.547 43.866 39.623 ;
     RECT  50.904 39.559 52.47 39.631 ;
     RECT  74.628 39.479 74.646 39.659 ;
     RECT  73.728 39.389 73.746 39.677 ;
     RECT  5.004 39.245 5.202 39.749 ;
     RECT  37.944 39.623 43.866 39.749 ;
     RECT  39.204 39.749 43.866 39.785 ;
     RECT  44.856 39.499 46.458 39.785 ;
     RECT  47.484 39.479 50.058 39.785 ;
     RECT  54.396 38.669 54.414 39.785 ;
     RECT  39.348 39.785 43.866 39.821 ;
     RECT  47.484 39.785 47.502 39.857 ;
     RECT  72.615 39.083 72.897 39.883 ;
     RECT  39.384 39.821 43.866 39.893 ;
     RECT  85.5 39.829 85.518 39.917 ;
     RECT  78.015 38.201 78.297 39.991 ;
     RECT  39.42 39.893 43.866 40.019 ;
     RECT  63.324 39.901 63.342 40.019 ;
     RECT  48.42 39.785 50.058 40.021 ;
     RECT  50.904 39.631 52.578 40.021 ;
     RECT  67.215 38.129 67.497 40.027 ;
     RECT  2.415 38.741 2.697 40.075 ;
     RECT  44.892 39.785 46.458 40.091 ;
     RECT  54.792 39.865 54.81 40.091 ;
     RECT  83.268 39.317 83.898 40.099 ;
     RECT  0.108 39.979 0.126 40.109 ;
     RECT  71.964 39.883 72.897 40.171 ;
     RECT  76.392 39.883 76.41 40.171 ;
     RECT  83.124 40.099 83.898 40.171 ;
     RECT  66.708 40.027 67.497 40.199 ;
     RECT  70.704 39.991 70.722 40.199 ;
     RECT  71.64 40.171 72.897 40.205 ;
     RECT  48.42 40.021 52.578 40.289 ;
     RECT  71.64 40.205 71.694 40.289 ;
     RECT  77.76 39.991 78.297 40.289 ;
     RECT  78.015 40.289 78.297 40.297 ;
     RECT  83.052 40.171 83.898 40.325 ;
     RECT  75.276 40.261 75.294 40.361 ;
     RECT  44.928 40.091 46.458 40.397 ;
     RECT  78.015 40.297 78.678 40.397 ;
     RECT  45.036 40.397 46.458 40.405 ;
     RECT  76.392 40.171 76.554 40.441 ;
     RECT  45.036 40.405 46.782 40.469 ;
     RECT  48.42 40.289 49.662 40.469 ;
     RECT  2.415 40.075 3.114 40.559 ;
     RECT  39.42 40.019 41.382 40.559 ;
     RECT  45.615 40.469 46.782 40.559 ;
     RECT  48.42 40.469 49.23 40.559 ;
     RECT  76.392 40.441 76.95 40.559 ;
     RECT  80.46 40.171 80.478 40.559 ;
     RECT  50.4 40.289 52.578 40.595 ;
     RECT  50.4 40.595 51.786 40.631 ;
     RECT  45.615 40.559 46.386 40.637 ;
     RECT  48.42 40.559 49.014 40.637 ;
     RECT  61.815 37.589 62.097 40.639 ;
     RECT  50.4 40.631 51.297 40.667 ;
     RECT  5.004 39.749 5.022 40.675 ;
     RECT  42.156 40.019 43.866 40.703 ;
     RECT  76.932 40.559 76.95 40.703 ;
     RECT  82.656 40.603 82.674 40.703 ;
     RECT  3.996 40.411 4.014 40.711 ;
     RECT  39.42 40.559 41.202 40.739 ;
     RECT  61.272 40.639 62.097 40.739 ;
     RECT  4.932 40.675 5.022 40.801 ;
     RECT  5.94 40.795 5.958 40.801 ;
     RECT  40.215 40.739 41.202 40.829 ;
     RECT  48.96 40.637 49.014 40.829 ;
     RECT  50.976 40.667 51.297 40.829 ;
     RECT  59.076 40.711 59.094 40.829 ;
     RECT  71.676 40.289 71.694 40.829 ;
     RECT  65.592 40.795 65.61 40.843 ;
     RECT  40.215 40.829 41.13 40.865 ;
     RECT  2.415 40.559 2.697 40.891 ;
     RECT  84.888 40.363 84.906 40.891 ;
     RECT  52.56 40.595 52.578 40.901 ;
     RECT  3.708 40.711 4.014 40.909 ;
     RECT  4.932 40.801 5.958 40.909 ;
     RECT  3.708 40.909 5.958 40.945 ;
     RECT  72.615 40.205 72.897 40.945 ;
     RECT  3.708 40.945 6.462 41.099 ;
     RECT  42.3 40.703 43.866 41.099 ;
     RECT  72.615 40.945 73.566 41.099 ;
     RECT  72.615 41.099 73.494 41.107 ;
     RECT  83.415 40.325 83.898 41.107 ;
     RECT  58.932 40.945 58.95 41.135 ;
     RECT  78.015 40.397 78.297 41.143 ;
     RECT  72.612 41.107 73.494 41.165 ;
     RECT  72.615 41.165 73.494 41.171 ;
     RECT  42.516 41.099 43.866 41.243 ;
     RECT  42.516 41.243 43.83 41.279 ;
     RECT  65.592 40.843 65.898 41.279 ;
     RECT  65.592 41.279 65.61 41.309 ;
     RECT  84.852 40.891 84.906 41.368 ;
     RECT  43.344 41.279 43.83 41.369 ;
     RECT  71.136 41.251 71.154 41.369 ;
     RECT  72.615 41.171 73.134 41.369 ;
     RECT  77.4 41.143 78.297 41.441 ;
     RECT  82.008 41.251 82.026 41.477 ;
     RECT  84.852 41.368 85.482 41.477 ;
     RECT  2.304 40.891 2.697 41.485 ;
     RECT  43.812 41.369 43.83 41.513 ;
     RECT  52.992 41.485 53.01 41.521 ;
     RECT  2.304 41.485 2.97 41.639 ;
     RECT  49.14 41.377 49.266 41.647 ;
     RECT  51.015 40.829 51.297 41.647 ;
     RECT  48.06 40.981 48.078 41.683 ;
     RECT  52.992 41.521 53.154 41.683 ;
     RECT  78.015 41.441 78.297 41.683 ;
     RECT  47.952 41.683 48.078 41.719 ;
     RECT  49.032 41.647 49.266 41.719 ;
     RECT  52.992 41.683 53.622 41.719 ;
     RECT  83.376 41.107 83.898 41.719 ;
     RECT  47.16 41.683 47.178 41.755 ;
     RECT  47.952 41.719 49.266 41.755 ;
     RECT  52.848 41.719 53.73 41.755 ;
     RECT  78.015 41.683 78.678 41.783 ;
     RECT  54.9 41.755 54.918 41.791 ;
     RECT  56.415 39.245 56.697 41.791 ;
     RECT  6.264 41.099 6.462 41.917 ;
     RECT  50.436 41.647 51.297 41.917 ;
     RECT  50.364 41.917 51.297 41.989 ;
     RECT  82.692 41.719 83.898 41.989 ;
     RECT  82.692 41.989 84.042 42.017 ;
     RECT  3.888 41.099 5.49 42.025 ;
     RECT  6.264 41.917 6.534 42.025 ;
     RECT  3.888 42.025 6.534 42.043 ;
     RECT  3.78 42.043 6.534 42.061 ;
     RECT  54.9 41.791 56.697 42.061 ;
     RECT  7.815 38.399 8.097 42.139 ;
     RECT  47.16 41.755 49.338 42.151 ;
     RECT  50.292 41.989 51.297 42.151 ;
     RECT  7.704 42.139 8.097 42.179 ;
     RECT  54.9 42.061 57.15 42.179 ;
     RECT  83.415 42.017 84.042 42.179 ;
     RECT  3.78 42.061 6.858 42.251 ;
     RECT  47.16 42.151 51.297 42.295 ;
     RECT  52.776 41.755 53.73 42.331 ;
     RECT  52.596 42.331 53.802 42.421 ;
     RECT  52.524 42.421 53.802 42.493 ;
     RECT  85.464 41.477 85.482 42.521 ;
     RECT  46.908 42.295 51.297 42.529 ;
     RECT  61.056 42.295 61.074 42.565 ;
     RECT  3.78 42.251 6.678 42.593 ;
     RECT  81.9 42.421 81.918 42.593 ;
     RECT  3.78 42.593 5.994 42.601 ;
     RECT  46.728 42.529 51.354 42.601 ;
     RECT  52.524 42.493 53.838 42.601 ;
     RECT  60.804 42.565 61.074 42.601 ;
     RECT  61.815 40.739 62.097 42.601 ;
     RECT  78.015 41.783 78.297 42.601 ;
     RECT  2.304 41.639 2.697 42.629 ;
     RECT  72.615 41.369 72.897 42.691 ;
     RECT  60.804 42.601 62.097 42.715 ;
     RECT  3.636 42.601 5.994 42.719 ;
     RECT  71.712 42.295 71.73 42.719 ;
     RECT  54.9 42.179 57.042 42.727 ;
     RECT  60.12 42.715 62.097 42.749 ;
     RECT  46.728 42.601 53.838 42.755 ;
     RECT  78.015 42.601 78.75 42.755 ;
     RECT  63.288 42.601 63.774 42.763 ;
     RECT  52.488 42.755 53.838 42.799 ;
     RECT  58.608 42.763 58.626 42.835 ;
     RECT  52.488 42.799 53.874 42.871 ;
     RECT  63.288 42.763 63.99 42.871 ;
     RECT  83.415 42.179 83.934 42.893 ;
     RECT  45.615 40.637 45.897 42.955 ;
     RECT  46.728 42.755 51.75 42.955 ;
     RECT  5.616 42.719 5.994 42.989 ;
     RECT  26.604 42.763 26.622 42.989 ;
     RECT  63.036 42.871 64.494 42.989 ;
     RECT  63.036 42.989 63.054 43.025 ;
     RECT  72.615 42.691 72.954 43.025 ;
     RECT  27.936 42.997 28.17 43.037 ;
     RECT  64.476 42.989 64.494 43.061 ;
     RECT  60.12 42.749 60.354 43.069 ;
     RECT  3.636 42.719 4.59 43.105 ;
     RECT  54.828 42.727 57.042 43.105 ;
     RECT  58.104 42.835 58.626 43.105 ;
     RECT  59.724 43.069 60.354 43.105 ;
     RECT  54.72 43.105 57.042 43.141 ;
     RECT  6.804 43.069 6.822 43.169 ;
     RECT  42.768 43.069 42.786 43.169 ;
     RECT  3.6 43.105 4.59 43.259 ;
     RECT  58.104 43.105 60.354 43.259 ;
     RECT  58.932 43.259 60.354 43.277 ;
     RECT  3.6 43.259 4.086 43.295 ;
     RECT  52.488 42.871 53.946 43.339 ;
     RECT  54.72 43.141 57.33 43.339 ;
     RECT  52.488 43.339 57.33 43.367 ;
     RECT  5.76 42.989 5.994 43.411 ;
     RECT  58.968 43.277 60.354 43.501 ;
     RECT  61.128 42.749 62.097 43.501 ;
     RECT  5.76 43.411 6.318 43.565 ;
     RECT  45.615 42.955 51.75 43.609 ;
     RECT  52.488 43.367 54.162 43.609 ;
     RECT  4.068 43.295 4.086 43.637 ;
     RECT  83.415 42.893 83.898 43.645 ;
     RECT  0.108 43.243 0.126 43.675 ;
     RECT  58.968 43.501 62.097 43.681 ;
     RECT  5.76 43.565 5.994 43.709 ;
     RECT  27.936 43.037 27.954 43.709 ;
     RECT  41.832 43.681 41.85 43.771 ;
     RECT  58.968 43.681 62.334 43.771 ;
     RECT  0.108 43.675 0.162 43.799 ;
     RECT  45.615 43.609 54.162 43.799 ;
     RECT  58.968 43.771 62.694 43.799 ;
     RECT  2.415 42.629 2.697 43.819 ;
     RECT  43.776 43.681 43.794 43.843 ;
     RECT  54.936 43.367 57.33 43.843 ;
     RECT  0.144 43.799 0.162 43.853 ;
     RECT  45.615 43.799 51.318 43.871 ;
     RECT  85.464 43.843 85.482 43.901 ;
     RECT  40.215 40.865 40.806 43.915 ;
     RECT  41.832 43.771 42.21 43.915 ;
     RECT  43.38 43.843 43.83 43.951 ;
     RECT  60.804 43.799 62.694 43.951 ;
     RECT  71.856 43.501 71.874 43.951 ;
     RECT  72.615 43.025 72.897 43.951 ;
     RECT  5.58 43.951 5.742 44.069 ;
     RECT  54.936 43.843 57.726 44.069 ;
     RECT  58.968 43.799 59.418 44.069 ;
     RECT  40.215 43.915 40.914 44.077 ;
     RECT  41.832 43.915 42.426 44.077 ;
     RECT  43.38 43.951 44.442 44.077 ;
     RECT  45.615 43.871 51.297 44.077 ;
     RECT  71.856 43.951 72.897 44.105 ;
     RECT  40.215 44.077 42.426 44.113 ;
     RECT  43.38 44.077 44.766 44.113 ;
     RECT  45.54 44.077 51.297 44.113 ;
     RECT  40.215 44.113 42.498 44.149 ;
     RECT  40.215 44.149 42.57 44.185 ;
     RECT  43.38 44.113 51.297 44.185 ;
     RECT  52.272 43.799 54.162 44.185 ;
     RECT  54.936 44.069 57.438 44.185 ;
     RECT  81.9 44.041 81.918 44.213 ;
     RECT  2.415 43.819 3.15 44.221 ;
     RECT  82.656 43.681 82.674 44.221 ;
     RECT  70.704 43.915 70.722 44.249 ;
     RECT  71.928 44.105 72.897 44.339 ;
     RECT  81.972 44.221 82.674 44.339 ;
     RECT  81.972 44.339 82.026 44.375 ;
     RECT  60.804 43.951 62.766 44.411 ;
     RECT  2.415 44.221 3.474 44.419 ;
     RECT  84.924 44.149 84.942 44.429 ;
     RECT  52.272 44.185 57.438 44.447 ;
     RECT  74.628 44.347 74.646 44.447 ;
     RECT  39.42 40.739 39.438 44.455 ;
     RECT  61.344 44.411 62.766 44.477 ;
     RECT  4.5 44.455 4.518 44.491 ;
     RECT  38.844 44.455 39.438 44.491 ;
     RECT  40.215 44.185 51.297 44.525 ;
     RECT  61.668 44.477 62.766 44.539 ;
     RECT  7.815 42.179 8.097 44.581 ;
     RECT  72.504 44.339 72.897 44.581 ;
     RECT  38.772 44.491 39.438 44.609 ;
     RECT  61.668 44.539 63.198 44.609 ;
     RECT  44.892 44.525 51.297 44.645 ;
     RECT  64.548 44.539 64.566 44.645 ;
     RECT  10.8 44.455 10.818 44.689 ;
     RECT  83.415 43.645 84.042 44.689 ;
     RECT  38.88 44.609 39.438 44.717 ;
     RECT  5.724 44.069 5.742 44.725 ;
     RECT  44.964 44.645 51.297 44.725 ;
     RECT  4.392 44.491 4.518 44.761 ;
     RECT  44.964 44.725 51.354 44.761 ;
     RECT  10.728 44.689 10.818 44.789 ;
     RECT  44.964 44.761 51.426 44.789 ;
     RECT  4.392 44.761 4.77 44.851 ;
     RECT  5.724 44.725 6.282 44.851 ;
     RECT  39.42 44.717 39.438 44.851 ;
     RECT  40.215 44.525 44.154 44.851 ;
     RECT  2.415 44.419 3.654 44.875 ;
     RECT  4.392 44.851 6.282 44.875 ;
     RECT  2.415 44.875 6.282 44.879 ;
     RECT  39.42 44.851 44.154 44.879 ;
     RECT  52.272 44.447 57.042 44.879 ;
     RECT  63.972 44.761 64.278 44.879 ;
     RECT  72.504 44.581 73.494 44.879 ;
     RECT  65.196 44.761 65.214 44.915 ;
     RECT  81.972 44.375 81.99 44.915 ;
     RECT  85.464 44.875 85.482 44.915 ;
     RECT  59.22 44.069 59.418 44.923 ;
     RECT  7.668 44.581 8.097 44.951 ;
     RECT  45.036 44.789 51.426 44.951 ;
     RECT  39.708 44.879 43.866 44.987 ;
     RECT  61.815 44.609 63.198 45.005 ;
     RECT  39.708 44.987 41.13 45.023 ;
     RECT  64.26 44.879 64.278 45.023 ;
     RECT  59.22 44.923 59.49 45.031 ;
     RECT  2.415 44.879 5.346 45.067 ;
     RECT  61.815 45.005 62.802 45.149 ;
     RECT  65.484 45.031 65.502 45.149 ;
     RECT  72.504 44.879 72.897 45.149 ;
     RECT  78.015 42.755 78.297 45.157 ;
     RECT  59.22 45.031 60.03 45.185 ;
     RECT  61.815 45.149 62.73 45.185 ;
     RECT  83.376 44.689 84.042 45.193 ;
     RECT  45.504 44.951 51.426 45.221 ;
     RECT  82.656 45.193 84.042 45.257 ;
     RECT  41.976 44.987 43.866 45.293 ;
     RECT  74.664 45.157 74.682 45.293 ;
     RECT  2.304 45.067 5.346 45.329 ;
     RECT  61.815 45.185 62.37 45.329 ;
     RECT  42.732 45.293 43.866 45.419 ;
     RECT  45.504 45.221 46.566 45.419 ;
     RECT  47.412 45.221 51.426 45.427 ;
     RECT  47.412 45.427 51.462 45.463 ;
     RECT  47.412 45.463 51.498 45.491 ;
     RECT  52.776 44.879 57.042 45.499 ;
     RECT  57.852 45.163 57.87 45.499 ;
     RECT  82.656 45.257 82.674 45.527 ;
     RECT  2.415 45.329 5.346 45.563 ;
     RECT  52.776 45.499 57.87 45.571 ;
     RECT  59.22 45.185 59.706 45.571 ;
     RECT  78.015 45.157 78.678 45.599 ;
     RECT  6.264 44.879 6.282 45.661 ;
     RECT  52.776 45.571 59.706 45.689 ;
     RECT  52.776 45.689 57.474 45.725 ;
     RECT  45.504 45.419 46.53 45.769 ;
     RECT  47.88 45.491 51.498 45.769 ;
     RECT  61.815 45.329 62.097 45.805 ;
     RECT  0.108 45.547 0.126 45.833 ;
     RECT  5.796 45.661 6.75 45.833 ;
     RECT  6.048 45.833 6.75 45.841 ;
     RECT  45.108 45.769 46.53 45.841 ;
     RECT  58.284 45.689 59.706 45.869 ;
     RECT  61.344 45.805 62.097 45.931 ;
     RECT  58.68 45.869 59.706 45.959 ;
     RECT  52.776 45.725 57.402 46.013 ;
     RECT  41.976 45.293 41.994 46.039 ;
     RECT  6.048 45.841 6.894 46.067 ;
     RECT  39.708 45.023 40.806 46.075 ;
     RECT  41.616 46.039 41.994 46.075 ;
     RECT  42.732 45.419 43.686 46.075 ;
     RECT  83.415 45.257 84.042 46.075 ;
     RECT  45.036 45.841 46.53 46.103 ;
     RECT  47.88 45.769 51.966 46.171 ;
     RECT  52.776 46.013 54.054 46.171 ;
     RECT  60.66 45.931 62.097 46.171 ;
     RECT  6.048 46.067 6.858 46.229 ;
     RECT  47.88 46.171 54.054 46.229 ;
     RECT  83.232 46.075 84.042 46.229 ;
     RECT  45.396 46.103 46.53 46.237 ;
     RECT  71.46 45.931 71.478 46.265 ;
     RECT  60.66 46.171 62.694 46.309 ;
     RECT  55.008 46.013 57.294 46.349 ;
     RECT  60.66 46.309 62.73 46.381 ;
     RECT  2.415 45.563 4.554 46.459 ;
     RECT  48.204 46.229 54.054 46.499 ;
     RECT  78.015 45.599 78.297 46.507 ;
     RECT  45.396 46.237 47.106 46.535 ;
     RECT  60.66 46.381 63.342 46.535 ;
     RECT  60.66 46.535 62.946 46.571 ;
     RECT  39.708 46.075 43.686 46.607 ;
     RECT  48.204 46.499 53.982 46.607 ;
     RECT  74.664 46.507 74.682 46.607 ;
     RECT  60.66 46.571 60.894 46.643 ;
     RECT  42.696 46.607 43.686 46.651 ;
     RECT  44.46 46.201 44.478 46.651 ;
     RECT  42.696 46.651 44.478 46.679 ;
     RECT  45.396 46.535 47.07 46.679 ;
     RECT  62.928 46.571 62.946 46.679 ;
     RECT  78.015 46.507 78.678 46.679 ;
     RECT  39.708 46.607 41.814 46.769 ;
     RECT  55.008 46.349 57.186 46.769 ;
     RECT  52.488 46.607 53.982 46.877 ;
     RECT  58.68 45.959 59.094 46.885 ;
     RECT  2.304 46.459 4.554 46.949 ;
     RECT  48.204 46.607 51.606 47.011 ;
     RECT  60.228 46.813 60.39 47.011 ;
     RECT  55.008 46.769 57.15 47.035 ;
     RECT  42.696 46.679 44.442 47.039 ;
     RECT  45.396 46.679 46.962 47.075 ;
     RECT  82.188 46.921 82.206 47.075 ;
     RECT  58.68 46.885 59.346 47.083 ;
     RECT  60.084 47.011 60.39 47.083 ;
     RECT  58.68 47.083 60.39 47.131 ;
     RECT  70.704 46.345 70.722 47.147 ;
     RECT  45.396 47.075 46.926 47.155 ;
     RECT  58.428 47.131 60.39 47.165 ;
     RECT  2.376 46.949 4.554 47.191 ;
     RECT  58.428 47.165 58.446 47.309 ;
     RECT  52.488 46.877 53.91 47.389 ;
     RECT  85.464 45.883 85.482 47.417 ;
     RECT  48.168 47.011 51.606 47.425 ;
     RECT  59.22 47.165 60.39 47.425 ;
     RECT  52.416 47.389 53.91 47.489 ;
     RECT  2.376 47.191 4.77 47.579 ;
     RECT  52.488 47.489 53.91 47.651 ;
     RECT  74.628 47.551 74.646 47.651 ;
     RECT  2.415 47.579 4.77 47.659 ;
     RECT  39.708 46.769 41.202 47.659 ;
     RECT  39.708 47.659 41.886 47.695 ;
     RECT  42.696 47.039 44.37 47.695 ;
     RECT  48.096 47.425 51.606 47.695 ;
     RECT  59.22 47.425 60.678 47.695 ;
     RECT  2.415 47.659 4.914 47.707 ;
     RECT  59.22 47.695 60.894 47.723 ;
     RECT  48.06 47.695 51.606 47.731 ;
     RECT  52.524 47.651 53.91 47.731 ;
     RECT  54.72 47.035 57.15 47.731 ;
     RECT  48.06 47.731 51.678 47.821 ;
     RECT  47.772 47.821 51.678 47.849 ;
     RECT  59.868 47.723 60.894 47.849 ;
     RECT  63.36 47.623 63.378 47.849 ;
     RECT  45.36 47.155 46.926 47.929 ;
     RECT  47.772 47.849 51.498 47.929 ;
     RECT  86.292 47.857 86.31 47.933 ;
     RECT  39.708 47.695 44.37 47.965 ;
     RECT  45.108 47.929 46.926 47.965 ;
     RECT  2.415 47.707 5.634 48.001 ;
     RECT  58.68 47.929 59.13 48.029 ;
     RECT  2.415 48.001 5.67 48.091 ;
     RECT  52.524 47.731 57.15 48.091 ;
     RECT  72.615 45.149 72.897 48.091 ;
     RECT  2.415 48.091 5.778 48.119 ;
     RECT  6.804 48.001 6.822 48.191 ;
     RECT  52.524 48.091 57.798 48.227 ;
     RECT  39.708 47.965 46.926 48.235 ;
     RECT  39.708 48.235 46.962 48.271 ;
     RECT  47.736 47.929 51.498 48.271 ;
     RECT  61.815 46.571 62.097 48.271 ;
     RECT  63.576 48.229 63.918 48.271 ;
     RECT  64.836 47.857 64.854 48.271 ;
     RECT  52.524 48.227 57.294 48.299 ;
     RECT  61.815 48.271 62.37 48.361 ;
     RECT  63.576 48.271 64.854 48.379 ;
     RECT  52.524 48.299 55.674 48.389 ;
     RECT  58.932 48.029 59.13 48.389 ;
     RECT  60.912 48.271 60.93 48.389 ;
     RECT  72.615 48.091 73.278 48.389 ;
     RECT  83.415 46.229 84.042 48.397 ;
     RECT  59.004 48.389 59.022 48.425 ;
     RECT  63.576 48.379 65.286 48.425 ;
     RECT  82.116 48.271 82.134 48.425 ;
     RECT  0.108 46.939 0.126 48.461 ;
     RECT  61.815 48.361 62.73 48.461 ;
     RECT  85.356 48.379 85.374 48.461 ;
     RECT  66.096 48.361 66.114 48.541 ;
     RECT  56.415 48.299 57.294 48.569 ;
     RECT  52.524 48.389 55.17 48.631 ;
     RECT  65.664 48.541 66.114 48.659 ;
     RECT  83.232 48.397 84.042 48.659 ;
     RECT  39.708 48.271 51.498 48.667 ;
     RECT  52.308 48.631 55.17 48.667 ;
     RECT  74.124 48.361 74.142 48.695 ;
     RECT  39.708 48.667 55.17 48.763 ;
     RECT  39.564 48.763 55.17 48.803 ;
     RECT  63.576 48.425 64.926 48.803 ;
     RECT  66.096 48.659 66.114 48.803 ;
     RECT  34.815 38.309 35.097 48.811 ;
     RECT  72.615 48.389 72.897 48.811 ;
     RECT  56.415 48.569 56.898 48.845 ;
     RECT  5.256 48.119 5.778 48.901 ;
     RECT  61.815 48.461 62.514 48.901 ;
     RECT  34.776 48.811 35.097 48.929 ;
     RECT  61.776 48.901 62.514 48.929 ;
     RECT  72.396 48.811 72.897 48.929 ;
     RECT  39.708 48.803 55.17 48.941 ;
     RECT  5.148 48.901 5.778 48.965 ;
     RECT  39.708 48.941 43.686 48.965 ;
     RECT  82.368 48.937 82.386 48.973 ;
     RECT  2.415 48.119 4.374 49.001 ;
     RECT  37.044 47.461 37.062 49.001 ;
     RECT  39.708 48.965 43.326 49.001 ;
     RECT  63.576 48.803 64.278 49.003 ;
     RECT  61.776 48.929 62.097 49.037 ;
     RECT  82.368 48.973 82.458 49.073 ;
     RECT  82.368 49.073 82.386 49.109 ;
     RECT  2.415 49.001 2.862 49.243 ;
     RECT  2.304 49.243 2.862 49.307 ;
     RECT  44.748 48.941 55.17 49.307 ;
     RECT  78.015 46.679 78.297 49.351 ;
     RECT  63.432 49.003 64.278 49.373 ;
     RECT  73.8 49.171 73.818 49.469 ;
     RECT  64.116 49.373 64.278 49.505 ;
     RECT  78.015 49.351 78.678 49.505 ;
     RECT  85.464 48.859 85.482 49.541 ;
     RECT  5.904 49.531 5.922 49.577 ;
     RECT  45.036 49.307 55.134 49.577 ;
     RECT  57.564 49.441 57.582 49.613 ;
     RECT  72.615 48.929 72.897 49.711 ;
     RECT  60.48 49.549 60.498 49.747 ;
     RECT  60.48 49.747 60.642 49.855 ;
     RECT  61.815 49.037 62.097 49.891 ;
     RECT  83.415 48.659 84.042 49.891 ;
     RECT  60.336 49.855 60.642 50.009 ;
     RECT  72.036 49.711 72.897 50.009 ;
     RECT  84.888 49.867 84.906 50.009 ;
     RECT  3.816 49.001 4.374 50.045 ;
     RECT  82.872 49.891 84.042 50.045 ;
     RECT  39.708 49.001 43.254 50.107 ;
     RECT  74.664 50.017 74.682 50.117 ;
     RECT  45.036 49.577 49.41 50.125 ;
     RECT  44.892 50.125 49.41 50.153 ;
     RECT  61.668 49.891 62.097 50.153 ;
     RECT  5.148 48.965 5.166 50.155 ;
     RECT  67.215 40.199 67.497 50.155 ;
     RECT  3.888 50.045 4.374 50.161 ;
     RECT  5.148 50.155 5.67 50.161 ;
     RECT  56.415 48.845 56.697 50.161 ;
     RECT  60.624 50.009 60.642 50.161 ;
     RECT  65.484 49.981 65.502 50.161 ;
     RECT  39.6 50.107 43.254 50.189 ;
     RECT  2.304 49.307 2.697 50.237 ;
     RECT  50.148 49.577 55.134 50.251 ;
     RECT  55.872 50.161 56.697 50.251 ;
     RECT  60.624 50.161 60.822 50.251 ;
     RECT  61.815 50.153 62.097 50.251 ;
     RECT  64.836 50.161 66.114 50.251 ;
     RECT  67.215 50.155 67.77 50.251 ;
     RECT  3.888 50.161 5.67 50.279 ;
     RECT  64.836 50.251 67.77 50.279 ;
     RECT  83.415 50.045 84.042 50.279 ;
     RECT  60.624 50.251 60.858 50.351 ;
     RECT  66.636 50.279 67.77 50.351 ;
     RECT  48.06 50.153 49.41 50.359 ;
     RECT  50.148 50.251 56.697 50.359 ;
     RECT  60.624 50.351 60.822 50.429 ;
     RECT  84.924 50.389 84.942 50.429 ;
     RECT  6.84 50.161 6.93 50.431 ;
     RECT  7.815 44.951 8.097 50.431 ;
     RECT  64.836 50.279 65.826 50.431 ;
     RECT  66.708 50.351 67.77 50.431 ;
     RECT  76.14 50.287 76.158 50.521 ;
     RECT  6.264 50.431 6.93 50.549 ;
     RECT  7.815 50.431 8.154 50.549 ;
     RECT  60.804 50.429 60.822 50.549 ;
     RECT  76.14 50.521 76.302 50.549 ;
     RECT  66.708 50.431 68.418 50.585 ;
     RECT  39.708 50.189 43.254 50.593 ;
     RECT  6.912 50.549 6.93 50.621 ;
     RECT  61.815 50.251 62.73 50.621 ;
     RECT  76.284 50.549 76.302 50.657 ;
     RECT  3.888 50.279 5.274 50.693 ;
     RECT  82.656 50.593 82.674 50.693 ;
     RECT  7.815 50.549 8.097 50.701 ;
     RECT  66.708 50.585 68.094 50.729 ;
     RECT  7.668 50.701 8.097 50.819 ;
     RECT  66.708 50.729 67.914 50.819 ;
     RECT  39.708 50.593 43.326 50.855 ;
     RECT  75.42 50.629 75.438 50.855 ;
     RECT  44.892 50.153 47.286 50.923 ;
     RECT  41.616 50.855 43.326 50.927 ;
     RECT  2.415 50.237 2.697 50.935 ;
     RECT  41.976 50.927 43.326 50.963 ;
     RECT  44.316 50.923 47.286 50.963 ;
     RECT  2.415 50.935 2.97 50.971 ;
     RECT  41.976 50.963 43.29 51.089 ;
     RECT  64.296 50.431 65.826 51.089 ;
     RECT  74.124 50.971 74.142 51.089 ;
     RECT  41.976 51.089 43.074 51.125 ;
     RECT  64.296 51.089 65.718 51.125 ;
     RECT  44.424 50.963 47.286 51.149 ;
     RECT  2.34 50.971 3.15 51.161 ;
     RECT  44.964 51.149 47.286 51.161 ;
     RECT  67.215 50.819 67.914 51.197 ;
     RECT  2.415 51.161 3.15 51.259 ;
     RECT  3.888 50.693 5.058 51.259 ;
     RECT  42.084 51.125 43.074 51.293 ;
     RECT  45 51.161 47.286 51.293 ;
     RECT  48.06 50.359 56.697 51.307 ;
     RECT  2.415 51.259 5.058 51.359 ;
     RECT  74.016 51.205 74.034 51.359 ;
     RECT  83.415 50.279 83.934 51.359 ;
     RECT  42.084 51.293 42.966 51.395 ;
     RECT  45.288 51.293 47.286 51.395 ;
     RECT  57.672 51.331 57.69 51.475 ;
     RECT  83.415 51.359 83.862 51.475 ;
     RECT  42.156 51.395 42.894 51.503 ;
     RECT  45.615 51.395 47.286 51.511 ;
     RECT  48.06 51.307 56.862 51.511 ;
     RECT  57.672 51.475 57.906 51.511 ;
     RECT  45.615 51.511 57.906 51.539 ;
     RECT  64.296 51.125 65.322 51.547 ;
     RECT  6.768 51.511 6.786 51.601 ;
     RECT  42.192 51.503 42.894 51.629 ;
     RECT  45.615 51.539 55.35 51.629 ;
     RECT  63.72 51.547 65.322 51.629 ;
     RECT  82.872 51.475 83.862 51.629 ;
     RECT  56.088 51.539 57.906 51.701 ;
     RECT  6.768 51.601 6.822 51.737 ;
     RECT  56.088 51.701 56.79 51.773 ;
     RECT  57.6 51.701 57.906 51.781 ;
     RECT  56.088 51.773 56.697 51.809 ;
     RECT  63.72 51.629 64.566 51.821 ;
     RECT  84.888 50.875 84.906 51.883 ;
     RECT  2.415 51.359 4.554 51.899 ;
     RECT  45.615 51.629 55.314 51.899 ;
     RECT  64.404 51.821 64.566 51.899 ;
     RECT  45.615 51.899 47.466 51.971 ;
     RECT  3.996 51.899 4.554 52.043 ;
     RECT  65.304 51.629 65.322 52.051 ;
     RECT  73.908 52.051 73.926 52.141 ;
     RECT  48.204 51.899 52.578 52.169 ;
     RECT  65.304 52.051 65.502 52.169 ;
     RECT  65.304 52.169 65.322 52.205 ;
     RECT  84.852 51.883 84.906 52.241 ;
     RECT  45.615 51.971 47.394 52.277 ;
     RECT  48.204 52.169 52.47 52.277 ;
     RECT  6.804 51.737 6.822 52.285 ;
     RECT  83.376 51.629 83.862 52.285 ;
     RECT  45.615 52.277 47.286 52.313 ;
     RECT  83.376 52.285 83.934 52.321 ;
     RECT  10.8 52.249 10.818 52.349 ;
     RECT  59.4 52.321 59.418 52.411 ;
     RECT  5.256 52.321 5.274 52.439 ;
     RECT  48.204 52.277 52.182 52.439 ;
     RECT  64.548 51.899 64.566 52.439 ;
     RECT  73.8 52.141 73.926 52.439 ;
     RECT  48.204 52.439 52.038 52.475 ;
     RECT  73.8 52.439 73.818 52.475 ;
     RECT  61.815 50.621 62.097 52.483 ;
     RECT  66.276 52.321 66.294 52.483 ;
     RECT  66.276 52.483 66.366 52.511 ;
     RECT  57.6 51.781 58.158 52.555 ;
     RECT  6.804 52.285 6.966 52.591 ;
     RECT  59.4 52.411 59.562 52.591 ;
     RECT  71.172 52.483 71.19 52.591 ;
     RECT  0.108 51.595 0.126 52.619 ;
     RECT  61.815 52.483 62.73 52.709 ;
     RECT  66.348 52.511 66.366 52.709 ;
     RECT  83.376 52.321 84.042 52.753 ;
     RECT  6.12 52.591 6.966 52.789 ;
     RECT  56.415 51.809 56.697 52.789 ;
     RECT  48.204 52.475 52.002 52.795 ;
     RECT  56.088 52.789 56.697 52.825 ;
     RECT  57.6 52.555 58.59 52.825 ;
     RECT  56.088 52.825 58.59 52.829 ;
     RECT  59.364 52.591 59.886 52.861 ;
     RECT  82.656 52.753 84.042 52.861 ;
     RECT  5.832 52.789 6.966 52.889 ;
     RECT  82.548 52.861 84.042 52.889 ;
     RECT  3.996 52.043 4.482 52.979 ;
     RECT  6.444 52.889 6.966 52.979 ;
     RECT  53.316 51.899 55.314 52.979 ;
     RECT  59.256 52.861 60.138 52.979 ;
     RECT  71.172 52.591 71.406 52.979 ;
     RECT  82.548 52.889 82.674 52.979 ;
     RECT  56.088 52.829 58.266 52.981 ;
     RECT  2.415 51.899 3.114 52.987 ;
     RECT  3.996 52.979 4.374 52.987 ;
     RECT  6.804 52.979 6.966 52.987 ;
     RECT  7.815 50.819 8.097 52.987 ;
     RECT  45.615 52.313 47.25 52.987 ;
     RECT  2.415 52.987 4.374 53.015 ;
     RECT  59.256 52.979 59.274 53.015 ;
     RECT  60.12 52.979 60.138 53.015 ;
     RECT  82.548 52.979 82.566 53.015 ;
     RECT  85.464 52.363 85.482 53.015 ;
     RECT  55.872 52.981 58.266 53.021 ;
     RECT  53.316 52.979 54.702 53.024 ;
     RECT  45.576 52.987 47.25 53.035 ;
     RECT  48.024 52.795 52.002 53.035 ;
     RECT  53.316 53.024 54.522 53.131 ;
     RECT  6.804 52.987 8.097 53.321 ;
     RECT  45.576 53.035 52.002 53.357 ;
     RECT  45.615 53.357 52.002 53.365 ;
     RECT  70.668 53.131 70.758 53.393 ;
     RECT  83.415 52.889 84.042 53.393 ;
     RECT  2.415 53.015 3.906 53.419 ;
     RECT  10.8 53.329 10.818 53.429 ;
     RECT  83.415 53.393 83.97 53.519 ;
     RECT  7.092 53.321 8.097 53.555 ;
     RECT  2.088 53.419 3.906 53.591 ;
     RECT  45.615 53.365 52.038 53.599 ;
     RECT  52.812 53.131 54.522 53.599 ;
     RECT  45.615 53.599 54.522 53.789 ;
     RECT  56.088 53.021 58.266 53.789 ;
     RECT  45.615 53.789 52.326 53.825 ;
     RECT  83.415 53.519 83.898 53.861 ;
     RECT  2.415 53.591 3.906 53.905 ;
     RECT  53.496 53.789 54.522 53.905 ;
     RECT  42.768 51.629 42.894 53.933 ;
     RECT  56.415 53.789 58.266 54.031 ;
     RECT  59.292 53.941 59.31 54.031 ;
     RECT  53.496 53.905 54.918 54.059 ;
     RECT  70.308 53.671 70.326 54.059 ;
     RECT  82.62 54.031 82.638 54.067 ;
     RECT  61.815 52.709 62.097 54.103 ;
     RECT  45.615 53.825 52.11 54.125 ;
     RECT  2.415 53.905 3.978 54.131 ;
     RECT  5.148 53.899 5.166 54.131 ;
     RECT  2.415 54.131 3.834 54.329 ;
     RECT  6.156 54.031 6.174 54.329 ;
     RECT  48.672 54.125 52.11 54.329 ;
     RECT  7.38 53.555 8.097 54.331 ;
     RECT  2.415 54.329 3.654 54.365 ;
     RECT  82.152 54.067 82.638 54.365 ;
     RECT  60.156 54.301 60.174 54.379 ;
     RECT  39.708 50.855 40.698 54.409 ;
     RECT  56.415 54.031 59.31 54.413 ;
     RECT  39.42 54.409 40.698 54.445 ;
     RECT  53.604 54.059 54.918 54.445 ;
     RECT  60.156 54.379 60.246 54.445 ;
     RECT  61.2 54.103 62.097 54.445 ;
     RECT  60.156 54.445 62.097 54.473 ;
     RECT  7.2 54.331 8.097 54.481 ;
     RECT  59.22 54.413 59.31 54.571 ;
     RECT  6.084 54.481 6.102 54.599 ;
     RECT  60.228 54.473 62.097 54.599 ;
     RECT  70.56 54.211 70.578 54.599 ;
     RECT  7.092 54.481 8.097 54.635 ;
     RECT  82.08 54.481 82.098 54.635 ;
     RECT  53.604 54.445 55.134 54.658 ;
     RECT  56.415 54.413 58.302 54.671 ;
     RECT  56.415 54.671 57.834 54.701 ;
     RECT  59.22 54.571 59.346 54.707 ;
     RECT  60.228 54.599 60.246 54.749 ;
     RECT  39.168 54.445 40.698 54.751 ;
     RECT  53.712 54.658 55.134 54.763 ;
     RECT  39.024 54.751 40.698 54.841 ;
     RECT  84.888 53.896 84.906 54.859 ;
     RECT  53.712 54.763 55.638 54.869 ;
     RECT  71.856 54.751 71.874 54.869 ;
     RECT  84.888 54.859 85.482 54.905 ;
     RECT  48.78 54.329 52.11 54.941 ;
     RECT  53.712 54.869 55.242 54.941 ;
     RECT  83.415 53.861 83.862 54.985 ;
     RECT  74.628 54.841 74.646 55.013 ;
     RECT  36.144 37.291 36.162 55.021 ;
     RECT  61.056 54.599 62.097 55.021 ;
     RECT  63.108 54.985 63.126 55.021 ;
     RECT  48.78 54.941 52.038 55.111 ;
     RECT  57.816 54.701 57.834 55.139 ;
     RECT  45.615 54.125 47.61 55.141 ;
     RECT  48.42 55.111 52.038 55.141 ;
     RECT  38.916 54.841 40.698 55.147 ;
     RECT  72.615 50.009 72.897 55.147 ;
     RECT  53.748 54.941 55.242 55.175 ;
     RECT  61.056 55.021 63.126 55.181 ;
     RECT  45.615 55.141 52.038 55.211 ;
     RECT  38.916 55.147 41.022 55.219 ;
     RECT  36.144 55.021 36.27 55.243 ;
     RECT  37.008 55.219 37.026 55.243 ;
     RECT  37.944 39.749 37.962 55.243 ;
     RECT  2.415 54.365 3.294 55.255 ;
     RECT  36.036 55.243 36.27 55.255 ;
     RECT  37.008 55.243 37.962 55.255 ;
     RECT  63.036 55.181 63.126 55.255 ;
     RECT  58.716 55.183 58.734 55.283 ;
     RECT  2.415 55.255 3.69 55.291 ;
     RECT  38.772 55.219 41.022 55.291 ;
     RECT  83.232 54.985 83.862 55.291 ;
     RECT  45.615 55.211 51.966 55.409 ;
     RECT  54.36 55.175 55.242 55.409 ;
     RECT  61.056 55.181 62.097 55.409 ;
     RECT  36.036 55.255 37.962 55.417 ;
     RECT  45.615 55.409 47.034 55.445 ;
     RECT  47.844 55.409 51.966 55.445 ;
     RECT  54.36 55.409 54.378 55.445 ;
     RECT  83.232 55.291 83.898 55.445 ;
     RECT  83.232 55.445 83.862 55.453 ;
     RECT  49.284 55.445 49.338 55.481 ;
     RECT  45.615 55.445 46.818 55.517 ;
     RECT  61.524 55.409 62.097 55.553 ;
     RECT  82.656 55.453 83.862 55.553 ;
     RECT  34.815 48.929 35.097 55.561 ;
     RECT  36.036 55.417 38.034 55.561 ;
     RECT  72.615 55.147 72.954 55.561 ;
     RECT  2.304 55.291 3.69 55.589 ;
     RECT  49.284 55.481 49.302 55.589 ;
     RECT  50.184 55.445 51.966 55.589 ;
     RECT  63.036 55.255 63.63 55.589 ;
     RECT  0.108 54.811 0.126 55.675 ;
     RECT  47.844 55.445 48.438 55.679 ;
     RECT  50.184 55.589 50.274 55.679 ;
     RECT  55.224 55.409 55.242 55.679 ;
     RECT  72.615 55.561 73.062 55.679 ;
     RECT  50.256 55.679 50.274 55.715 ;
     RECT  38.772 55.291 41.562 55.795 ;
     RECT  0.108 55.675 0.162 55.805 ;
     RECT  38.772 55.795 41.67 55.831 ;
     RECT  2.376 55.589 3.69 55.859 ;
     RECT  51.012 55.589 51.297 55.859 ;
     RECT  63.36 55.589 63.63 55.867 ;
     RECT  84.888 54.905 84.906 55.867 ;
     RECT  38.772 55.831 42.03 55.949 ;
     RECT  45.615 55.517 46.746 55.949 ;
     RECT  48.204 55.679 48.222 55.949 ;
     RECT  34.815 55.561 38.034 55.957 ;
     RECT  84.888 55.867 85.482 55.985 ;
     RECT  34.632 55.957 38.034 55.993 ;
     RECT  46.728 55.949 46.746 56.093 ;
     RECT  5.724 56.029 5.742 56.101 ;
     RECT  33.66 56.029 33.678 56.101 ;
     RECT  34.452 55.993 38.034 56.101 ;
     RECT  61.815 55.553 62.097 56.101 ;
     RECT  63.36 55.867 63.774 56.101 ;
     RECT  33.66 56.101 38.034 56.129 ;
     RECT  32.364 55.723 32.382 56.191 ;
     RECT  55.44 55.795 55.458 56.219 ;
     RECT  41.976 55.949 42.03 56.227 ;
     RECT  42.876 53.933 42.894 56.227 ;
     RECT  60.156 56.191 60.174 56.255 ;
     RECT  63.36 56.101 64.098 56.255 ;
     RECT  32.328 56.191 32.382 56.299 ;
     RECT  0.108 55.805 0.126 56.333 ;
     RECT  58.68 56.227 58.698 56.363 ;
     RECT  2.415 55.859 3.69 56.371 ;
     RECT  4.5 56.299 4.518 56.371 ;
     RECT  63.36 56.255 63.918 56.399 ;
     RECT  2.415 56.371 4.518 56.443 ;
     RECT  5.724 56.101 6.03 56.443 ;
     RECT  32.328 56.299 32.418 56.461 ;
     RECT  41.976 56.227 42.894 56.461 ;
     RECT  82.908 55.553 83.862 56.461 ;
     RECT  38.772 55.949 41.094 56.477 ;
     RECT  61.815 56.101 62.586 56.489 ;
     RECT  63.9 56.399 63.918 56.489 ;
     RECT  32.328 56.461 32.814 56.533 ;
     RECT  60.912 56.371 60.93 56.539 ;
     RECT  82.908 56.461 83.898 56.561 ;
     RECT  30.816 56.533 30.834 56.569 ;
     RECT  32.112 56.533 32.814 56.605 ;
     RECT  2.415 56.443 4.59 56.633 ;
     RECT  2.415 56.633 2.79 56.641 ;
     RECT  30.528 56.569 30.834 56.641 ;
     RECT  32.076 56.605 32.814 56.641 ;
     RECT  60.516 56.539 60.93 56.641 ;
     RECT  61.815 56.489 62.478 56.641 ;
     RECT  82.908 56.561 83.862 56.669 ;
     RECT  60.516 56.641 62.478 56.759 ;
     RECT  60.516 56.759 62.298 56.795 ;
     RECT  30.528 56.641 31.194 56.803 ;
     RECT  32.076 56.641 32.886 56.803 ;
     RECT  60.516 56.795 60.786 56.813 ;
     RECT  30.528 56.803 32.886 56.839 ;
     RECT  33.66 56.129 37.962 56.839 ;
     RECT  7.815 54.635 8.097 56.875 ;
     RECT  29.415 2.413 29.697 56.875 ;
     RECT  3.636 56.633 4.59 56.911 ;
     RECT  29.415 56.875 29.754 56.911 ;
     RECT  30.528 56.839 37.962 56.911 ;
     RECT  39.492 56.477 41.094 56.911 ;
     RECT  41.976 56.461 43.542 56.911 ;
     RECT  60.66 56.813 60.786 56.939 ;
     RECT  5.724 56.443 6.246 57.029 ;
     RECT  7.2 56.875 8.097 57.029 ;
     RECT  60.66 56.939 60.678 57.029 ;
     RECT  39.492 56.911 43.542 57.037 ;
     RECT  39.492 57.037 44.118 57.073 ;
     RECT  74.664 57.001 74.682 57.101 ;
     RECT  3.636 56.911 4.734 57.145 ;
     RECT  26.856 57.109 26.874 57.145 ;
     RECT  3.636 57.145 5.454 57.173 ;
     RECT  39.492 57.073 44.226 57.181 ;
     RECT  26.784 57.145 26.874 57.209 ;
     RECT  70.704 57.073 70.722 57.209 ;
     RECT  82.656 57.001 82.674 57.209 ;
     RECT  26.784 57.209 26.802 57.299 ;
     RECT  7.236 57.029 8.097 57.371 ;
     RECT  2.304 56.641 2.79 57.379 ;
     RECT  3.636 57.173 4.518 57.379 ;
     RECT  29.415 56.911 37.962 57.407 ;
     RECT  33.876 57.407 37.962 57.451 ;
     RECT  2.304 57.379 4.518 57.479 ;
     RECT  33.876 57.451 38.43 57.479 ;
     RECT  34.056 57.479 38.43 57.541 ;
     RECT  39.492 57.181 44.586 57.541 ;
     RECT  48.996 56.461 49.014 57.613 ;
     RECT  0.54 57.541 0.558 57.629 ;
     RECT  34.056 57.541 44.586 57.641 ;
     RECT  61.815 56.795 62.298 57.685 ;
     RECT  48.996 57.613 49.158 57.721 ;
     RECT  45.615 55.949 45.897 57.811 ;
     RECT  5.436 57.173 5.454 57.839 ;
     RECT  39.708 57.641 44.586 57.839 ;
     RECT  39.708 57.839 43.254 57.875 ;
     RECT  39.708 57.875 41.346 57.911 ;
     RECT  44.1 57.839 44.586 57.919 ;
     RECT  45.36 57.811 45.897 57.919 ;
     RECT  82.44 57.847 82.458 57.919 ;
     RECT  34.056 57.641 38.898 57.947 ;
     RECT  82.224 57.919 82.458 57.991 ;
     RECT  83.415 56.669 83.862 57.991 ;
     RECT  6.84 57.847 6.858 58.019 ;
     RECT  44.1 57.919 45.897 58.081 ;
     RECT  0.108 57.931 0.126 58.109 ;
     RECT  42.12 57.875 43.254 58.109 ;
     RECT  44.1 58.081 46.278 58.109 ;
     RECT  48.276 57.721 49.158 58.109 ;
     RECT  61.815 57.685 62.334 58.109 ;
     RECT  48.996 58.109 49.158 58.123 ;
     RECT  45.36 58.109 46.278 58.145 ;
     RECT  80.892 57.991 80.91 58.145 ;
     RECT  43.236 58.109 43.254 58.157 ;
     RECT  44.316 58.109 44.622 58.157 ;
     RECT  47.34 58.117 47.358 58.157 ;
     RECT  82.116 57.991 83.862 58.225 ;
     RECT  78.015 49.505 78.297 58.261 ;
     RECT  67.215 51.197 67.497 58.351 ;
     RECT  78.015 58.261 78.678 58.351 ;
     RECT  84.888 55.985 84.906 58.363 ;
     RECT  42.48 58.109 42.498 58.379 ;
     RECT  65.052 58.261 65.07 58.379 ;
     RECT  38.844 57.947 38.898 58.387 ;
     RECT  39.708 57.911 41.31 58.387 ;
     RECT  26.784 58.225 26.802 58.451 ;
     RECT  78.015 58.351 78.75 58.451 ;
     RECT  84.888 58.363 85.482 58.451 ;
     RECT  66.708 58.351 67.497 58.523 ;
     RECT  48.996 58.123 49.41 58.531 ;
     RECT  6.804 58.423 6.822 58.559 ;
     RECT  29.415 57.407 33.138 58.621 ;
     RECT  34.056 57.947 38.034 58.621 ;
     RECT  44.604 58.157 44.622 58.649 ;
     RECT  45.54 58.145 46.278 58.649 ;
     RECT  48.996 58.531 49.59 58.651 ;
     RECT  48.996 58.651 49.626 58.685 ;
     RECT  82.116 58.225 84.042 58.693 ;
     RECT  45.615 58.649 46.278 58.729 ;
     RECT  49.176 58.685 49.626 58.729 ;
     RECT  82.08 58.693 84.042 58.765 ;
     RECT  2.415 57.479 4.518 58.801 ;
     RECT  63.36 58.657 63.378 58.801 ;
     RECT  45.615 58.729 46.782 58.829 ;
     RECT  2.415 58.801 4.734 58.919 ;
     RECT  63.36 58.801 63.522 58.919 ;
     RECT  63.36 58.919 63.378 58.955 ;
     RECT  29.415 58.621 38.034 59.035 ;
     RECT  38.844 58.387 41.31 59.035 ;
     RECT  49.176 58.729 49.77 59.071 ;
     RECT  29.415 59.035 41.31 59.117 ;
     RECT  45.615 58.829 46.206 59.189 ;
     RECT  81.792 58.765 84.042 59.189 ;
     RECT  29.415 59.117 38.214 59.213 ;
     RECT  85.464 58.451 85.482 59.225 ;
     RECT  3.78 58.919 4.734 59.233 ;
     RECT  49.176 59.071 50.13 59.297 ;
     RECT  50.112 59.297 50.13 59.459 ;
     RECT  29.415 59.213 33.642 59.495 ;
     RECT  82.872 59.189 84.042 59.531 ;
     RECT  67.215 58.523 67.497 59.563 ;
     RECT  29.415 59.495 33.534 59.603 ;
     RECT  47.664 59.233 47.682 59.605 ;
     RECT  3.78 59.233 5.238 59.611 ;
     RECT  47.088 59.605 47.682 59.611 ;
     RECT  47.088 59.611 47.826 59.645 ;
     RECT  49.176 59.297 49.338 59.645 ;
     RECT  3.78 59.611 5.706 59.701 ;
     RECT  81.792 59.189 82.098 59.701 ;
     RECT  3.78 59.701 6.066 59.729 ;
     RECT  6.84 59.611 6.858 59.729 ;
     RECT  67.215 59.563 67.59 59.741 ;
     RECT  47.448 59.645 47.826 59.765 ;
     RECT  3.6 59.737 3.618 59.789 ;
     RECT  4.464 59.729 6.066 59.789 ;
     RECT  6.048 59.789 6.066 59.837 ;
     RECT  53.424 58.963 53.442 59.851 ;
     RECT  54.36 58.657 54.378 59.851 ;
     RECT  49.32 59.645 49.338 59.909 ;
     RECT  34.776 59.213 38.214 59.947 ;
     RECT  38.952 59.117 41.31 59.947 ;
     RECT  29.415 59.603 33.462 59.999 ;
     RECT  34.776 59.947 41.31 59.999 ;
     RECT  65.664 59.881 65.682 59.999 ;
     RECT  67.215 59.741 67.497 60.007 ;
     RECT  56.415 54.701 56.697 60.079 ;
     RECT  66.708 60.007 67.497 60.107 ;
     RECT  34.776 59.999 38.034 60.115 ;
     RECT  38.772 59.999 41.31 60.151 ;
     RECT  53.424 59.851 54.378 60.151 ;
     RECT  55.908 60.079 56.697 60.151 ;
     RECT  81.36 59.701 82.098 60.151 ;
     RECT  82.872 59.531 83.898 60.151 ;
     RECT  38.772 60.151 42.03 60.179 ;
     RECT  47.448 59.765 47.466 60.269 ;
     RECT  55.8 60.151 56.697 60.269 ;
     RECT  53.424 60.151 54.666 60.305 ;
     RECT  53.748 60.305 54.378 60.341 ;
     RECT  41.976 60.179 42.03 60.377 ;
     RECT  80.244 60.277 80.262 60.385 ;
     RECT  81.36 60.151 83.898 60.385 ;
     RECT  4.464 59.789 4.878 60.413 ;
     RECT  80.244 60.385 84.042 60.413 ;
     RECT  34.704 60.115 38.034 60.419 ;
     RECT  4.464 60.413 4.482 60.539 ;
     RECT  38.916 60.179 41.13 60.539 ;
     RECT  60.732 60.277 60.75 60.547 ;
     RECT  40.215 60.539 40.986 60.575 ;
     RECT  60.408 60.547 60.75 60.575 ;
     RECT  40.215 60.575 40.698 60.611 ;
     RECT  38.916 60.539 39.042 60.647 ;
     RECT  47.376 60.385 47.394 60.655 ;
     RECT  2.415 58.919 2.697 60.691 ;
     RECT  79.272 60.427 79.29 60.691 ;
     RECT  80.244 60.413 82.314 60.691 ;
     RECT  38.916 60.647 38.934 60.719 ;
     RECT  41.976 60.377 41.994 60.719 ;
     RECT  34.776 60.419 38.034 60.809 ;
     RECT  60.408 60.575 60.426 60.809 ;
     RECT  29.415 59.999 33.066 60.853 ;
     RECT  29.415 60.853 33.138 60.881 ;
     RECT  30.708 60.881 33.138 60.917 ;
     RECT  74.664 60.511 74.682 60.917 ;
     RECT  79.272 60.691 82.314 60.961 ;
     RECT  30.708 60.917 31.194 60.989 ;
     RECT  31.932 60.917 33.138 60.989 ;
     RECT  34.776 60.809 37.89 60.989 ;
     RECT  47.304 60.655 47.394 61.003 ;
     RECT  30.708 60.989 30.942 61.079 ;
     RECT  36.9 60.989 37.89 61.079 ;
     RECT  47.304 61.003 47.682 61.079 ;
     RECT  79.2 60.961 82.314 61.079 ;
     RECT  29.415 60.881 29.862 61.115 ;
     RECT  0.108 61.003 0.126 61.133 ;
     RECT  2.415 60.691 2.862 61.133 ;
     RECT  32.076 60.989 33.138 61.151 ;
     RECT  48.42 61.051 48.438 61.151 ;
     RECT  34.776 60.989 36.162 61.187 ;
     RECT  47.664 61.079 47.682 61.195 ;
     RECT  56.34 60.269 56.697 61.231 ;
     RECT  32.508 61.151 33.138 61.349 ;
     RECT  36.9 61.079 37.638 61.349 ;
     RECT  47.664 61.195 48.33 61.349 ;
     RECT  78.015 58.451 78.297 61.357 ;
     RECT  79.2 61.079 79.326 61.357 ;
     RECT  47.664 61.349 47.682 61.385 ;
     RECT  78.015 61.357 79.326 61.457 ;
     RECT  36.9 61.349 37.602 61.493 ;
     RECT  80.1 61.079 82.314 61.501 ;
     RECT  83.232 60.413 84.042 61.501 ;
     RECT  36.9 61.493 37.098 61.529 ;
     RECT  56.34 61.231 56.754 61.619 ;
     RECT  79.2 61.457 79.326 61.619 ;
     RECT  80.1 61.501 84.042 61.619 ;
     RECT  81.54 61.619 84.042 61.691 ;
     RECT  37.08 61.529 37.098 61.889 ;
     RECT  49.176 61.501 49.194 61.889 ;
     RECT  79.308 61.619 79.326 61.889 ;
     RECT  34.776 61.187 35.097 61.897 ;
     RECT  80.1 61.619 80.298 61.925 ;
     RECT  80.28 61.925 80.298 62.033 ;
     RECT  36.144 61.187 36.162 62.159 ;
     RECT  81.54 61.691 81.558 62.159 ;
     RECT  51.015 55.859 51.297 62.167 ;
     RECT  34.74 61.897 35.097 62.275 ;
     RECT  49.608 62.005 49.626 62.339 ;
     RECT  2.415 61.133 2.697 62.387 ;
     RECT  7.815 57.371 8.097 62.387 ;
     RECT  13.215 33.965 13.497 62.387 ;
     RECT  18.615 2.413 18.897 62.387 ;
     RECT  24.015 2.413 24.297 62.387 ;
     RECT  29.415 61.115 29.697 62.387 ;
     RECT  40.215 60.611 40.497 62.387 ;
     RECT  45.615 59.189 45.897 62.387 ;
     RECT  50.472 62.167 51.297 62.387 ;
     RECT  61.815 58.109 62.097 62.387 ;
     RECT  67.215 60.107 67.497 62.387 ;
     RECT  72.615 55.679 72.897 62.387 ;
     RECT  78.015 61.457 78.297 62.387 ;
     RECT  34.74 62.275 35.514 62.429 ;
     RECT  50.472 62.387 51.105 62.429 ;
     RECT  83.415 61.691 84.042 62.429 ;
     RECT  83.415 62.429 83.898 62.501 ;
     RECT  50.58 62.429 51.105 62.573 ;
     RECT  83.415 62.501 83.79 62.573 ;
     RECT  32.148 62.545 32.166 62.621 ;
     RECT  34.815 62.429 35.334 62.621 ;
     RECT  2.415 62.387 2.505 62.657 ;
     RECT  7.815 62.387 7.905 62.657 ;
     RECT  13.215 62.387 13.305 62.657 ;
     RECT  18.615 62.387 18.705 62.657 ;
     RECT  24.015 62.387 24.105 62.657 ;
     RECT  29.415 62.387 29.505 62.657 ;
     RECT  34.815 62.621 34.905 62.657 ;
     RECT  40.215 62.387 40.305 62.657 ;
     RECT  45.615 62.387 45.705 62.657 ;
     RECT  50.616 62.573 51.105 62.657 ;
     RECT  56.415 61.619 56.754 62.657 ;
     RECT  61.815 62.387 61.905 62.657 ;
     RECT  67.215 62.387 67.305 62.657 ;
     RECT  72.615 62.387 72.705 62.657 ;
     RECT  78.015 62.387 78.105 62.657 ;
     RECT  83.415 62.573 83.505 62.657 ;
     RECT  56.736 62.657 56.754 63.245 ;
     RECT  50.616 62.657 50.634 63.869 ;
    LAYER M4 ;
     RECT  0.06 61.008 0.097 61.032 ;
     RECT  0.06 2.4 0.137 58.104 ;
     RECT  0.097 61.008 0.137 61.128 ;
     RECT  0.137 2.4 0.173 57.96 ;
     RECT  0.173 2.4 2.408 42.792 ;
     RECT  0.173 43.824 2.408 57.96 ;
     RECT  0.137 61.104 2.408 61.128 ;
     RECT  2.408 2.148 2.512 62.652 ;
     RECT  2.512 2.418 2.704 62.382 ;
     RECT  2.704 11.184 2.765 14.088 ;
     RECT  2.704 27.888 2.801 36.264 ;
     RECT  2.801 30.672 2.837 36.264 ;
     RECT  2.704 43.824 2.873 46.056 ;
     RECT  2.704 61.104 2.873 61.128 ;
     RECT  2.765 13.632 2.945 14.088 ;
     RECT  2.704 15.264 2.945 22.824 ;
     RECT  2.945 15.696 3.125 20.472 ;
     RECT  2.704 49.728 3.125 53.928 ;
     RECT  2.873 43.824 3.161 45.144 ;
     RECT  2.801 27.888 3.269 29.4 ;
     RECT  2.837 30.672 3.333 31.848 ;
     RECT  2.704 4.224 3.377 6.216 ;
     RECT  3.125 18.72 3.377 20.472 ;
     RECT  2.837 33.024 3.377 36.264 ;
     RECT  2.704 55.68 3.377 56.424 ;
     RECT  2.765 11.184 3.413 12.552 ;
     RECT  3.269 28.8 3.449 29.4 ;
     RECT  2.945 21.648 3.484 22.824 ;
     RECT  2.704 47.04 3.485 48.456 ;
     RECT  2.704 24.24 3.557 24.264 ;
     RECT  3.125 51.264 3.701 53.928 ;
     RECT  3.125 15.696 3.737 17.352 ;
     RECT  2.704 37.632 3.737 37.896 ;
     RECT  2.704 26.592 3.769 26.712 ;
     RECT  2.704 42.768 3.769 42.792 ;
     RECT  3.377 56.4 3.769 56.424 ;
     RECT  2.704 57.936 3.769 58.632 ;
     RECT  2.704 2.832 3.773 2.856 ;
     RECT  3.377 33.024 3.773 35.928 ;
     RECT  3.769 56.4 3.809 58.632 ;
     RECT  3.377 19.104 3.827 20.472 ;
     RECT  3.773 33.024 3.827 35.304 ;
     RECT  2.704 39.024 3.877 40.44 ;
     RECT  2.704 7.44 3.925 9.384 ;
     RECT  3.884 10.56 3.925 10.584 ;
     RECT  3.769 42.048 3.925 42.984 ;
     RECT  2.945 14.064 3.949 14.088 ;
     RECT  3.485 47.04 3.949 47.736 ;
     RECT  3.925 7.44 3.971 10.584 ;
     RECT  3.925 41.616 3.971 42.984 ;
     RECT  3.161 44.64 3.971 45.144 ;
     RECT  3.809 56.448 3.971 58.632 ;
     RECT  3.769 26.16 3.973 26.712 ;
     RECT  3.973 26.16 4.019 26.808 ;
     RECT  3.377 4.224 4.025 5.88 ;
     RECT  3.971 7.44 4.025 8.328 ;
     RECT  3.971 9.36 4.025 9.672 ;
     RECT  3.827 19.104 4.025 20.04 ;
     RECT  3.827 33.024 4.025 34.68 ;
     RECT  3.877 38.64 4.025 40.44 ;
     RECT  3.701 51.792 4.025 53.928 ;
     RECT  3.971 56.448 4.025 57.816 ;
     RECT  3.949 13.68 4.061 14.088 ;
     RECT  4.025 52.848 4.067 53.928 ;
     RECT  4.067 52.848 4.108 52.872 ;
     RECT  4.025 51.792 4.128 51.816 ;
     RECT  3.413 11.664 4.241 12.552 ;
     RECT  4.025 33.6 4.241 34.68 ;
     RECT  4.241 33.984 4.259 34.68 ;
     RECT  4.019 26.592 4.277 26.808 ;
     RECT  3.125 49.728 4.309 50.184 ;
     RECT  4.259 34.416 4.313 34.68 ;
     RECT  4.309 49.728 4.319 50.568 ;
     RECT  3.449 28.8 4.345 29.304 ;
     RECT  3.484 21.648 4.357 22.344 ;
     RECT  4.025 19.104 4.417 19.128 ;
     RECT  4.345 28.512 4.429 29.304 ;
     RECT  3.333 30.672 4.457 31.656 ;
     RECT  3.971 44.64 4.457 44.904 ;
     RECT  4.025 7.44 4.46 7.512 ;
     RECT  4.319 49.44 4.499 50.568 ;
     RECT  3.737 17.328 4.529 17.352 ;
     RECT  4.46 7.392 4.547 7.512 ;
     RECT  4.061 13.68 4.547 13.704 ;
     RECT  4.457 30.672 4.565 30.696 ;
     RECT  3.971 41.616 4.565 42.792 ;
     RECT  4.025 56.448 4.601 57 ;
     RECT  4.241 11.952 4.673 12.552 ;
     RECT  4.025 4.512 5.141 5.88 ;
     RECT  4.417 18.576 5.177 19.128 ;
     RECT  4.357 21.6 5.177 22.344 ;
     RECT  4.429 28.8 5.177 29.304 ;
     RECT  4.067 53.904 5.177 53.928 ;
     RECT  4.025 38.64 5.213 39.528 ;
     RECT  4.547 7.44 5.285 7.512 ;
     RECT  4.565 41.616 5.357 42.168 ;
     RECT  4.025 9.648 5.363 9.672 ;
     RECT  3.737 37.632 5.429 37.656 ;
     RECT  5.141 5.184 5.537 5.88 ;
     RECT  2.704 59.76 5.573 59.784 ;
     RECT  3.949 46.752 5.645 47.736 ;
     RECT  5.537 5.856 5.681 5.88 ;
     RECT  4.499 50.16 5.681 50.568 ;
     RECT  5.357 42.096 5.749 42.168 ;
     RECT  4.673 11.952 5.753 11.976 ;
     RECT  5.285 7.44 5.897 7.464 ;
     RECT  5.845 30.72 5.932 30.744 ;
     RECT  5.645 46.752 5.996 47.064 ;
     RECT  5.213 38.64 6.037 38.664 ;
     RECT  5.929 40.8 6.083 40.824 ;
     RECT  5.749 42.096 6.083 42.792 ;
     RECT  5.996 46.176 6.083 47.064 ;
     RECT  5.852 49.536 6.083 49.56 ;
     RECT  6.037 38.16 6.105 38.664 ;
     RECT  4.601 56.976 6.109 57 ;
     RECT  6.109 56.448 6.257 57 ;
     RECT  5.317 10.848 6.293 10.872 ;
     RECT  4.993 45.024 6.293 45.048 ;
     RECT  6.236 22.752 6.323 22.776 ;
     RECT  3.737 15.696 6.329 15.72 ;
     RECT  4.277 26.784 6.365 26.808 ;
     RECT  6.105 38.16 6.473 38.184 ;
     RECT  5.177 18.576 6.517 18.6 ;
     RECT  6.083 42.096 6.545 42.168 ;
     RECT  6.517 18.576 6.563 19.368 ;
     RECT  6.476 20.544 6.563 20.568 ;
     RECT  5.177 21.6 6.829 21.672 ;
     RECT  6.793 52.368 6.901 52.392 ;
     RECT  6.563 19.344 7.808 19.368 ;
     RECT  6.829 21.504 7.808 21.672 ;
     RECT  5.177 28.8 7.808 29.256 ;
     RECT  4.313 34.656 7.808 34.68 ;
     RECT  6.545 42.144 7.808 42.168 ;
     RECT  6.083 46.752 7.808 47.064 ;
     RECT  5.681 50.544 7.808 50.568 ;
     RECT  6.901 52.368 7.808 53.256 ;
     RECT  6.901 54.336 7.808 54.36 ;
     RECT  6.257 56.448 7.808 56.472 ;
     RECT  7.808 2.148 7.912 62.652 ;
     RECT  7.912 2.418 8.104 62.382 ;
     RECT  8.104 34.464 8.243 34.68 ;
     RECT  8.104 36 8.243 36.024 ;
     RECT  8.104 29.232 8.381 29.256 ;
     RECT  8.104 21.6 10.825 21.624 ;
     RECT  10.825 21.504 10.865 21.624 ;
     RECT  8.243 34.464 12.901 34.488 ;
     RECT  12.901 33.936 12.908 34.488 ;
     RECT  8.104 42.144 13.045 42.168 ;
     RECT  10.865 21.504 13.208 21.528 ;
     RECT  12.908 33.6 13.208 34.488 ;
     RECT  13.045 42.144 13.208 43.032 ;
     RECT  8.104 46.752 13.208 47.064 ;
     RECT  13.208 2.148 13.312 62.652 ;
     RECT  13.312 2.418 13.504 62.382 ;
     RECT  13.504 21.6 14.821 21.624 ;
     RECT  14.821 21.504 14.861 21.624 ;
     RECT  14.861 21.504 18.608 21.528 ;
     RECT  13.504 33.552 18.608 33.576 ;
     RECT  13.504 43.008 18.608 43.032 ;
     RECT  13.504 46.752 18.608 47.064 ;
     RECT  18.608 2.148 18.712 62.652 ;
     RECT  18.712 2.418 18.904 62.382 ;
     RECT  18.904 21.6 22.813 21.624 ;
     RECT  22.813 21.408 22.853 21.624 ;
     RECT  22.853 21.408 24.008 21.432 ;
     RECT  18.904 33.552 24.008 33.576 ;
     RECT  18.904 43.008 24.008 43.032 ;
     RECT  18.904 46.752 24.008 47.064 ;
     RECT  24.008 2.148 24.112 62.652 ;
     RECT  24.112 2.418 24.304 62.382 ;
     RECT  24.304 43.008 26.593 43.032 ;
     RECT  24.304 21.408 27.053 21.432 ;
     RECT  24.304 33.552 27.061 33.576 ;
     RECT  26.593 42.768 27.107 43.032 ;
     RECT  27.053 21.408 27.137 21.72 ;
     RECT  27.137 21.408 27.395 21.672 ;
     RECT  27.395 21.648 28.573 21.672 ;
     RECT  28.573 21.408 29.408 21.672 ;
     RECT  27.061 32.784 29.408 33.576 ;
     RECT  27.107 43.008 29.408 43.032 ;
     RECT  24.304 46.752 29.408 47.064 ;
     RECT  29.408 2.148 29.512 62.652 ;
     RECT  29.512 2.418 29.704 62.382 ;
     RECT  29.704 56.88 29.843 58.344 ;
     RECT  29.843 57.264 30.733 58.344 ;
     RECT  30.757 64.656 30.899 64.68 ;
     RECT  30.733 57.264 30.917 58.68 ;
     RECT  29.704 59.76 31.061 59.784 ;
     RECT  30.917 57.264 31.669 58.44 ;
     RECT  31.669 57.024 31.885 58.44 ;
     RECT  31.417 60.144 32.173 60.168 ;
     RECT  30.853 62.592 32.177 62.616 ;
     RECT  31.885 57.024 32.195 58.68 ;
     RECT  32.195 57.024 32.429 58.488 ;
     RECT  32.173 59.712 32.537 60.168 ;
     RECT  32.429 57.264 32.825 58.488 ;
     RECT  32.537 59.712 33.257 59.736 ;
     RECT  32.825 57.264 33.365 57.288 ;
     RECT  32.825 58.464 34.021 58.488 ;
     RECT  34.021 57.6 34.117 58.488 ;
     RECT  33.649 56.4 34.333 56.424 ;
     RECT  32.821 61.008 34.645 61.032 ;
     RECT  34.117 57.6 34.765 59.208 ;
     RECT  34.645 60.384 34.765 61.032 ;
     RECT  29.704 21.408 34.808 21.432 ;
     RECT  29.704 32.784 34.808 33.576 ;
     RECT  29.704 43.008 34.808 43.032 ;
     RECT  29.704 46.752 34.808 47.064 ;
     RECT  34.333 56.304 34.808 56.424 ;
     RECT  34.765 57.6 34.808 61.032 ;
     RECT  34.808 2.148 34.912 62.652 ;
     RECT  34.912 2.418 35.104 62.616 ;
     RECT  35.077 64.656 35.219 64.68 ;
     RECT  35.104 62.592 35.345 62.616 ;
     RECT  35.104 57.888 35.453 59.592 ;
     RECT  35.453 57.936 35.561 59.592 ;
     RECT  35.561 57.936 35.597 58.728 ;
     RECT  36.205 56.4 36.62 56.424 ;
     RECT  35.104 60.576 36.637 60.6 ;
     RECT  36.62 56.4 36.661 56.904 ;
     RECT  35.597 58.128 36.661 58.728 ;
     RECT  36.661 56.4 36.677 58.728 ;
     RECT  36.677 56.88 36.707 58.728 ;
     RECT  36.707 57.6 37.145 58.728 ;
     RECT  35.104 32.784 37.331 33.576 ;
     RECT  35.104 55.248 37.389 55.272 ;
     RECT  37.285 29.52 37.433 29.544 ;
     RECT  36.637 60.576 37.573 60.984 ;
     RECT  37.573 60.144 37.619 60.984 ;
     RECT  37.717 37.584 37.859 37.608 ;
     RECT  38.149 6.288 38.221 6.312 ;
     RECT  37.145 57.6 38.444 58.392 ;
     RECT  38.444 57.6 38.473 59.112 ;
     RECT  37.619 60.144 38.473 60.168 ;
     RECT  38.221 5.424 38.477 6.312 ;
     RECT  38.473 57.6 38.531 60.168 ;
     RECT  38.365 4.224 38.581 4.248 ;
     RECT  38.437 29.376 38.617 29.4 ;
     RECT  37.285 30.576 38.617 30.6 ;
     RECT  38.477 5.424 38.627 6.168 ;
     RECT  38.581 3.936 38.668 4.248 ;
     RECT  38.581 7.392 38.689 7.416 ;
     RECT  37.465 8.544 38.689 8.568 ;
     RECT  37.897 27.216 38.761 27.24 ;
     RECT  38.689 7.392 38.797 8.568 ;
     RECT  38.797 7.392 38.837 9.048 ;
     RECT  38.668 4.128 38.869 4.248 ;
     RECT  38.257 36.96 38.905 37.224 ;
     RECT  38.869 4.128 38.909 4.296 ;
     RECT  38.761 27.12 38.941 27.24 ;
     RECT  38.905 36.912 39.013 37.224 ;
     RECT  38.909 4.224 39.017 4.296 ;
     RECT  39.013 36.912 39.157 37.32 ;
     RECT  38.627 6.096 39.197 6.168 ;
     RECT  38.531 59.952 39.337 60.168 ;
     RECT  38.837 8.544 39.349 9.048 ;
     RECT  39.157 36.576 39.373 37.32 ;
     RECT  38.941 27.12 39.409 28.008 ;
     RECT  38.761 56.448 39.409 56.472 ;
     RECT  39.404 14.4 39.445 14.424 ;
     RECT  37.813 39.552 39.548 39.576 ;
     RECT  39.548 39.552 39.553 39.816 ;
     RECT  39.553 39.264 39.589 39.816 ;
     RECT  37.285 51.072 39.589 51.096 ;
     RECT  38.837 7.392 39.733 7.512 ;
     RECT  39.589 50.112 39.733 51.096 ;
     RECT  39.733 6.864 39.841 7.512 ;
     RECT  39.349 8.544 39.841 9.672 ;
     RECT  39.409 55.488 39.869 56.472 ;
     RECT  38.617 29.376 39.877 30.6 ;
     RECT  35.104 46.752 39.877 47.064 ;
     RECT  39.553 48.768 39.877 48.792 ;
     RECT  39.877 46.752 39.884 48.792 ;
     RECT  39.733 49.968 39.884 51.096 ;
     RECT  35.104 43.008 39.925 43.032 ;
     RECT  38.531 58.368 39.941 58.68 ;
     RECT  39.337 59.952 39.941 60.312 ;
     RECT  39.869 55.488 39.973 56.52 ;
     RECT  39.445 14.4 39.985 14.952 ;
     RECT  39.941 58.368 39.985 60.312 ;
     RECT  35.104 21.408 40.069 21.432 ;
     RECT  39.841 6.864 40.093 9.672 ;
     RECT  39.409 10.656 40.093 11.016 ;
     RECT  39.017 4.272 40.165 4.296 ;
     RECT  39.661 18.144 40.165 18.168 ;
     RECT  39.884 46.752 40.201 51.096 ;
     RECT  40.165 4.224 40.208 4.296 ;
     RECT  40.049 5.376 40.208 5.4 ;
     RECT  40.093 6.864 40.208 11.016 ;
     RECT  39.553 12 40.208 12.024 ;
     RECT  40.165 13.344 40.208 13.368 ;
     RECT  39.985 14.4 40.208 15.336 ;
     RECT  40.165 18.144 40.208 18.264 ;
     RECT  40.069 19.248 40.208 19.272 ;
     RECT  40.069 21.408 40.208 22.056 ;
     RECT  39.409 27.12 40.208 28.056 ;
     RECT  39.877 29.328 40.208 30.6 ;
     RECT  37.331 32.784 40.208 32.808 ;
     RECT  39.373 36.576 40.208 38.232 ;
     RECT  39.589 39.264 40.208 40.68 ;
     RECT  39.925 42.768 40.208 43.032 ;
     RECT  40.201 46.08 40.208 51.096 ;
     RECT  39.973 55.488 40.208 56.616 ;
     RECT  39.985 57.84 40.208 60.312 ;
     RECT  40.208 2.148 40.312 62.652 ;
     RECT  40.312 2.418 40.504 62.382 ;
     RECT  40.504 10.608 40.529 10.728 ;
     RECT  40.529 10.656 40.565 10.728 ;
     RECT  40.504 56.592 40.565 58.68 ;
     RECT  40.504 18.144 40.643 19.368 ;
     RECT  40.504 21.216 40.643 23.16 ;
     RECT  40.643 18.24 40.673 19.272 ;
     RECT  40.504 5.424 40.681 9.384 ;
     RECT  40.565 56.592 40.681 57.864 ;
     RECT  40.504 17.04 40.709 17.064 ;
     RECT  40.673 18.768 40.709 19.272 ;
     RECT  40.504 36.624 40.709 38.184 ;
     RECT  40.681 7.056 40.781 9.384 ;
     RECT  40.681 57.6 40.925 57.864 ;
     RECT  40.504 27.12 40.961 29.88 ;
     RECT  40.565 10.656 40.997 10.68 ;
     RECT  40.504 60.288 40.997 60.312 ;
     RECT  40.504 46.08 41.027 48.888 ;
     RECT  41.027 46.656 41.033 48.888 ;
     RECT  40.504 24.624 41.075 25.032 ;
     RECT  40.961 27.12 41.075 27.144 ;
     RECT  40.961 28.32 41.105 29.88 ;
     RECT  40.781 8.448 41.113 9.384 ;
     RECT  40.504 11.712 41.141 15.864 ;
     RECT  40.709 18.768 41.141 18.792 ;
     RECT  40.504 3.84 41.249 4.392 ;
     RECT  40.681 5.424 41.249 6.072 ;
     RECT  41.249 4.224 41.393 4.392 ;
     RECT  40.781 7.056 41.465 7.416 ;
     RECT  40.504 44.784 41.497 44.808 ;
     RECT  41.105 29.856 41.507 29.88 ;
     RECT  41.141 11.712 41.569 13.416 ;
     RECT  40.643 22.176 41.573 23.16 ;
     RECT  40.925 57.6 41.573 57.768 ;
     RECT  41.249 5.424 41.645 5.448 ;
     RECT  41.393 4.368 41.677 4.392 ;
     RECT  41.465 7.056 41.713 7.176 ;
     RECT  41.141 14.784 41.785 15.864 ;
     RECT  41.677 4.368 41.789 5.16 ;
     RECT  41.713 6.912 41.861 7.176 ;
     RECT  41.573 57.6 41.933 57.672 ;
     RECT  41.105 28.32 42.001 28.824 ;
     RECT  41.789 4.368 42.041 4.392 ;
     RECT  40.504 50.112 42.073 50.76 ;
     RECT  41.497 44.736 42.109 44.808 ;
     RECT  41.569 11.52 42.113 13.416 ;
     RECT  41.113 9.36 42.145 9.384 ;
     RECT  41.821 10.464 42.145 10.488 ;
     RECT  42.113 11.52 42.149 12.552 ;
     RECT  42.149 12 42.185 12.552 ;
     RECT  41.861 7.152 42.221 7.176 ;
     RECT  41.933 57.6 42.221 57.624 ;
     RECT  42.001 27.984 42.253 28.824 ;
     RECT  42.073 50.112 42.257 51.384 ;
     RECT  42.145 9.36 42.293 10.488 ;
     RECT  42.293 9.36 42.329 9.576 ;
     RECT  42.185 12.528 42.329 12.552 ;
     RECT  42.469 34.512 42.524 34.536 ;
     RECT  40.504 40.656 42.541 40.68 ;
     RECT  40.504 32.784 42.565 32.808 ;
     RECT  42.565 31.872 42.613 32.808 ;
     RECT  42.524 34.032 42.613 34.536 ;
     RECT  41.785 14.784 42.617 16.152 ;
     RECT  41.033 46.752 42.649 48.888 ;
     RECT  40.709 36.624 42.717 37.896 ;
     RECT  42.253 27.888 42.721 28.824 ;
     RECT  42.257 50.112 42.725 51.288 ;
     RECT  42.717 36.864 42.757 37.896 ;
     RECT  42.649 38.976 42.757 39 ;
     RECT  42.541 40.608 42.761 40.68 ;
     RECT  41.075 25.008 42.793 25.032 ;
     RECT  42.541 8.784 42.797 8.808 ;
     RECT  42.613 34.032 42.829 35.352 ;
     RECT  41.573 22.176 42.865 22.2 ;
     RECT  42.865 22.08 42.901 22.2 ;
     RECT  42.793 25.008 42.901 25.224 ;
     RECT  42.865 18.144 42.937 18.168 ;
     RECT  42.901 22.08 42.937 23.016 ;
     RECT  42.725 50.256 42.941 51.288 ;
     RECT  42.649 46.752 42.973 48.936 ;
     RECT  42.617 14.928 43.009 16.152 ;
     RECT  42.937 17.184 43.009 18.168 ;
     RECT  42.397 10.704 43.013 11.016 ;
     RECT  42.613 31.872 43.013 32.904 ;
     RECT  42.721 27.84 43.045 28.824 ;
     RECT  42.757 36.864 43.049 39 ;
     RECT  42.109 44.736 43.081 44.904 ;
     RECT  43.009 14.928 43.085 18.168 ;
     RECT  42.941 50.688 43.085 51.288 ;
     RECT  43.085 18.144 43.117 18.168 ;
     RECT  43.013 10.704 43.157 10.728 ;
     RECT  43.045 27.36 43.189 28.824 ;
     RECT  42.901 24.336 43.193 25.224 ;
     RECT  43.085 14.928 43.229 17.16 ;
     RECT  42.973 46.512 43.229 48.936 ;
     RECT  43.081 44.688 43.261 44.904 ;
     RECT  43.049 36.864 43.301 38.328 ;
     RECT  43.229 14.976 43.331 17.16 ;
     RECT  43.297 7.056 43.333 7.08 ;
     RECT  43.085 50.688 43.337 50.712 ;
     RECT  43.331 14.976 43.373 16.152 ;
     RECT  43.117 18.144 43.373 18.216 ;
     RECT  42.937 22.08 43.373 23.256 ;
     RECT  43.373 15.12 43.409 16.152 ;
     RECT  42.829 34.032 43.409 35.88 ;
     RECT  43.081 4.56 43.441 4.584 ;
     RECT  43.331 17.136 43.445 17.16 ;
     RECT  43.013 32.448 43.477 32.904 ;
     RECT  43.409 34.032 43.477 35.112 ;
     RECT  43.441 3.84 43.481 4.584 ;
     RECT  43.117 40.992 43.517 41.016 ;
     RECT  43.261 44.352 43.517 44.904 ;
     RECT  43.229 46.512 43.517 47.064 ;
     RECT  43.081 20.976 43.525 21 ;
     RECT  43.409 15.504 43.553 16.152 ;
     RECT  40.681 56.592 43.553 56.616 ;
     RECT  43.373 18.192 43.571 18.216 ;
     RECT  43.189 26.736 43.585 28.824 ;
     RECT  43.553 15.504 43.589 15.864 ;
     RECT  43.429 30.192 43.589 31.128 ;
     RECT  43.301 36.864 43.589 38.04 ;
     RECT  43.517 44.352 43.589 44.808 ;
     RECT  43.525 20.304 43.612 21 ;
     RECT  43.333 7.056 43.625 7.368 ;
     RECT  43.612 20.976 43.625 21 ;
     RECT  43.625 7.248 43.693 7.368 ;
     RECT  43.589 30.192 43.693 30.792 ;
     RECT  43.373 22.08 43.697 22.584 ;
     RECT  43.585 26.64 43.729 28.824 ;
     RECT  43.693 30 43.729 30.792 ;
     RECT  43.693 7.248 43.765 8.088 ;
     RECT  43.589 44.448 43.805 44.808 ;
     RECT  43.729 26.64 43.877 30.792 ;
     RECT  43.589 36.864 43.877 36.888 ;
     RECT  43.441 5.808 43.913 5.832 ;
     RECT  43.477 32.448 43.913 35.112 ;
     RECT  43.765 7.248 43.949 8.568 ;
     RECT  43.913 34.176 44.021 35.112 ;
     RECT  44.021 34.224 44.057 35.112 ;
     RECT  43.877 26.64 44.197 30.744 ;
     RECT  43.697 22.176 44.273 22.584 ;
     RECT  43.229 48.24 44.345 48.936 ;
     RECT  43.193 25.2 44.377 25.224 ;
     RECT  44.197 26.208 44.377 30.744 ;
     RECT  44.305 50.928 44.413 50.952 ;
     RECT  44.377 25.2 44.417 30.744 ;
     RECT  44.156 5.184 44.453 5.208 ;
     RECT  44.417 25.2 44.453 29.592 ;
     RECT  44.345 48.24 44.489 48.312 ;
     RECT  44.453 25.2 44.525 28.584 ;
     RECT  43.481 3.84 44.597 3.864 ;
     RECT  43.949 8.544 44.597 8.568 ;
     RECT  44.525 25.2 44.597 26.664 ;
     RECT  44.525 27.984 44.597 28.584 ;
     RECT  43.949 7.248 44.629 7.368 ;
     RECT  44.485 12.576 44.629 12.6 ;
     RECT  43.913 32.448 44.845 32.808 ;
     RECT  44.629 12.528 44.965 12.6 ;
     RECT  44.809 13.776 44.965 13.8 ;
     RECT  44.413 50.928 44.989 51.144 ;
     RECT  44.629 6.816 45.025 7.368 ;
     RECT  44.989 50.928 45.025 51.288 ;
     RECT  44.845 39.504 45.097 39.528 ;
     RECT  44.965 12.528 45.205 13.8 ;
     RECT  44.989 36.576 45.249 36.6 ;
     RECT  43.589 37.872 45.249 38.04 ;
     RECT  45.249 36.576 45.301 38.04 ;
     RECT  43.517 46.752 45.308 47.064 ;
     RECT  44.489 48.24 45.308 48.264 ;
     RECT  45.205 11.952 45.356 13.8 ;
     RECT  43.589 15.504 45.356 15.816 ;
     RECT  44.057 34.224 45.397 34.776 ;
     RECT  45.025 5.472 45.493 7.368 ;
     RECT  44.273 22.176 45.493 22.488 ;
     RECT  45.308 46.752 45.493 48.264 ;
     RECT  45.025 50.784 45.493 51.288 ;
     RECT  45.301 35.856 45.529 38.04 ;
     RECT  45.097 39.168 45.529 39.528 ;
     RECT  45.493 46.224 45.529 48.264 ;
     RECT  45.493 5.28 45.565 7.368 ;
     RECT  44.597 25.2 45.565 25.224 ;
     RECT  44.597 26.64 45.565 26.664 ;
     RECT  45.313 23.952 45.601 23.976 ;
     RECT  45.565 5.28 45.608 7.416 ;
     RECT  44.989 9.264 45.608 9.48 ;
     RECT  45.356 11.952 45.608 15.816 ;
     RECT  43.525 19.248 45.608 19.272 ;
     RECT  45.493 22.032 45.608 22.488 ;
     RECT  45.601 23.952 45.608 24.216 ;
     RECT  45.565 25.2 45.608 26.664 ;
     RECT  44.597 28.272 45.608 28.584 ;
     RECT  44.453 29.568 45.608 29.592 ;
     RECT  44.845 32.304 45.608 32.808 ;
     RECT  45.397 34.176 45.608 34.776 ;
     RECT  45.529 35.856 45.608 39.528 ;
     RECT  43.805 44.448 45.608 44.52 ;
     RECT  45.529 46.224 45.608 49.08 ;
     RECT  45.493 50.112 45.608 51.288 ;
     RECT  43.225 58.128 45.608 58.152 ;
     RECT  45.608 2.148 45.712 62.652 ;
     RECT  45.712 2.418 45.904 62.382 ;
     RECT  45.904 46.224 46.019 55.176 ;
     RECT  45.904 17.616 46.145 19.8 ;
     RECT  46.019 46.272 46.145 55.176 ;
     RECT  45.904 39.504 46.181 39.528 ;
     RECT  45.904 44.448 46.217 45.096 ;
     RECT  45.904 11.28 46.253 16.536 ;
     RECT  45.904 28.272 46.289 29.064 ;
     RECT  45.904 36 46.289 38.232 ;
     RECT  46.145 48.816 46.289 55.176 ;
     RECT  46.289 28.272 46.307 28.296 ;
     RECT  45.904 22.032 46.353 22.344 ;
     RECT  46.353 22.128 46.361 22.344 ;
     RECT  45.904 24.096 46.361 24.744 ;
     RECT  46.289 48.816 46.361 50.664 ;
     RECT  45.904 30.144 46.397 32.808 ;
     RECT  46.361 22.176 46.469 22.344 ;
     RECT  46.361 48.816 46.469 50.616 ;
     RECT  46.253 12.528 46.499 16.536 ;
     RECT  46.289 36.768 46.505 38.232 ;
     RECT  46.499 12.576 46.649 16.536 ;
     RECT  46.649 12.576 46.721 12.6 ;
     RECT  45.904 4.272 46.739 9.96 ;
     RECT  46.361 24.096 46.757 24.552 ;
     RECT  45.904 25.824 46.757 27.144 ;
     RECT  46.469 48.816 46.793 50.088 ;
     RECT  46.757 24.096 46.829 24.216 ;
     RECT  46.757 25.824 46.901 27 ;
     RECT  46.145 46.272 46.901 47.064 ;
     RECT  46.289 51.888 46.937 55.176 ;
     RECT  45.904 42.432 46.969 42.984 ;
     RECT  46.739 4.272 46.973 9.048 ;
     RECT  46.901 26.208 46.973 27 ;
     RECT  46.145 18.192 47.005 19.8 ;
     RECT  46.933 20.976 47.005 21 ;
     RECT  46.973 6.24 47.009 9.048 ;
     RECT  46.973 26.208 47.009 26.472 ;
     RECT  46.505 36.96 47.041 38.232 ;
     RECT  46.649 13.92 47.045 16.536 ;
     RECT  46.397 30.384 47.077 32.808 ;
     RECT  45.904 34.176 47.077 34.68 ;
     RECT  47.045 13.92 47.081 15.144 ;
     RECT  47.077 30.384 47.081 34.68 ;
     RECT  46.217 44.832 47.081 45.096 ;
     RECT  46.829 24.192 47.117 24.216 ;
     RECT  47.081 32.304 47.123 34.68 ;
     RECT  47.009 6.24 47.153 6.888 ;
     RECT  47.123 32.784 47.164 34.68 ;
     RECT  47.009 8.688 47.225 9.048 ;
     RECT  47.225 8.688 47.261 8.712 ;
     RECT  47.153 6.24 47.297 6.6 ;
     RECT  46.253 11.28 47.365 11.4 ;
     RECT  46.973 4.272 47.369 5.208 ;
     RECT  45.904 58.128 47.369 58.152 ;
     RECT  47.081 13.92 47.441 15.096 ;
     RECT  47.041 36.96 47.477 38.424 ;
     RECT  47.005 18.192 47.513 21 ;
     RECT  47.513 18.864 47.549 21 ;
     RECT  46.937 52.08 47.549 55.176 ;
     RECT  47.477 36.96 47.581 37.032 ;
     RECT  47.369 5.184 47.585 5.208 ;
     RECT  47.549 19.344 47.585 20.568 ;
     RECT  47.549 54.096 47.585 55.176 ;
     RECT  47.581 36.816 47.653 37.032 ;
     RECT  47.477 38.208 47.653 38.424 ;
     RECT  47.009 26.208 47.657 26.232 ;
     RECT  47.441 13.92 47.693 15.048 ;
     RECT  47.317 61.008 47.693 61.032 ;
     RECT  47.693 13.92 47.756 14.184 ;
     RECT  47.164 34.176 47.761 34.68 ;
     RECT  46.469 22.176 47.833 22.2 ;
     RECT  47.585 20.544 47.837 20.568 ;
     RECT  47.653 36.624 47.873 37.032 ;
     RECT  46.969 42.432 47.909 43.608 ;
     RECT  46.793 48.816 47.909 49.512 ;
     RECT  47.833 22.176 47.917 22.824 ;
     RECT  47.365 11.136 47.941 11.4 ;
     RECT  47.761 34.176 47.945 35.448 ;
     RECT  47.873 36.624 47.945 36.984 ;
     RECT  47.045 16.464 47.981 16.488 ;
     RECT  47.945 36.624 48.017 36.936 ;
     RECT  47.941 11.136 48.028 12.12 ;
     RECT  47.297 6.24 48.044 6.312 ;
     RECT  48.044 5.616 48.131 6.312 ;
     RECT  47.977 29.28 48.157 29.304 ;
     RECT  47.081 30.384 48.157 30.84 ;
     RECT  47.909 48.816 48.193 48.84 ;
     RECT  47.917 22.176 48.229 22.776 ;
     RECT  46.901 46.752 48.265 47.064 ;
     RECT  48.229 22.08 48.269 22.776 ;
     RECT  47.653 38.208 48.269 38.76 ;
     RECT  48.131 6.288 48.301 6.312 ;
     RECT  47.945 35.424 48.301 35.448 ;
     RECT  48.049 24.384 48.337 24.408 ;
     RECT  48.301 6.288 48.341 6.888 ;
     RECT  48.269 38.736 48.341 38.76 ;
     RECT  47.756 13.632 48.373 14.184 ;
     RECT  48.157 29.28 48.409 30.84 ;
     RECT  47.081 44.832 48.409 45 ;
     RECT  48.265 46.752 48.409 47.304 ;
     RECT  48.265 27.792 48.445 27.816 ;
     RECT  48.409 29.184 48.445 30.84 ;
     RECT  48.085 26.736 48.469 26.76 ;
     RECT  48.445 27.792 48.469 30.84 ;
     RECT  48.409 44.832 48.517 47.304 ;
     RECT  48.017 36.816 48.521 36.936 ;
     RECT  47.909 42.432 48.625 43.272 ;
     RECT  48.517 44.304 48.697 47.304 ;
     RECT  48.193 48.48 48.697 48.84 ;
     RECT  48.445 50.688 48.757 50.712 ;
     RECT  48.709 15.84 48.796 15.864 ;
     RECT  47.549 52.08 48.809 53.064 ;
     RECT  48.757 50.544 48.841 50.712 ;
     RECT  48.469 26.736 48.851 30.84 ;
     RECT  48.373 13.296 48.877 14.184 ;
     RECT  47.585 19.344 48.913 19.368 ;
     RECT  47.833 17.52 48.917 17.544 ;
     RECT  48.877 13.104 48.949 14.184 ;
     RECT  45.904 40.608 48.949 40.632 ;
     RECT  47.585 54.096 48.949 54.12 ;
     RECT  47.585 55.152 48.949 55.176 ;
     RECT  48.949 13.104 48.989 14.76 ;
     RECT  48.341 6.864 49.004 6.888 ;
     RECT  48.913 19.344 49.021 19.896 ;
     RECT  48.949 40.608 49.036 40.728 ;
     RECT  49.004 6.864 49.045 7.368 ;
     RECT  48.989 13.296 49.057 14.76 ;
     RECT  49.045 6.864 49.061 7.656 ;
     RECT  48.949 54.096 49.061 55.176 ;
     RECT  49.061 7.344 49.091 7.656 ;
     RECT  48.851 26.736 49.093 30.744 ;
     RECT  49.021 18.192 49.097 19.896 ;
     RECT  48.697 44.304 49.097 48.84 ;
     RECT  48.841 50.544 49.097 51.144 ;
     RECT  49.057 13.296 49.129 14.856 ;
     RECT  49.097 44.976 49.165 48.84 ;
     RECT  48.841 39.6 49.201 39.624 ;
     RECT  47.039 59.616 49.205 59.64 ;
     RECT  49.129 13.296 49.241 15 ;
     RECT  49.201 39.6 49.241 40.056 ;
     RECT  48.337 24.24 49.273 24.408 ;
     RECT  48.625 41.904 49.313 43.272 ;
     RECT  49.165 44.976 49.313 48.984 ;
     RECT  49.273 24.24 49.345 25.176 ;
     RECT  49.313 42.432 49.345 43.272 ;
     RECT  49.345 42.432 49.349 43.368 ;
     RECT  49.313 45.936 49.349 48.984 ;
     RECT  48.269 22.08 49.417 22.2 ;
     RECT  49.093 26.208 49.421 30.744 ;
     RECT  48.809 52.176 49.421 53.064 ;
     RECT  49.061 54.096 49.427 54.12 ;
     RECT  49.381 58.128 49.465 58.152 ;
     RECT  47.945 34.176 49.489 34.2 ;
     RECT  48.301 35.424 49.489 35.496 ;
     RECT  49.241 13.68 49.493 15 ;
     RECT  49.417 21.984 49.525 22.2 ;
     RECT  49.345 23.328 49.525 25.176 ;
     RECT  49.421 27.312 49.529 30.744 ;
     RECT  49.525 21.984 49.561 25.176 ;
     RECT  49.189 37.584 49.565 37.608 ;
     RECT  49.489 34.176 49.637 35.496 ;
     RECT  49.573 36.48 49.709 36.504 ;
     RECT  49.097 18.192 49.745 18.792 ;
     RECT  49.637 35.04 49.745 35.496 ;
     RECT  48.028 11.136 49.777 11.304 ;
     RECT  49.561 21.984 49.817 26.136 ;
     RECT  49.745 18.432 49.889 18.792 ;
     RECT  49.349 46.752 49.916 48.984 ;
     RECT  49.916 46.752 49.957 49.56 ;
     RECT  49.097 50.544 49.957 50.712 ;
     RECT  49.817 23.328 49.997 26.136 ;
     RECT  49.916 9.072 50.003 9.096 ;
     RECT  49.957 46.752 50.003 50.712 ;
     RECT  50.209 12.288 50.252 12.312 ;
     RECT  49.493 13.68 50.252 14.184 ;
     RECT  49.777 11.088 50.293 11.304 ;
     RECT  50.252 12.288 50.293 14.184 ;
     RECT  49.813 15.36 50.348 15.384 ;
     RECT  49.529 27.888 50.353 30.744 ;
     RECT  50.317 44.736 50.389 44.76 ;
     RECT  50.389 44.64 50.461 44.76 ;
     RECT  49.633 53.568 50.492 53.592 ;
     RECT  49.997 23.52 50.569 26.136 ;
     RECT  49.889 18.528 50.605 18.792 ;
     RECT  49.097 19.872 50.605 19.896 ;
     RECT  50.605 18.528 50.641 19.896 ;
     RECT  50.461 44.64 50.641 45.048 ;
     RECT  49.885 51.888 50.641 51.912 ;
     RECT  50.293 11.088 50.713 14.184 ;
     RECT  50.353 27.888 50.713 31.176 ;
     RECT  47.164 32.784 50.713 32.808 ;
     RECT  49.745 35.04 50.713 35.352 ;
     RECT  49.349 42.96 50.713 43.368 ;
     RECT  50.641 44.64 50.713 45.528 ;
     RECT  50.569 23.52 50.749 26.664 ;
     RECT  50.713 27.888 50.749 32.808 ;
     RECT  50.605 63.84 50.771 63.864 ;
     RECT  49.241 40.032 50.849 40.056 ;
     RECT  50.348 15.36 50.857 15.624 ;
     RECT  50.641 18.528 50.857 20.808 ;
     RECT  49.817 21.984 50.857 22.2 ;
     RECT  50.713 42.96 50.857 45.528 ;
     RECT  50.209 38.16 50.869 38.184 ;
     RECT  50.849 39.456 50.869 40.056 ;
     RECT  50.209 36.912 50.965 36.936 ;
     RECT  50.869 38.16 50.965 40.056 ;
     RECT  50.749 23.52 51.001 32.808 ;
     RECT  49.061 55.152 51.001 55.176 ;
     RECT  49.091 7.632 51.008 7.656 ;
     RECT  50.713 10.992 51.008 14.184 ;
     RECT  50.857 15.36 51.008 15.768 ;
     RECT  50.209 16.8 51.008 16.824 ;
     RECT  50.857 18.528 51.008 22.2 ;
     RECT  51.001 23.52 51.008 33.048 ;
     RECT  50.713 34.32 51.008 35.352 ;
     RECT  50.965 36.912 51.008 40.056 ;
     RECT  50.857 42.72 51.008 45.528 ;
     RECT  50.003 46.752 51.008 50.568 ;
     RECT  50.641 51.648 51.008 51.912 ;
     RECT  50.492 52.896 51.008 53.592 ;
     RECT  51.001 55.152 51.008 55.8 ;
     RECT  49.597 58.656 51.008 58.68 ;
     RECT  51.008 2.148 51.112 62.652 ;
     RECT  51.112 2.418 51.304 62.382 ;
     RECT  51.304 28.752 51.329 33.048 ;
     RECT  51.304 4.512 51.443 4.536 ;
     RECT  51.304 7.632 51.443 7.8 ;
     RECT  51.304 25.44 51.509 27.48 ;
     RECT  51.509 26.544 51.653 27.48 ;
     RECT  51.304 18.528 51.689 19.224 ;
     RECT  51.329 29.808 51.689 33.048 ;
     RECT  51.689 29.808 51.725 30.888 ;
     RECT  51.689 18.768 51.733 19.224 ;
     RECT  51.653 26.64 51.869 27.48 ;
     RECT  51.329 28.752 51.869 28.776 ;
     RECT  51.304 10.992 51.905 14.184 ;
     RECT  51.304 23.952 51.941 24.264 ;
     RECT  51.725 30.576 51.941 30.888 ;
     RECT  51.304 53.088 52.013 53.112 ;
     RECT  51.689 31.872 52.085 33.048 ;
     RECT  51.304 48.432 52.085 51.912 ;
     RECT  52.085 32.784 52.115 33.048 ;
     RECT  51.304 34.08 52.115 37.656 ;
     RECT  52.115 34.08 52.156 34.776 ;
     RECT  51.509 25.44 52.265 25.464 ;
     RECT  52.085 48.432 52.301 51.816 ;
     RECT  52.268 53.76 52.355 53.784 ;
     RECT  51.304 45.168 52.357 45.528 ;
     RECT  51.304 47.04 52.357 47.064 ;
     RECT  51.443 7.776 52.405 7.8 ;
     RECT  52.115 35.904 52.409 37.656 ;
     RECT  51.905 11.136 52.451 14.184 ;
     RECT  52.409 37.584 52.451 37.656 ;
     RECT  51.304 42.72 52.513 42.744 ;
     RECT  51.304 21.648 52.585 22.872 ;
     RECT  52.409 35.904 52.625 36.6 ;
     RECT  52.585 21.12 52.661 22.872 ;
     RECT  52.156 34.224 52.661 34.776 ;
     RECT  52.301 48.432 52.697 49.56 ;
     RECT  51.733 18.864 52.805 19.224 ;
     RECT  51.941 30.864 52.805 30.888 ;
     RECT  51.304 15.312 52.837 16.488 ;
     RECT  51.941 24.24 52.837 24.264 ;
     RECT  52.697 48.96 52.841 49.56 ;
     RECT  52.625 36.576 52.913 36.6 ;
     RECT  52.513 42.432 52.945 42.744 ;
     RECT  52.729 43.776 52.945 43.8 ;
     RECT  52.357 45.168 52.981 47.064 ;
     RECT  52.945 42.432 53.029 43.8 ;
     RECT  52.661 21.12 53.053 21.192 ;
     RECT  52.837 24.24 53.129 24.456 ;
     RECT  52.661 34.224 53.129 34.248 ;
     RECT  52.451 37.584 53.129 37.608 ;
     RECT  53.029 42.432 53.165 42.792 ;
     RECT  52.405 27.936 53.201 27.96 ;
     RECT  52.301 50.544 53.269 51.816 ;
     RECT  53.165 42.432 53.345 42.456 ;
     RECT  52.661 22.608 53.377 22.872 ;
     RECT  53.129 24.24 53.377 24.408 ;
     RECT  52.451 11.952 53.593 14.184 ;
     RECT  52.405 7.776 53.603 8.712 ;
     RECT  52.837 15.312 53.633 16.824 ;
     RECT  53.593 11.568 53.665 14.184 ;
     RECT  53.269 50.544 53.741 51.864 ;
     RECT  53.377 22.608 53.773 24.408 ;
     RECT  53.593 52.992 53.773 53.016 ;
     RECT  53.593 54.624 53.773 54.648 ;
     RECT  53.665 11.568 53.881 14.232 ;
     RECT  51.304 58.656 53.891 58.68 ;
     RECT  53.809 59.856 53.893 59.88 ;
     RECT  53.053 20.544 53.917 21.192 ;
     RECT  53.557 6.24 53.957 6.264 ;
     RECT  52.841 49.536 53.989 49.56 ;
     RECT  53.633 15.312 54.029 16.488 ;
     RECT  53.773 52.992 54.029 54.648 ;
     RECT  52.805 19.2 54.061 19.224 ;
     RECT  53.917 20.304 54.061 21.192 ;
     RECT  53.029 43.776 54.065 43.8 ;
     RECT  53.989 48.912 54.092 49.56 ;
     RECT  53.741 50.544 54.092 51.192 ;
     RECT  53.773 22.176 54.133 24.408 ;
     RECT  54.029 16.416 54.137 16.488 ;
     RECT  54.061 18.24 54.145 21.192 ;
     RECT  54.029 54.624 54.169 54.648 ;
     RECT  53.881 11.136 54.173 14.232 ;
     RECT  54.092 48.912 54.209 51.192 ;
     RECT  54.209 48.912 54.317 51 ;
     RECT  54.169 54.624 54.349 54.696 ;
     RECT  54.133 22.176 54.389 24.552 ;
     RECT  54.349 54.624 54.419 55.32 ;
     RECT  54.419 54.672 54.433 55.32 ;
     RECT  54.389 23.904 54.457 24.552 ;
     RECT  54.421 25.68 54.457 25.704 ;
     RECT  52.981 44.88 54.493 47.064 ;
     RECT  54.029 52.992 54.533 53.4 ;
     RECT  54.173 11.136 54.565 11.592 ;
     RECT  54.173 13.056 54.601 14.232 ;
     RECT  54.145 19.152 54.673 21.192 ;
     RECT  54.389 22.176 54.673 22.68 ;
     RECT  54.317 48.912 54.677 50.568 ;
     RECT  54.565 10.848 54.713 11.592 ;
     RECT  54.677 49.008 54.713 50.568 ;
     RECT  54.533 52.992 54.713 53.016 ;
     RECT  54.713 49.008 54.749 49.032 ;
     RECT  52.115 32.784 54.781 32.808 ;
     RECT  54.457 23.904 54.793 25.704 ;
     RECT  54.601 13.056 54.821 14.664 ;
     RECT  54.313 29.952 54.851 29.976 ;
     RECT  54.673 19.152 54.857 22.68 ;
     RECT  54.781 31.92 54.865 32.808 ;
     RECT  54.713 11.136 54.893 11.592 ;
     RECT  54.821 13.056 54.965 14.184 ;
     RECT  54.857 19.2 54.965 22.68 ;
     RECT  54.793 23.904 54.995 24.888 ;
     RECT  54.965 19.2 55.001 21.72 ;
     RECT  54.889 42.72 55.033 42.744 ;
     RECT  54.493 44.448 55.033 47.064 ;
     RECT  55.033 42.672 55.069 42.744 ;
     RECT  55.033 44.448 55.069 47.496 ;
     RECT  53.603 8.64 55.105 8.712 ;
     RECT  55.105 8.64 55.145 8.76 ;
     RECT  55.001 20.832 55.325 21.72 ;
     RECT  54.995 23.904 55.325 24.552 ;
     RECT  55.325 21.168 55.361 21.72 ;
     RECT  55.069 42.528 55.393 42.744 ;
     RECT  55.069 44.448 55.393 47.64 ;
     RECT  52.405 38.64 55.532 38.664 ;
     RECT  55.532 38.64 55.545 38.808 ;
     RECT  55.545 38.64 55.573 39.24 ;
     RECT  54.433 54.672 55.609 54.696 ;
     RECT  53.557 27.84 56.293 27.864 ;
     RECT  54.137 16.416 56.329 16.44 ;
     RECT  55.145 8.736 56.408 8.76 ;
     RECT  54.893 11.136 56.408 11.16 ;
     RECT  55.753 12.528 56.408 12.552 ;
     RECT  54.965 13.68 56.408 14.184 ;
     RECT  56.329 15.552 56.408 16.44 ;
     RECT  55.001 19.2 56.408 19.224 ;
     RECT  56.293 20.592 56.408 20.616 ;
     RECT  55.361 21.696 56.408 21.72 ;
     RECT  55.325 23.904 56.408 23.928 ;
     RECT  56.293 27.072 56.408 27.864 ;
     RECT  54.865 32.784 56.408 32.808 ;
     RECT  56.365 35.712 56.408 35.736 ;
     RECT  55.573 38.64 56.408 39.336 ;
     RECT  55.393 42.528 56.408 47.64 ;
     RECT  54.713 50.256 56.408 50.568 ;
     RECT  55.861 52.992 56.408 53.016 ;
     RECT  55.609 54.672 56.408 54.792 ;
     RECT  53.845 56.544 56.408 56.568 ;
     RECT  56.408 2.148 56.512 62.652 ;
     RECT  56.512 2.418 56.677 62.652 ;
     RECT  56.677 2.418 56.704 63.24 ;
     RECT  56.704 42.576 56.765 47.16 ;
     RECT  56.704 63.216 56.765 63.24 ;
     RECT  56.704 50.544 56.873 51.336 ;
     RECT  56.704 48.432 56.909 48.84 ;
     RECT  56.765 43.008 56.915 47.16 ;
     RECT  56.909 48.432 56.915 48.456 ;
     RECT  56.704 35.712 56.963 36.696 ;
     RECT  56.704 39.12 56.989 39.336 ;
     RECT  56.915 43.008 57.017 43.848 ;
     RECT  56.704 19.344 57.059 19.368 ;
     RECT  57.017 43.008 57.089 43.608 ;
     RECT  56.704 29.424 57.148 29.496 ;
     RECT  56.704 54.672 57.197 54.696 ;
     RECT  56.704 20.544 57.521 20.616 ;
     RECT  56.704 15.312 57.635 15.576 ;
     RECT  56.704 52.992 57.841 53.016 ;
     RECT  57.788 25.152 57.875 25.176 ;
     RECT  56.704 27.696 57.875 27.72 ;
     RECT  56.873 50.544 57.877 50.568 ;
     RECT  56.915 45.168 57.881 47.16 ;
     RECT  57.877 50.544 57.923 50.856 ;
     RECT  57.841 52.992 57.925 53.064 ;
     RECT  57.913 37.584 58.117 37.608 ;
     RECT  58.117 37.584 58.163 38.136 ;
     RECT  56.704 12.528 58.241 12.552 ;
     RECT  57.521 20.592 58.261 20.616 ;
     RECT  58.237 21.696 58.261 21.72 ;
     RECT  58.261 20.592 58.307 21.72 ;
     RECT  57.841 54.144 58.561 54.168 ;
     RECT  57.089 43.008 58.597 43.272 ;
     RECT  58.561 54.144 58.601 54.408 ;
     RECT  56.704 32.784 58.643 32.808 ;
     RECT  56.704 13.68 58.673 14.184 ;
     RECT  57.829 22.752 58.673 22.776 ;
     RECT  58.597 42.768 58.681 43.272 ;
     RECT  58.673 13.68 58.709 13.896 ;
     RECT  58.681 43.008 59.077 43.272 ;
     RECT  59.077 43.008 59.164 43.8 ;
     RECT  57.881 45.792 59.317 47.16 ;
     RECT  59.317 44.976 59.321 47.16 ;
     RECT  58.165 52.8 59.713 52.824 ;
     RECT  59.713 52.656 59.753 52.824 ;
     RECT  58.307 20.64 59.821 21.72 ;
     RECT  59.321 44.976 59.843 46.248 ;
     RECT  59.821 20.592 59.861 21.72 ;
     RECT  59.797 47.328 59.897 47.352 ;
     RECT  59.164 43.008 60.109 43.032 ;
     RECT  60.109 42.72 60.149 43.032 ;
     RECT  58.601 54.384 60.217 54.408 ;
     RECT  60.217 54.384 60.257 54.744 ;
     RECT  56.704 56.544 60.505 56.568 ;
     RECT  60.505 56.544 60.545 56.808 ;
     RECT  57.923 50.832 60.572 50.856 ;
     RECT  60.572 50.4 60.659 50.856 ;
     RECT  59.753 52.656 60.659 52.68 ;
     RECT  59.843 45.936 60.689 46.248 ;
     RECT  60.793 44.352 61.333 44.376 ;
     RECT  56.704 8.736 61.369 8.76 ;
     RECT  60.257 54.72 61.405 54.744 ;
     RECT  57.148 29.424 61.436 29.448 ;
     RECT  61.381 6.096 61.808 6.12 ;
     RECT  61.369 7.968 61.808 8.76 ;
     RECT  58.709 13.824 61.808 13.896 ;
     RECT  56.704 16.8 61.808 16.824 ;
     RECT  59.861 20.592 61.808 20.616 ;
     RECT  59.861 21.696 61.808 21.72 ;
     RECT  61.477 26.736 61.808 26.76 ;
     RECT  61.436 28.944 61.808 29.448 ;
     RECT  58.163 38.112 61.808 38.136 ;
     RECT  56.989 39.312 61.808 39.336 ;
     RECT  60.149 42.72 61.808 42.744 ;
     RECT  61.333 44.352 61.808 44.472 ;
     RECT  60.689 46.224 61.808 46.248 ;
     RECT  61.765 49.008 61.808 49.032 ;
     RECT  60.659 50.832 61.808 50.856 ;
     RECT  61.405 54.72 61.808 55.176 ;
     RECT  60.545 56.784 61.808 56.808 ;
     RECT  61.808 2.148 61.912 62.652 ;
     RECT  61.912 2.418 62.104 62.382 ;
     RECT  62.104 56.784 62.165 56.808 ;
     RECT  62.104 6.096 62.237 6.12 ;
     RECT  62.104 55.152 62.633 55.176 ;
     RECT  62.104 46.176 62.705 46.2 ;
     RECT  62.104 44.976 63.169 45 ;
     RECT  63.169 44.544 63.209 45 ;
     RECT  62.104 49.008 63.421 49.032 ;
     RECT  63.421 49.008 63.461 49.368 ;
     RECT  62.104 21.696 63.683 21.72 ;
     RECT  63.601 25.104 63.685 25.128 ;
     RECT  62.104 50.832 63.692 50.856 ;
     RECT  63.692 50.832 63.781 51.816 ;
     RECT  63.701 55.872 63.785 55.896 ;
     RECT  63.461 49.344 63.827 49.368 ;
     RECT  63.529 42.72 63.875 42.744 ;
     RECT  63.781 48.24 63.929 48.264 ;
     RECT  63.781 50.736 64.355 51.816 ;
     RECT  64.355 50.736 64.429 50.76 ;
     RECT  64.429 50.544 64.469 50.76 ;
     RECT  63.209 44.544 64.577 44.568 ;
     RECT  62.104 38.16 65.005 38.184 ;
     RECT  64.355 51.792 65.333 51.816 ;
     RECT  63.829 41.28 65.557 41.304 ;
     RECT  65.557 40.8 65.621 41.304 ;
     RECT  65.621 40.8 65.644 40.872 ;
     RECT  65.005 38.112 65.989 38.184 ;
     RECT  62.104 39.312 65.989 39.336 ;
     RECT  65.869 36.432 66.083 36.456 ;
     RECT  62.104 13.824 66.085 13.896 ;
     RECT  65.989 38.112 66.124 39.336 ;
     RECT  66.124 38.208 66.131 39.336 ;
     RECT  66.131 38.208 66.133 38.232 ;
     RECT  66.085 13.68 66.169 13.896 ;
     RECT  66.085 5.472 67.208 5.496 ;
     RECT  66.169 13.824 67.208 13.896 ;
     RECT  62.104 20.592 67.208 20.616 ;
     RECT  63.637 22.752 67.208 22.776 ;
     RECT  66.131 39.216 67.208 39.24 ;
     RECT  65.644 40.848 67.208 40.872 ;
     RECT  65.257 48.384 67.208 48.408 ;
     RECT  64.469 50.544 67.208 50.568 ;
     RECT  64.309 59.568 67.208 59.592 ;
     RECT  67.208 2.148 67.312 62.652 ;
     RECT  67.312 2.418 67.504 62.382 ;
     RECT  67.504 59.568 67.601 59.736 ;
     RECT  67.504 48.384 67.619 48.408 ;
     RECT  67.504 50.16 67.745 50.76 ;
     RECT  67.745 50.16 67.781 50.184 ;
     RECT  67.504 13.872 69.221 14.136 ;
     RECT  67.504 22.752 69.469 22.776 ;
     RECT  69.469 21.792 69.644 22.776 ;
     RECT  69.289 25.68 69.677 25.704 ;
     RECT  69.644 21.792 69.685 23.208 ;
     RECT  69.685 21.792 69.689 24.12 ;
     RECT  69.689 23.184 69.731 24.12 ;
     RECT  69.677 25.68 69.761 25.752 ;
     RECT  69.865 30.816 69.949 30.84 ;
     RECT  69.689 21.792 70.333 21.816 ;
     RECT  70.333 21.696 70.373 21.816 ;
     RECT  69.731 24.096 70.913 24.12 ;
     RECT  67.504 20.592 71.045 20.616 ;
     RECT  67.504 5.472 71.305 5.496 ;
     RECT  69.877 28.8 71.521 28.824 ;
     RECT  70.873 35.712 71.521 35.736 ;
     RECT  69.221 14.112 71.845 14.136 ;
     RECT  71.917 38.16 71.941 38.184 ;
     RECT  67.504 39.216 71.941 39.24 ;
     RECT  67.504 40.848 71.941 41.16 ;
     RECT  71.197 26.928 72.025 26.952 ;
     RECT  71.305 4.512 72.205 5.496 ;
     RECT  72.205 3.696 72.277 5.496 ;
     RECT  71.845 13.632 72.277 14.136 ;
     RECT  69.761 25.68 72.284 25.704 ;
     RECT  71.989 34.512 72.325 34.536 ;
     RECT  71.045 20.544 72.373 20.616 ;
     RECT  72.277 3.312 72.469 6.312 ;
     RECT  71.845 15.456 72.469 15.48 ;
     RECT  72.421 16.512 72.469 16.536 ;
     RECT  72.469 3.312 72.608 6.84 ;
     RECT  72.469 9.792 72.608 9.816 ;
     RECT  72.277 12.864 72.608 14.136 ;
     RECT  72.469 15.456 72.608 16.536 ;
     RECT  69.181 19.344 72.608 19.368 ;
     RECT  72.373 20.4 72.608 20.616 ;
     RECT  70.373 21.696 72.608 21.72 ;
     RECT  72.373 23.376 72.608 23.4 ;
     RECT  72.284 25.296 72.608 25.704 ;
     RECT  72.025 26.928 72.608 27.192 ;
     RECT  71.521 28.8 72.608 29.016 ;
     RECT  72.325 33.552 72.608 34.536 ;
     RECT  71.521 35.712 72.608 36.456 ;
     RECT  71.941 37.824 72.608 41.16 ;
     RECT  67.601 59.712 72.608 59.736 ;
     RECT  72.608 2.148 72.712 62.652 ;
     RECT  72.712 2.418 72.904 62.382 ;
     RECT  72.904 15.456 73.037 15.48 ;
     RECT  72.904 20.256 73.397 20.424 ;
     RECT  72.904 6.288 73.469 6.312 ;
     RECT  72.904 11.376 73.523 11.4 ;
     RECT  72.904 12.72 73.523 12.888 ;
     RECT  72.904 3.312 73.577 3.336 ;
     RECT  72.904 41.136 73.715 41.16 ;
     RECT  72.904 38.688 73.721 39.672 ;
     RECT  73.721 39.216 73.757 39.672 ;
     RECT  73.523 12.72 73.973 12.744 ;
     RECT  72.904 24.768 74.101 25.56 ;
     RECT  74.101 24.768 74.147 25.896 ;
     RECT  74.147 25.536 74.297 25.896 ;
     RECT  72.904 27.168 74.297 27.192 ;
     RECT  72.904 16.56 74.761 16.584 ;
     RECT  74.761 16.56 74.801 17.112 ;
     RECT  72.904 9.792 75.049 9.816 ;
     RECT  73.397 20.256 75.26 20.28 ;
     RECT  73.757 39.36 75.301 39.384 ;
     RECT  75.26 20.256 75.347 20.856 ;
     RECT  74.869 30 75.409 30.024 ;
     RECT  75.337 3.936 75.443 3.96 ;
     RECT  75.301 38.64 75.445 39.384 ;
     RECT  72.904 32.304 75.455 32.328 ;
     RECT  75.445 38.64 75.491 39.912 ;
     RECT  75.409 30 75.493 30.6 ;
     RECT  74.761 35.28 75.493 35.304 ;
     RECT  74.297 25.872 75.539 25.896 ;
     RECT  75.493 29.472 75.539 30.6 ;
     RECT  75.493 34.56 75.539 35.304 ;
     RECT  75.347 20.256 75.781 20.28 ;
     RECT  75.253 36.48 75.781 36.504 ;
     RECT  75.781 19.536 75.827 20.28 ;
     RECT  75.491 38.64 75.827 38.664 ;
     RECT  75.049 9.744 75.829 9.816 ;
     RECT  75.829 9.744 75.875 10.872 ;
     RECT  75.539 29.472 75.881 29.496 ;
     RECT  74.545 7.632 75.913 7.656 ;
     RECT  75.875 9.792 75.917 10.872 ;
     RECT  75.913 7.392 75.953 7.656 ;
     RECT  75.455 31.872 76.021 32.328 ;
     RECT  75.781 36.384 76.025 37.368 ;
     RECT  75.98 15.36 76.067 15.384 ;
     RECT  75.539 34.56 76.067 34.584 ;
     RECT  75.491 39.888 76.421 39.912 ;
     RECT  76.381 5.712 76.885 5.736 ;
     RECT  76.885 4.992 76.931 5.736 ;
     RECT  74.801 17.088 76.997 17.112 ;
     RECT  76.931 4.992 78.008 5.016 ;
     RECT  75.953 7.392 78.008 7.416 ;
     RECT  75.917 9.792 78.008 10.2 ;
     RECT  75.827 19.536 78.008 19.56 ;
     RECT  76.021 31.872 78.008 32.472 ;
     RECT  76.025 37.344 78.008 37.368 ;
     RECT  72.904 59.712 78.008 59.736 ;
     RECT  78.008 2.148 78.112 62.652 ;
     RECT  78.112 2.418 78.304 62.382 ;
     RECT  78.304 9.792 79.661 10.2 ;
     RECT  79.661 10.176 79.805 10.2 ;
     RECT  78.304 8.544 79.841 8.568 ;
     RECT  78.304 19.536 81.065 19.56 ;
     RECT  78.304 4.992 81.157 5.016 ;
     RECT  80.161 8.976 81.157 9 ;
     RECT  81.157 8.976 81.203 9.528 ;
     RECT  81.203 9.504 81.317 9.528 ;
     RECT  78.304 59.712 81.389 60.456 ;
     RECT  81.389 60.432 81.445 60.456 ;
     RECT  81.445 60.432 81.532 61.368 ;
     RECT  81.532 60.432 81.552 60.456 ;
     RECT  81.157 4.992 81.857 5.88 ;
     RECT  81.205 11.376 82.021 11.4 ;
     RECT  78.304 12.72 82.021 12.744 ;
     RECT  82.021 11.376 82.067 12.744 ;
     RECT  80.665 14.256 82.067 14.28 ;
     RECT  82.067 12.336 82.181 12.36 ;
     RECT  81.857 4.992 82.217 5.832 ;
     RECT  82.217 5.808 83.408 5.832 ;
     RECT  83.365 59.856 83.408 59.88 ;
     RECT  83.408 2.148 83.512 62.652 ;
     RECT  83.512 2.418 83.704 62.424 ;
     RECT  83.704 44.736 83.939 45.432 ;
     RECT  83.704 5.808 84.053 5.832 ;
     RECT  84.841 4.416 84.877 4.44 ;
     RECT  84.841 10.896 84.877 10.92 ;
     RECT  84.841 20.4 84.877 20.424 ;
     RECT  84.841 25.872 84.877 25.896 ;
     RECT  84.841 32.88 84.877 32.904 ;
     RECT  84.841 40.896 84.877 40.92 ;
     RECT  84.841 51.888 84.877 51.912 ;
     RECT  83.704 53.376 84.877 53.4 ;
     RECT  84.877 38.4 84.913 38.424 ;
     RECT  84.877 49.872 84.913 49.896 ;
     RECT  84.877 50.88 84.913 51.912 ;
     RECT  84.877 3.888 85.345 4.44 ;
     RECT  84.877 10.416 85.345 10.92 ;
     RECT  84.877 31.392 85.345 32.904 ;
     RECT  85.345 2.88 85.453 2.904 ;
     RECT  85.345 3.888 85.453 4.92 ;
     RECT  84.877 7.392 85.453 7.416 ;
     RECT  85.345 10.416 85.453 11.4 ;
     RECT  84.877 13.392 85.453 13.416 ;
     RECT  84.877 19.872 85.453 20.904 ;
     RECT  84.877 22.896 85.453 22.92 ;
     RECT  84.877 25.392 85.453 25.896 ;
     RECT  83.704 29.376 85.453 29.4 ;
     RECT  85.345 30.912 85.453 32.904 ;
     RECT  85.345 34.368 85.453 34.392 ;
     RECT  84.877 36.864 85.453 36.888 ;
     RECT  84.913 38.4 85.453 38.904 ;
     RECT  84.877 40.368 85.453 40.92 ;
     RECT  83.704 42.864 85.453 43.416 ;
     RECT  84.913 44.4 85.453 44.424 ;
     RECT  83.939 45.408 85.453 45.432 ;
     RECT  85.345 48.384 85.453 48.408 ;
     RECT  84.913 49.872 85.453 51.912 ;
     RECT  84.877 53.376 85.453 54.408 ;
     RECT  84.877 55.392 85.453 55.416 ;
     RECT  84.877 56.4 85.453 57.912 ;
     RECT  83.704 59.376 85.453 62.424 ;
     RECT  85.453 2.4 85.489 13.896 ;
     RECT  85.453 14.88 85.489 15.432 ;
     RECT  85.453 16.416 85.489 18.408 ;
     RECT  85.453 19.392 85.489 47.4 ;
     RECT  85.489 2.4 86.281 47.4 ;
     RECT  85.453 48.384 86.281 62.424 ;
     RECT  86.281 2.4 86.364 62.424 ;
    LAYER M5 ;
     RECT  2.4 2.137 2.52 2.151 ;
     RECT  7.8 2.137 7.92 2.151 ;
     RECT  13.2 2.137 13.32 2.151 ;
     RECT  18.6 2.137 18.72 2.151 ;
     RECT  24 2.137 24.12 2.151 ;
     RECT  29.4 2.137 29.52 2.151 ;
     RECT  34.8 2.137 34.92 2.151 ;
     RECT  40.2 2.137 40.32 2.151 ;
     RECT  45.6 2.137 45.72 2.151 ;
     RECT  51 2.137 51.12 2.151 ;
     RECT  56.4 2.137 56.52 2.151 ;
     RECT  61.8 2.137 61.92 2.151 ;
     RECT  67.2 2.137 67.32 2.151 ;
     RECT  72.6 2.137 72.72 2.151 ;
     RECT  78 2.137 78.12 2.151 ;
     RECT  83.4 2.137 83.52 2.151 ;
     RECT  72.6 2.151 72.912 3.301 ;
     RECT  51 2.151 51.312 4.501 ;
     RECT  44.208 3.829 44.232 5.219 ;
     RECT  40.2 2.151 40.512 5.365 ;
     RECT  38.592 3.925 38.616 5.459 ;
     RECT  76.896 4.981 76.92 5.747 ;
     RECT  82.032 5.029 82.056 5.843 ;
     RECT  3.936 4.501 3.96 5.891 ;
     RECT  61.8 2.151 62.112 6.085 ;
     RECT  40.08 5.365 40.512 6.229 ;
     RECT  48.096 5.605 48.12 6.323 ;
     RECT  72.288 3.301 72.912 6.323 ;
     RECT  45.6 2.151 45.912 6.805 ;
     RECT  40.08 6.229 40.632 7.381 ;
     RECT  4.512 7.381 4.536 7.429 ;
     RECT  49.056 7.333 49.08 7.667 ;
     RECT  51 4.501 51.432 7.811 ;
     RECT  40.08 7.381 41.064 7.957 ;
     RECT  61.392 6.085 62.112 8.003 ;
     RECT  53.568 6.229 53.592 8.675 ;
     RECT  56.4 2.151 56.712 8.725 ;
     RECT  40.032 7.957 41.064 8.869 ;
     RECT  39.36 8.869 41.064 9.395 ;
     RECT  81.168 5.845 81.192 9.539 ;
     RECT  3.936 7.429 4.536 9.637 ;
     RECT  39.36 9.395 40.512 9.683 ;
     RECT  75.408 3.925 75.432 9.733 ;
     RECT  75.408 9.733 75.864 9.779 ;
     RECT  45.6 6.805 46.44 9.925 ;
     RECT  3.936 9.637 5.352 10.595 ;
     RECT  40.08 9.683 40.512 10.789 ;
     RECT  4.512 10.595 5.352 10.883 ;
     RECT  75.84 9.779 75.864 10.883 ;
     RECT  49.968 9.061 49.992 11.077 ;
     RECT  51 7.811 51.312 11.077 ;
     RECT  49.968 11.077 51.312 11.123 ;
     RECT  50.304 11.123 51.312 11.125 ;
     RECT  52.416 8.677 52.44 11.125 ;
     RECT  50.304 11.125 52.44 11.171 ;
     RECT  45.6 9.925 46.728 11.315 ;
     RECT  72.48 6.323 72.912 11.365 ;
     RECT  50.304 11.171 52.152 11.651 ;
     RECT  39.6 10.789 40.512 12.035 ;
     RECT  42.144 10.453 42.168 12.035 ;
     RECT  45.6 11.315 46.488 12.517 ;
     RECT  44.976 12.517 46.488 12.563 ;
     RECT  55.872 8.725 56.712 12.563 ;
     RECT  44.976 12.563 46.44 12.659 ;
     RECT  72.48 11.365 73.512 12.899 ;
     RECT  51 11.651 52.152 13.045 ;
     RECT  53.568 11.941 53.592 13.091 ;
     RECT  44.976 12.659 45.912 13.621 ;
     RECT  47.952 12.085 47.976 13.621 ;
     RECT  72.48 12.899 72.912 13.621 ;
     RECT  4.512 10.883 4.536 13.669 ;
     RECT  4.368 13.669 4.536 13.715 ;
     RECT  66.096 5.461 66.12 13.715 ;
     RECT  44.976 13.621 46.536 13.811 ;
     RECT  50.304 13.045 52.152 13.907 ;
     RECT  45.408 13.811 46.536 13.955 ;
     RECT  47.808 13.621 47.976 14.099 ;
     RECT  47.808 14.099 47.832 14.195 ;
     RECT  82.032 11.365 82.056 14.291 ;
     RECT  40.08 12.035 40.512 14.389 ;
     RECT  45.408 13.955 46.104 14.675 ;
     RECT  39.456 14.389 40.512 14.773 ;
     RECT  39.456 14.773 40.632 14.963 ;
     RECT  45.6 14.675 46.104 15.251 ;
     RECT  56.4 12.563 56.712 15.301 ;
     RECT  71.856 13.621 72.912 15.491 ;
     RECT  51 13.907 52.152 15.589 ;
     RECT  2.4 2.151 2.712 15.685 ;
     RECT  4.368 13.715 4.392 15.685 ;
     RECT  72.48 15.491 72.912 16.501 ;
     RECT  2.4 15.685 4.392 16.595 ;
     RECT  50.4 15.589 52.152 16.835 ;
     RECT  56.4 15.301 57.624 16.835 ;
     RECT  43.296 15.493 43.32 17.123 ;
     RECT  76.032 15.349 76.056 17.123 ;
     RECT  48.72 15.829 48.744 17.555 ;
     RECT  40.08 14.963 40.632 18.179 ;
     RECT  54.096 16.405 54.12 18.275 ;
     RECT  45.6 15.251 45.912 18.565 ;
     RECT  45.6 18.565 46.632 18.661 ;
     RECT  56.4 16.835 56.712 19.189 ;
     RECT  45.6 18.661 46.68 19.283 ;
     RECT  40.08 18.179 40.512 19.333 ;
     RECT  56.304 19.189 56.712 19.333 ;
     RECT  72.432 16.501 72.912 19.379 ;
     RECT  51 16.835 52.152 19.381 ;
     RECT  4.368 16.595 4.392 19.621 ;
     RECT  45.6 19.283 46.632 19.811 ;
     RECT  75.792 19.525 75.816 20.245 ;
     RECT  75.312 20.245 75.816 20.291 ;
     RECT  43.536 18.181 43.56 20.339 ;
     RECT  72.48 19.379 72.912 20.389 ;
     RECT  56.304 19.333 57.048 20.579 ;
     RECT  71.088 19.333 71.112 20.579 ;
     RECT  72.384 20.389 72.912 20.579 ;
     RECT  58.272 20.581 58.296 20.629 ;
     RECT  58.272 20.629 58.392 20.771 ;
     RECT  75.312 20.291 75.336 20.867 ;
     RECT  6.528 18.565 6.552 21.637 ;
     RECT  3.792 19.621 4.392 21.683 ;
     RECT  6.288 21.637 6.552 21.683 ;
     RECT  27.36 21.397 27.384 21.683 ;
     RECT  72.48 20.579 72.912 21.685 ;
     RECT  45.6 19.811 45.912 22.021 ;
     RECT  40.08 19.333 40.632 22.067 ;
     RECT  50.88 19.381 52.152 22.067 ;
     RECT  54.816 21.685 54.84 22.211 ;
     RECT  58.368 20.771 58.392 22.741 ;
     RECT  6.288 21.683 6.312 22.787 ;
     RECT  2.4 16.595 2.712 22.789 ;
     RECT  4.368 21.683 4.392 22.789 ;
     RECT  47.856 22.165 47.88 22.835 ;
     RECT  53.424 22.597 53.448 22.835 ;
     RECT  40.2 22.067 40.632 23.125 ;
     RECT  72.384 21.685 72.912 23.411 ;
     RECT  50.88 22.067 51.312 23.555 ;
     RECT  2.4 22.789 4.392 24.275 ;
     RECT  54.96 23.893 54.984 24.899 ;
     RECT  63.648 21.685 63.672 25.139 ;
     RECT  72.48 23.411 72.912 25.285 ;
     RECT  69.696 23.173 69.72 25.763 ;
     RECT  74.112 24.757 74.136 25.907 ;
     RECT  4.368 24.275 4.392 26.149 ;
     RECT  45.6 22.021 46.296 26.197 ;
     RECT  49.104 22.165 49.128 26.243 ;
     RECT  61.8 8.003 62.112 26.725 ;
     RECT  3.984 26.149 4.392 26.819 ;
     RECT  45.6 26.197 46.392 27.059 ;
     RECT  56.304 20.579 56.712 27.107 ;
     RECT  40.2 23.125 41.064 27.155 ;
     RECT  72.336 25.285 72.912 27.203 ;
     RECT  56.4 27.107 56.712 27.685 ;
     RECT  57.84 22.741 58.392 27.685 ;
     RECT  56.4 27.685 58.392 27.731 ;
     RECT  54.72 25.669 54.744 27.829 ;
     RECT  54.72 27.829 54.84 27.875 ;
     RECT  51 23.555 51.312 27.877 ;
     RECT  40.2 27.155 40.512 28.309 ;
     RECT  4.368 26.819 4.392 28.547 ;
     RECT  43.344 26.725 43.368 28.643 ;
     RECT  50.256 27.877 51.312 29.029 ;
     RECT  48.48 26.917 48.504 29.123 ;
     RECT  2.4 24.275 2.712 29.365 ;
     RECT  61.488 26.725 62.112 29.459 ;
     RECT  56.4 27.731 57.096 29.507 ;
     RECT  40.2 28.309 41.496 29.891 ;
     RECT  50.112 29.029 51.312 30.275 ;
     RECT  5.856 29.029 5.88 30.755 ;
     RECT  45.6 27.059 46.296 30.755 ;
     RECT  48.816 30.181 48.84 30.851 ;
     RECT  69.888 28.789 69.912 30.851 ;
     RECT  43.44 30.181 43.464 31.139 ;
     RECT  2.4 29.365 3.288 31.859 ;
     RECT  75.504 25.861 75.528 31.907 ;
     RECT  54.816 27.875 54.84 31.955 ;
     RECT  50.88 30.275 51.312 32.243 ;
     RECT  58.368 27.731 58.392 32.773 ;
     RECT  58.368 32.773 58.632 32.819 ;
     RECT  42.576 31.861 42.6 32.869 ;
     RECT  51 32.243 51.312 33.013 ;
     RECT  47.088 32.293 47.112 33.299 ;
     RECT  72.6 27.203 72.912 33.541 ;
     RECT  37.296 29.509 37.32 33.587 ;
     RECT  13.2 2.151 13.512 33.589 ;
     RECT  12.96 33.589 13.512 33.925 ;
     RECT  42.576 32.869 43.224 34.067 ;
     RECT  45.6 30.755 45.912 34.165 ;
     RECT  7.8 2.151 8.112 34.453 ;
     RECT  12.912 33.925 13.512 34.499 ;
     RECT  72.336 33.541 72.912 34.501 ;
     RECT  76.032 32.437 76.056 34.549 ;
     RECT  75.504 34.549 76.056 34.595 ;
     RECT  4.224 33.973 4.248 34.645 ;
     RECT  3.792 34.645 4.248 34.691 ;
     RECT  51 33.013 52.104 35.171 ;
     RECT  2.4 31.859 2.712 35.269 ;
     RECT  3.792 34.691 3.816 35.269 ;
     RECT  75.504 34.595 75.528 35.269 ;
     RECT  2.4 35.269 3.816 35.315 ;
     RECT  75.264 35.269 75.528 35.315 ;
     RECT  43.2 34.067 43.224 35.317 ;
     RECT  56.4 29.507 56.712 35.701 ;
     RECT  45.408 34.165 45.912 35.845 ;
     RECT  2.4 35.315 3.432 35.939 ;
     RECT  7.8 34.453 8.232 36.035 ;
     RECT  75.264 35.315 75.288 36.373 ;
     RECT  72 34.501 72.912 36.421 ;
     RECT  49.584 35.029 49.608 36.515 ;
     RECT  75.264 36.373 75.816 36.515 ;
     RECT  40.2 29.891 40.512 36.613 ;
     RECT  42.624 35.317 43.224 36.659 ;
     RECT  39.024 37.093 39.048 37.283 ;
     RECT  58.608 32.819 58.632 37.573 ;
     RECT  45.312 35.845 45.912 37.907 ;
     RECT  40.2 36.613 40.632 37.957 ;
     RECT  39.84 37.957 40.632 38.003 ;
     RECT  58.128 37.573 58.632 38.147 ;
     RECT  51 35.171 51.312 38.149 ;
     RECT  66.048 36.421 66.072 38.197 ;
     RECT  75.792 36.515 75.816 38.629 ;
     RECT  52.416 37.621 52.44 38.675 ;
     RECT  75.312 38.629 75.816 38.675 ;
     RECT  71.952 36.421 72.912 38.749 ;
     RECT  56.4 35.701 56.952 38.773 ;
     RECT  66.048 38.197 66.12 38.773 ;
     RECT  55.584 38.773 56.952 39.251 ;
     RECT  56.4 39.251 56.952 39.301 ;
     RECT  66 38.773 66.12 39.301 ;
     RECT  65.568 39.301 66.12 39.347 ;
     RECT  75.312 38.675 75.48 39.395 ;
     RECT  50.88 38.149 51.312 39.491 ;
     RECT  37.824 37.573 37.848 39.587 ;
     RECT  49.2 37.573 49.224 39.635 ;
     RECT  72 38.749 72.912 39.637 ;
     RECT  39.84 38.003 40.512 39.781 ;
     RECT  75.456 39.395 75.48 39.923 ;
     RECT  72 39.637 73.704 40.165 ;
     RECT  45.6 37.907 45.912 40.597 ;
     RECT  39.6 39.781 40.512 40.691 ;
     RECT  65.568 39.347 66.024 40.835 ;
     RECT  66 40.835 66.024 40.883 ;
     RECT  71.952 40.165 73.704 40.883 ;
     RECT  67.2 2.151 67.512 41.125 ;
     RECT  72.6 40.883 73.704 41.171 ;
     RECT  3.936 41.605 3.96 42.133 ;
     RECT  12.96 34.499 13.512 42.179 ;
     RECT  40.08 40.691 40.512 42.757 ;
     RECT  6.048 38.149 6.072 42.803 ;
     RECT  27.072 21.685 27.096 42.803 ;
     RECT  58.608 38.147 58.632 42.803 ;
     RECT  45.6 40.597 46.728 42.995 ;
     RECT  13.056 42.179 13.512 43.043 ;
     RECT  56.4 39.301 57 43.283 ;
     RECT  59.088 42.997 59.112 43.811 ;
     RECT  48.96 40.693 48.984 44.293 ;
     RECT  63.84 41.269 63.864 44.579 ;
     RECT  83.4 2.151 83.712 44.725 ;
     RECT  45.6 42.995 45.912 44.917 ;
     RECT  61.8 29.459 62.112 44.965 ;
     RECT  48.72 44.293 48.984 45.059 ;
     RECT  3.936 42.133 4.488 45.155 ;
     RECT  52.992 43.285 53.016 45.157 ;
     RECT  48.768 45.059 48.984 45.443 ;
     RECT  83.4 44.725 83.928 45.443 ;
     RECT  52.368 45.157 53.016 45.731 ;
     RECT  39.936 42.757 40.512 46.069 ;
     RECT  52.368 45.731 52.392 46.211 ;
     RECT  61.8 44.965 62.664 46.211 ;
     RECT  45.6 44.917 46.008 46.259 ;
     RECT  43.2 36.659 43.224 47.269 ;
     RECT  45.6 46.259 45.912 47.269 ;
     RECT  59.808 44.965 59.832 47.363 ;
     RECT  39.936 46.069 41.016 47.845 ;
     RECT  39.888 47.845 41.016 47.891 ;
     RECT  45.36 47.269 45.912 48.275 ;
     RECT  51 39.491 51.312 48.421 ;
     RECT  43.056 47.269 43.224 48.803 ;
     RECT  4.464 45.155 4.488 49.429 ;
     RECT  4.368 49.429 4.488 49.475 ;
     RECT  6.048 45.013 6.072 49.525 ;
     RECT  5.904 49.525 6.072 49.571 ;
     RECT  51 48.421 52.248 49.619 ;
     RECT  54.144 48.997 54.168 49.763 ;
     RECT  39.888 47.891 40.512 50.003 ;
     RECT  45.6 48.275 45.912 50.053 ;
     RECT  67.2 41.125 67.608 50.195 ;
     RECT  48.768 45.443 48.792 50.533 ;
     RECT  49.968 49.525 49.992 50.533 ;
     RECT  5.904 49.571 5.928 50.579 ;
     RECT  48.768 50.533 49.992 50.579 ;
     RECT  56.4 43.283 56.904 50.579 ;
     RECT  49.104 50.579 49.992 50.723 ;
     RECT  63.792 48.229 63.816 50.965 ;
     RECT  45.6 50.053 46.008 51.347 ;
     RECT  56.4 50.579 56.856 51.347 ;
     RECT  4.368 49.475 4.392 51.781 ;
     RECT  63.792 50.965 64.344 51.781 ;
     RECT  45.6 51.347 45.912 52.309 ;
     RECT  7.8 36.035 8.112 52.357 ;
     RECT  60.624 50.389 60.648 52.691 ;
     RECT  51 49.619 51.312 52.885 ;
     RECT  49.104 50.723 49.128 52.981 ;
     RECT  49.008 52.981 49.128 53.027 ;
     RECT  57.888 50.533 57.912 53.075 ;
     RECT  45.6 52.309 46.632 53.603 ;
     RECT  50.544 52.885 51.312 53.603 ;
     RECT  52.32 51.781 52.344 53.795 ;
     RECT  4.032 51.781 4.392 53.843 ;
     RECT  49.008 53.027 49.032 54.085 ;
     RECT  6.912 52.357 8.112 54.371 ;
     RECT  49.008 54.085 49.416 54.565 ;
     RECT  56.4 51.347 56.712 54.661 ;
     RECT  55.632 54.661 56.712 54.803 ;
     RECT  48.96 54.565 49.416 55.187 ;
     RECT  37.296 51.061 37.32 55.283 ;
     RECT  54.384 54.613 54.408 55.331 ;
     RECT  2.4 35.939 2.712 55.765 ;
     RECT  63.744 51.781 64.344 55.907 ;
     RECT  2.4 55.765 2.808 56.243 ;
     RECT  34.8 2.151 35.112 56.389 ;
     RECT  4.368 53.843 4.392 56.483 ;
     RECT  7.248 54.371 8.112 56.483 ;
     RECT  39.936 50.003 40.512 56.485 ;
     RECT  29.4 2.151 29.712 56.869 ;
     RECT  39.888 56.485 40.512 57.541 ;
     RECT  34.032 56.389 35.112 57.635 ;
     RECT  36.672 56.869 36.696 57.635 ;
     RECT  49.392 55.187 49.416 58.163 ;
     RECT  29.4 56.869 29.832 58.355 ;
     RECT  2.4 56.243 2.712 58.597 ;
     RECT  3.936 56.965 3.96 58.597 ;
     RECT  2.4 58.597 3.96 58.643 ;
     RECT  64.32 55.907 64.344 59.603 ;
     RECT  47.088 58.117 47.112 59.605 ;
     RECT  47.088 59.605 47.352 59.651 ;
     RECT  2.4 58.643 3.624 59.795 ;
     RECT  53.856 56.533 53.88 59.891 ;
     RECT  39.888 57.541 40.632 59.987 ;
     RECT  38.496 57.589 38.52 60.133 ;
     RECT  32.16 58.645 32.184 60.179 ;
     RECT  37.584 60.133 38.52 60.179 ;
     RECT  40.2 59.987 40.632 60.323 ;
     RECT  34.8 57.635 35.112 60.373 ;
     RECT  37.584 60.179 37.608 60.995 ;
     RECT  34.656 60.373 35.112 61.043 ;
     RECT  47.328 59.651 47.352 61.043 ;
     RECT  81.456 60.421 81.48 61.379 ;
     RECT  34.8 61.043 35.112 62.581 ;
     RECT  2.4 59.795 2.712 62.649 ;
     RECT  7.8 56.483 8.112 62.649 ;
     RECT  13.2 43.043 13.512 62.649 ;
     RECT  18.6 2.151 18.912 62.649 ;
     RECT  24 2.151 24.312 62.649 ;
     RECT  29.4 58.355 29.712 62.649 ;
     RECT  40.2 60.323 40.512 62.649 ;
     RECT  45.6 53.603 45.912 62.649 ;
     RECT  51 53.603 51.312 62.649 ;
     RECT  61.8 46.211 62.112 62.649 ;
     RECT  67.2 50.195 67.512 62.649 ;
     RECT  72.6 41.171 72.912 62.649 ;
     RECT  78 2.151 78.312 62.649 ;
     RECT  83.4 45.443 83.712 62.649 ;
     RECT  2.4 62.649 2.52 62.663 ;
     RECT  7.8 62.649 7.92 62.663 ;
     RECT  13.2 62.649 13.32 62.663 ;
     RECT  18.6 62.649 18.72 62.663 ;
     RECT  24 62.649 24.12 62.663 ;
     RECT  29.4 62.649 29.52 62.663 ;
     RECT  34.8 62.581 35.208 62.663 ;
     RECT  40.2 62.649 40.32 62.663 ;
     RECT  45.6 62.649 45.72 62.663 ;
     RECT  51 62.649 51.12 62.663 ;
     RECT  56.4 54.803 56.712 62.663 ;
     RECT  61.8 62.649 61.92 62.663 ;
     RECT  67.2 62.649 67.32 62.663 ;
     RECT  72.6 62.649 72.72 62.663 ;
     RECT  78 62.649 78.12 62.663 ;
     RECT  83.4 62.649 83.52 62.663 ;
     RECT  30.864 62.581 30.888 64.645 ;
     RECT  35.184 62.663 35.208 64.645 ;
     RECT  30.768 64.645 30.888 64.691 ;
     RECT  35.088 64.645 35.208 64.691 ;
     RECT  30.768 64.691 30.792 64.784 ;
     RECT  35.088 64.691 35.112 64.784 ;
     RECT  43.2 48.803 43.224 64.784 ;
     RECT  50.736 63.829 50.76 64.784 ;
     RECT  56.688 62.663 56.712 64.784 ;
  END
END ot_s81hd_lsc_t8
END LIBRARY
